VERSION 5.8 ;
BUSBITCHARS "[]" ;
DIVIDERCHAR "/" ;
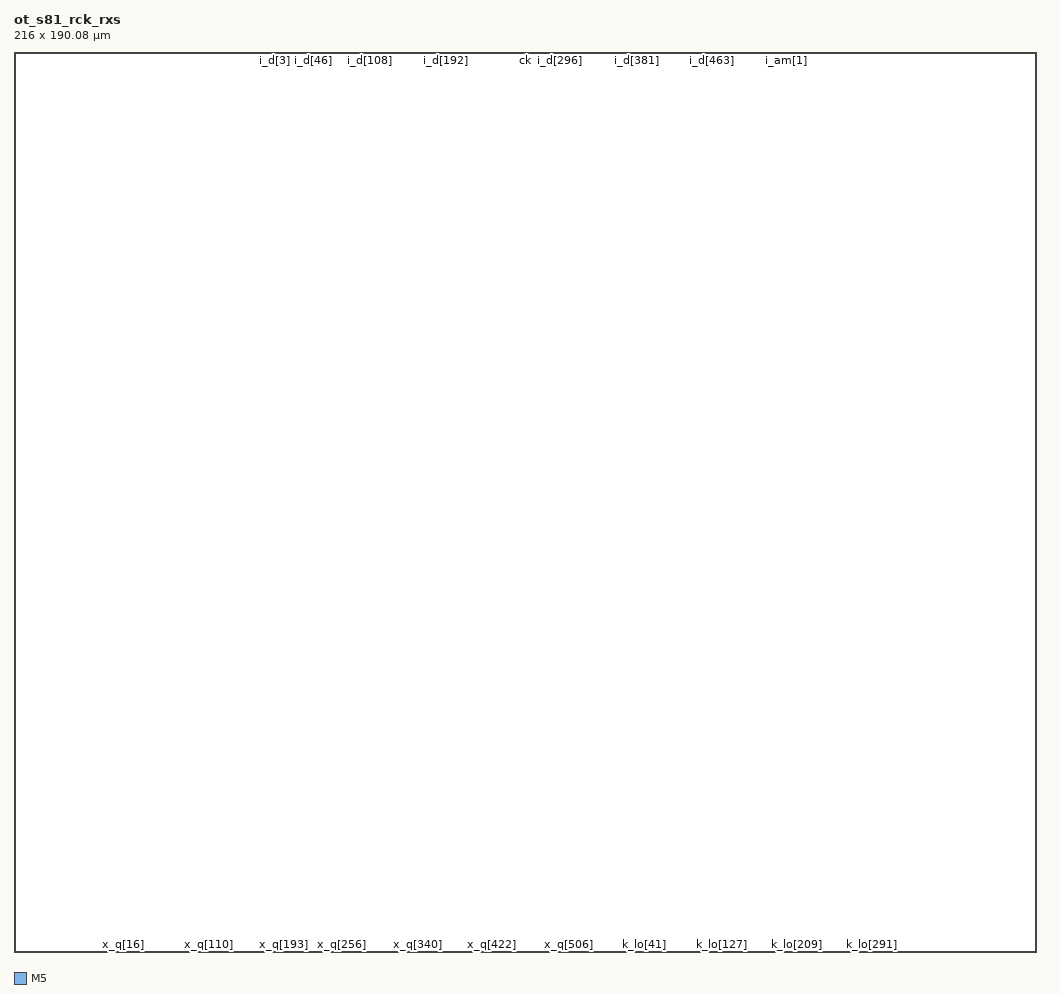
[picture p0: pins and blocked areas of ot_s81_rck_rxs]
MACRO ot_s81_rck_rxs
 CLASS BLOCK ;
 ORIGIN 0 0 ;
 SIZE 216.0 BY 190.08 ;
 SYMMETRY X Y ;
 PIN rst_n
  DIRECTION INPUT ;
  USE SIGNAL ;
  PORT
   LAYER M5 ;
   RECT 54.048 189.996 54.072 190.080 ;
  END
 END rst_n
 PIN i_v
  DIRECTION INPUT ;
  USE SIGNAL ;
  PORT
   LAYER M5 ;
   RECT 54.240 189.996 54.264 190.080 ;
  END
 END i_v
 PIN i_d[0]
  DIRECTION INPUT ;
  USE SIGNAL ;
  PORT
   LAYER M5 ;
   RECT 54.432 189.996 54.456 190.080 ;
  END
 END i_d[0]
 PIN i_d[1]
  DIRECTION INPUT ;
  USE SIGNAL ;
  PORT
   LAYER M5 ;
   RECT 54.624 189.996 54.648 190.080 ;
  END
 END i_d[1]
 PIN i_d[2]
  DIRECTION INPUT ;
  USE SIGNAL ;
  PORT
   LAYER M5 ;
   RECT 54.816 189.996 54.840 190.080 ;
  END
 END i_d[2]
 PIN i_d[3]
  DIRECTION INPUT ;
  USE SIGNAL ;
  PORT
   LAYER M5 ;
   RECT 55.008 189.996 55.032 190.080 ;
  END
 END i_d[3]
 PIN i_d[4]
  DIRECTION INPUT ;
  USE SIGNAL ;
  PORT
   LAYER M5 ;
   RECT 55.200 189.996 55.224 190.080 ;
  END
 END i_d[4]
 PIN i_d[5]
  DIRECTION INPUT ;
  USE SIGNAL ;
  PORT
   LAYER M5 ;
   RECT 55.392 189.996 55.416 190.080 ;
  END
 END i_d[5]
 PIN i_d[6]
  DIRECTION INPUT ;
  USE SIGNAL ;
  PORT
   LAYER M5 ;
   RECT 55.584 189.996 55.608 190.080 ;
  END
 END i_d[6]
 PIN i_d[7]
  DIRECTION INPUT ;
  USE SIGNAL ;
  PORT
   LAYER M5 ;
   RECT 55.776 189.996 55.800 190.080 ;
  END
 END i_d[7]
 PIN i_d[8]
  DIRECTION INPUT ;
  USE SIGNAL ;
  PORT
   LAYER M5 ;
   RECT 55.968 189.996 55.992 190.080 ;
  END
 END i_d[8]
 PIN i_d[9]
  DIRECTION INPUT ;
  USE SIGNAL ;
  PORT
   LAYER M5 ;
   RECT 56.160 189.996 56.184 190.080 ;
  END
 END i_d[9]
 PIN i_d[10]
  DIRECTION INPUT ;
  USE SIGNAL ;
  PORT
   LAYER M5 ;
   RECT 56.352 189.996 56.376 190.080 ;
  END
 END i_d[10]
 PIN i_d[11]
  DIRECTION INPUT ;
  USE SIGNAL ;
  PORT
   LAYER M5 ;
   RECT 56.544 189.996 56.568 190.080 ;
  END
 END i_d[11]
 PIN i_d[12]
  DIRECTION INPUT ;
  USE SIGNAL ;
  PORT
   LAYER M5 ;
   RECT 56.736 189.996 56.760 190.080 ;
  END
 END i_d[12]
 PIN i_d[13]
  DIRECTION INPUT ;
  USE SIGNAL ;
  PORT
   LAYER M5 ;
   RECT 56.928 189.996 56.952 190.080 ;
  END
 END i_d[13]
 PIN i_d[14]
  DIRECTION INPUT ;
  USE SIGNAL ;
  PORT
   LAYER M5 ;
   RECT 57.120 189.996 57.144 190.080 ;
  END
 END i_d[14]
 PIN i_d[15]
  DIRECTION INPUT ;
  USE SIGNAL ;
  PORT
   LAYER M5 ;
   RECT 57.312 189.996 57.336 190.080 ;
  END
 END i_d[15]
 PIN i_d[16]
  DIRECTION INPUT ;
  USE SIGNAL ;
  PORT
   LAYER M5 ;
   RECT 57.504 189.996 57.528 190.080 ;
  END
 END i_d[16]
 PIN i_d[17]
  DIRECTION INPUT ;
  USE SIGNAL ;
  PORT
   LAYER M5 ;
   RECT 57.696 189.996 57.720 190.080 ;
  END
 END i_d[17]
 PIN i_d[18]
  DIRECTION INPUT ;
  USE SIGNAL ;
  PORT
   LAYER M5 ;
   RECT 57.888 189.996 57.912 190.080 ;
  END
 END i_d[18]
 PIN i_d[19]
  DIRECTION INPUT ;
  USE SIGNAL ;
  PORT
   LAYER M5 ;
   RECT 58.080 189.996 58.104 190.080 ;
  END
 END i_d[19]
 PIN i_d[20]
  DIRECTION INPUT ;
  USE SIGNAL ;
  PORT
   LAYER M5 ;
   RECT 58.272 189.996 58.296 190.080 ;
  END
 END i_d[20]
 PIN i_d[21]
  DIRECTION INPUT ;
  USE SIGNAL ;
  PORT
   LAYER M5 ;
   RECT 58.464 189.996 58.488 190.080 ;
  END
 END i_d[21]
 PIN i_d[22]
  DIRECTION INPUT ;
  USE SIGNAL ;
  PORT
   LAYER M5 ;
   RECT 58.656 189.996 58.680 190.080 ;
  END
 END i_d[22]
 PIN i_d[23]
  DIRECTION INPUT ;
  USE SIGNAL ;
  PORT
   LAYER M5 ;
   RECT 58.848 189.996 58.872 190.080 ;
  END
 END i_d[23]
 PIN i_d[24]
  DIRECTION INPUT ;
  USE SIGNAL ;
  PORT
   LAYER M5 ;
   RECT 59.040 189.996 59.064 190.080 ;
  END
 END i_d[24]
 PIN i_d[25]
  DIRECTION INPUT ;
  USE SIGNAL ;
  PORT
   LAYER M5 ;
   RECT 59.232 189.996 59.256 190.080 ;
  END
 END i_d[25]
 PIN i_d[26]
  DIRECTION INPUT ;
  USE SIGNAL ;
  PORT
   LAYER M5 ;
   RECT 59.424 189.996 59.448 190.080 ;
  END
 END i_d[26]
 PIN i_d[27]
  DIRECTION INPUT ;
  USE SIGNAL ;
  PORT
   LAYER M5 ;
   RECT 59.616 189.996 59.640 190.080 ;
  END
 END i_d[27]
 PIN i_d[28]
  DIRECTION INPUT ;
  USE SIGNAL ;
  PORT
   LAYER M5 ;
   RECT 59.808 189.996 59.832 190.080 ;
  END
 END i_d[28]
 PIN i_d[29]
  DIRECTION INPUT ;
  USE SIGNAL ;
  PORT
   LAYER M5 ;
   RECT 60.000 189.996 60.024 190.080 ;
  END
 END i_d[29]
 PIN i_d[30]
  DIRECTION INPUT ;
  USE SIGNAL ;
  PORT
   LAYER M5 ;
   RECT 60.192 189.996 60.216 190.080 ;
  END
 END i_d[30]
 PIN i_d[31]
  DIRECTION INPUT ;
  USE SIGNAL ;
  PORT
   LAYER M5 ;
   RECT 60.384 189.996 60.408 190.080 ;
  END
 END i_d[31]
 PIN i_d[32]
  DIRECTION INPUT ;
  USE SIGNAL ;
  PORT
   LAYER M5 ;
   RECT 60.576 189.996 60.600 190.080 ;
  END
 END i_d[32]
 PIN i_d[33]
  DIRECTION INPUT ;
  USE SIGNAL ;
  PORT
   LAYER M5 ;
   RECT 60.768 189.996 60.792 190.080 ;
  END
 END i_d[33]
 PIN i_d[34]
  DIRECTION INPUT ;
  USE SIGNAL ;
  PORT
   LAYER M5 ;
   RECT 60.960 189.996 60.984 190.080 ;
  END
 END i_d[34]
 PIN i_d[35]
  DIRECTION INPUT ;
  USE SIGNAL ;
  PORT
   LAYER M5 ;
   RECT 61.152 189.996 61.176 190.080 ;
  END
 END i_d[35]
 PIN i_d[36]
  DIRECTION INPUT ;
  USE SIGNAL ;
  PORT
   LAYER M5 ;
   RECT 61.344 189.996 61.368 190.080 ;
  END
 END i_d[36]
 PIN i_d[37]
  DIRECTION INPUT ;
  USE SIGNAL ;
  PORT
   LAYER M5 ;
   RECT 61.536 189.996 61.560 190.080 ;
  END
 END i_d[37]
 PIN i_d[38]
  DIRECTION INPUT ;
  USE SIGNAL ;
  PORT
   LAYER M5 ;
   RECT 61.728 189.996 61.752 190.080 ;
  END
 END i_d[38]
 PIN i_d[39]
  DIRECTION INPUT ;
  USE SIGNAL ;
  PORT
   LAYER M5 ;
   RECT 61.920 189.996 61.944 190.080 ;
  END
 END i_d[39]
 PIN i_d[40]
  DIRECTION INPUT ;
  USE SIGNAL ;
  PORT
   LAYER M5 ;
   RECT 62.112 189.996 62.136 190.080 ;
  END
 END i_d[40]
 PIN i_d[41]
  DIRECTION INPUT ;
  USE SIGNAL ;
  PORT
   LAYER M5 ;
   RECT 62.304 189.996 62.328 190.080 ;
  END
 END i_d[41]
 PIN i_d[42]
  DIRECTION INPUT ;
  USE SIGNAL ;
  PORT
   LAYER M5 ;
   RECT 62.496 189.996 62.520 190.080 ;
  END
 END i_d[42]
 PIN i_d[43]
  DIRECTION INPUT ;
  USE SIGNAL ;
  PORT
   LAYER M5 ;
   RECT 62.688 189.996 62.712 190.080 ;
  END
 END i_d[43]
 PIN i_d[44]
  DIRECTION INPUT ;
  USE SIGNAL ;
  PORT
   LAYER M5 ;
   RECT 62.880 189.996 62.904 190.080 ;
  END
 END i_d[44]
 PIN i_d[45]
  DIRECTION INPUT ;
  USE SIGNAL ;
  PORT
   LAYER M5 ;
   RECT 63.072 189.996 63.096 190.080 ;
  END
 END i_d[45]
 PIN i_d[46]
  DIRECTION INPUT ;
  USE SIGNAL ;
  PORT
   LAYER M5 ;
   RECT 63.264 189.996 63.288 190.080 ;
  END
 END i_d[46]
 PIN i_d[47]
  DIRECTION INPUT ;
  USE SIGNAL ;
  PORT
   LAYER M5 ;
   RECT 63.456 189.996 63.480 190.080 ;
  END
 END i_d[47]
 PIN i_d[48]
  DIRECTION INPUT ;
  USE SIGNAL ;
  PORT
   LAYER M5 ;
   RECT 63.648 189.996 63.672 190.080 ;
  END
 END i_d[48]
 PIN i_d[49]
  DIRECTION INPUT ;
  USE SIGNAL ;
  PORT
   LAYER M5 ;
   RECT 63.840 189.996 63.864 190.080 ;
  END
 END i_d[49]
 PIN i_d[50]
  DIRECTION INPUT ;
  USE SIGNAL ;
  PORT
   LAYER M5 ;
   RECT 64.032 189.996 64.056 190.080 ;
  END
 END i_d[50]
 PIN i_d[51]
  DIRECTION INPUT ;
  USE SIGNAL ;
  PORT
   LAYER M5 ;
   RECT 64.224 189.996 64.248 190.080 ;
  END
 END i_d[51]
 PIN i_d[52]
  DIRECTION INPUT ;
  USE SIGNAL ;
  PORT
   LAYER M5 ;
   RECT 64.416 189.996 64.440 190.080 ;
  END
 END i_d[52]
 PIN i_d[53]
  DIRECTION INPUT ;
  USE SIGNAL ;
  PORT
   LAYER M5 ;
   RECT 64.608 189.996 64.632 190.080 ;
  END
 END i_d[53]
 PIN i_d[54]
  DIRECTION INPUT ;
  USE SIGNAL ;
  PORT
   LAYER M5 ;
   RECT 64.800 189.996 64.824 190.080 ;
  END
 END i_d[54]
 PIN i_d[55]
  DIRECTION INPUT ;
  USE SIGNAL ;
  PORT
   LAYER M5 ;
   RECT 64.992 189.996 65.016 190.080 ;
  END
 END i_d[55]
 PIN i_d[56]
  DIRECTION INPUT ;
  USE SIGNAL ;
  PORT
   LAYER M5 ;
   RECT 65.184 189.996 65.208 190.080 ;
  END
 END i_d[56]
 PIN i_d[57]
  DIRECTION INPUT ;
  USE SIGNAL ;
  PORT
   LAYER M5 ;
   RECT 65.376 189.996 65.400 190.080 ;
  END
 END i_d[57]
 PIN i_d[58]
  DIRECTION INPUT ;
  USE SIGNAL ;
  PORT
   LAYER M5 ;
   RECT 65.568 189.996 65.592 190.080 ;
  END
 END i_d[58]
 PIN i_d[59]
  DIRECTION INPUT ;
  USE SIGNAL ;
  PORT
   LAYER M5 ;
   RECT 65.760 189.996 65.784 190.080 ;
  END
 END i_d[59]
 PIN i_d[60]
  DIRECTION INPUT ;
  USE SIGNAL ;
  PORT
   LAYER M5 ;
   RECT 65.952 189.996 65.976 190.080 ;
  END
 END i_d[60]
 PIN i_d[61]
  DIRECTION INPUT ;
  USE SIGNAL ;
  PORT
   LAYER M5 ;
   RECT 66.144 189.996 66.168 190.080 ;
  END
 END i_d[61]
 PIN i_d[62]
  DIRECTION INPUT ;
  USE SIGNAL ;
  PORT
   LAYER M5 ;
   RECT 66.336 189.996 66.360 190.080 ;
  END
 END i_d[62]
 PIN i_d[63]
  DIRECTION INPUT ;
  USE SIGNAL ;
  PORT
   LAYER M5 ;
   RECT 66.528 189.996 66.552 190.080 ;
  END
 END i_d[63]
 PIN i_d[64]
  DIRECTION INPUT ;
  USE SIGNAL ;
  PORT
   LAYER M5 ;
   RECT 66.720 189.996 66.744 190.080 ;
  END
 END i_d[64]
 PIN i_d[65]
  DIRECTION INPUT ;
  USE SIGNAL ;
  PORT
   LAYER M5 ;
   RECT 66.912 189.996 66.936 190.080 ;
  END
 END i_d[65]
 PIN i_d[66]
  DIRECTION INPUT ;
  USE SIGNAL ;
  PORT
   LAYER M5 ;
   RECT 67.104 189.996 67.128 190.080 ;
  END
 END i_d[66]
 PIN i_d[67]
  DIRECTION INPUT ;
  USE SIGNAL ;
  PORT
   LAYER M5 ;
   RECT 67.296 189.996 67.320 190.080 ;
  END
 END i_d[67]
 PIN i_d[68]
  DIRECTION INPUT ;
  USE SIGNAL ;
  PORT
   LAYER M5 ;
   RECT 67.488 189.996 67.512 190.080 ;
  END
 END i_d[68]
 PIN i_d[69]
  DIRECTION INPUT ;
  USE SIGNAL ;
  PORT
   LAYER M5 ;
   RECT 67.680 189.996 67.704 190.080 ;
  END
 END i_d[69]
 PIN i_d[70]
  DIRECTION INPUT ;
  USE SIGNAL ;
  PORT
   LAYER M5 ;
   RECT 67.872 189.996 67.896 190.080 ;
  END
 END i_d[70]
 PIN i_d[71]
  DIRECTION INPUT ;
  USE SIGNAL ;
  PORT
   LAYER M5 ;
   RECT 68.064 189.996 68.088 190.080 ;
  END
 END i_d[71]
 PIN i_d[72]
  DIRECTION INPUT ;
  USE SIGNAL ;
  PORT
   LAYER M5 ;
   RECT 68.256 189.996 68.280 190.080 ;
  END
 END i_d[72]
 PIN i_d[73]
  DIRECTION INPUT ;
  USE SIGNAL ;
  PORT
   LAYER M5 ;
   RECT 68.448 189.996 68.472 190.080 ;
  END
 END i_d[73]
 PIN i_d[74]
  DIRECTION INPUT ;
  USE SIGNAL ;
  PORT
   LAYER M5 ;
   RECT 68.640 189.996 68.664 190.080 ;
  END
 END i_d[74]
 PIN i_d[75]
  DIRECTION INPUT ;
  USE SIGNAL ;
  PORT
   LAYER M5 ;
   RECT 68.832 189.996 68.856 190.080 ;
  END
 END i_d[75]
 PIN i_d[76]
  DIRECTION INPUT ;
  USE SIGNAL ;
  PORT
   LAYER M5 ;
   RECT 69.024 189.996 69.048 190.080 ;
  END
 END i_d[76]
 PIN i_d[77]
  DIRECTION INPUT ;
  USE SIGNAL ;
  PORT
   LAYER M5 ;
   RECT 69.216 189.996 69.240 190.080 ;
  END
 END i_d[77]
 PIN i_d[78]
  DIRECTION INPUT ;
  USE SIGNAL ;
  PORT
   LAYER M5 ;
   RECT 69.408 189.996 69.432 190.080 ;
  END
 END i_d[78]
 PIN i_d[79]
  DIRECTION INPUT ;
  USE SIGNAL ;
  PORT
   LAYER M5 ;
   RECT 69.600 189.996 69.624 190.080 ;
  END
 END i_d[79]
 PIN i_d[80]
  DIRECTION INPUT ;
  USE SIGNAL ;
  PORT
   LAYER M5 ;
   RECT 69.792 189.996 69.816 190.080 ;
  END
 END i_d[80]
 PIN i_d[81]
  DIRECTION INPUT ;
  USE SIGNAL ;
  PORT
   LAYER M5 ;
   RECT 69.984 189.996 70.008 190.080 ;
  END
 END i_d[81]
 PIN i_d[82]
  DIRECTION INPUT ;
  USE SIGNAL ;
  PORT
   LAYER M5 ;
   RECT 70.176 189.996 70.200 190.080 ;
  END
 END i_d[82]
 PIN i_d[83]
  DIRECTION INPUT ;
  USE SIGNAL ;
  PORT
   LAYER M5 ;
   RECT 70.368 189.996 70.392 190.080 ;
  END
 END i_d[83]
 PIN i_d[84]
  DIRECTION INPUT ;
  USE SIGNAL ;
  PORT
   LAYER M5 ;
   RECT 70.560 189.996 70.584 190.080 ;
  END
 END i_d[84]
 PIN i_d[85]
  DIRECTION INPUT ;
  USE SIGNAL ;
  PORT
   LAYER M5 ;
   RECT 70.752 189.996 70.776 190.080 ;
  END
 END i_d[85]
 PIN i_d[86]
  DIRECTION INPUT ;
  USE SIGNAL ;
  PORT
   LAYER M5 ;
   RECT 70.944 189.996 70.968 190.080 ;
  END
 END i_d[86]
 PIN i_d[87]
  DIRECTION INPUT ;
  USE SIGNAL ;
  PORT
   LAYER M5 ;
   RECT 71.136 189.996 71.160 190.080 ;
  END
 END i_d[87]
 PIN i_d[88]
  DIRECTION INPUT ;
  USE SIGNAL ;
  PORT
   LAYER M5 ;
   RECT 71.328 189.996 71.352 190.080 ;
  END
 END i_d[88]
 PIN i_d[89]
  DIRECTION INPUT ;
  USE SIGNAL ;
  PORT
   LAYER M5 ;
   RECT 71.520 189.996 71.544 190.080 ;
  END
 END i_d[89]
 PIN i_d[90]
  DIRECTION INPUT ;
  USE SIGNAL ;
  PORT
   LAYER M5 ;
   RECT 71.712 189.996 71.736 190.080 ;
  END
 END i_d[90]
 PIN i_d[91]
  DIRECTION INPUT ;
  USE SIGNAL ;
  PORT
   LAYER M5 ;
   RECT 71.904 189.996 71.928 190.080 ;
  END
 END i_d[91]
 PIN i_d[92]
  DIRECTION INPUT ;
  USE SIGNAL ;
  PORT
   LAYER M5 ;
   RECT 72.096 189.996 72.120 190.080 ;
  END
 END i_d[92]
 PIN i_d[93]
  DIRECTION INPUT ;
  USE SIGNAL ;
  PORT
   LAYER M5 ;
   RECT 72.288 189.996 72.312 190.080 ;
  END
 END i_d[93]
 PIN i_d[94]
  DIRECTION INPUT ;
  USE SIGNAL ;
  PORT
   LAYER M5 ;
   RECT 72.480 189.996 72.504 190.080 ;
  END
 END i_d[94]
 PIN i_d[95]
  DIRECTION INPUT ;
  USE SIGNAL ;
  PORT
   LAYER M5 ;
   RECT 72.672 189.996 72.696 190.080 ;
  END
 END i_d[95]
 PIN i_d[96]
  DIRECTION INPUT ;
  USE SIGNAL ;
  PORT
   LAYER M5 ;
   RECT 72.864 189.996 72.888 190.080 ;
  END
 END i_d[96]
 PIN i_d[97]
  DIRECTION INPUT ;
  USE SIGNAL ;
  PORT
   LAYER M5 ;
   RECT 73.056 189.996 73.080 190.080 ;
  END
 END i_d[97]
 PIN i_d[98]
  DIRECTION INPUT ;
  USE SIGNAL ;
  PORT
   LAYER M5 ;
   RECT 73.248 189.996 73.272 190.080 ;
  END
 END i_d[98]
 PIN i_d[99]
  DIRECTION INPUT ;
  USE SIGNAL ;
  PORT
   LAYER M5 ;
   RECT 73.440 189.996 73.464 190.080 ;
  END
 END i_d[99]
 PIN i_d[100]
  DIRECTION INPUT ;
  USE SIGNAL ;
  PORT
   LAYER M5 ;
   RECT 73.632 189.996 73.656 190.080 ;
  END
 END i_d[100]
 PIN i_d[101]
  DIRECTION INPUT ;
  USE SIGNAL ;
  PORT
   LAYER M5 ;
   RECT 73.824 189.996 73.848 190.080 ;
  END
 END i_d[101]
 PIN i_d[102]
  DIRECTION INPUT ;
  USE SIGNAL ;
  PORT
   LAYER M5 ;
   RECT 74.016 189.996 74.040 190.080 ;
  END
 END i_d[102]
 PIN i_d[103]
  DIRECTION INPUT ;
  USE SIGNAL ;
  PORT
   LAYER M5 ;
   RECT 74.208 189.996 74.232 190.080 ;
  END
 END i_d[103]
 PIN i_d[104]
  DIRECTION INPUT ;
  USE SIGNAL ;
  PORT
   LAYER M5 ;
   RECT 74.400 189.996 74.424 190.080 ;
  END
 END i_d[104]
 PIN i_d[105]
  DIRECTION INPUT ;
  USE SIGNAL ;
  PORT
   LAYER M5 ;
   RECT 74.592 189.996 74.616 190.080 ;
  END
 END i_d[105]
 PIN i_d[106]
  DIRECTION INPUT ;
  USE SIGNAL ;
  PORT
   LAYER M5 ;
   RECT 74.784 189.996 74.808 190.080 ;
  END
 END i_d[106]
 PIN i_d[107]
  DIRECTION INPUT ;
  USE SIGNAL ;
  PORT
   LAYER M5 ;
   RECT 74.976 189.996 75.000 190.080 ;
  END
 END i_d[107]
 PIN i_d[108]
  DIRECTION INPUT ;
  USE SIGNAL ;
  PORT
   LAYER M5 ;
   RECT 75.168 189.996 75.192 190.080 ;
  END
 END i_d[108]
 PIN i_d[109]
  DIRECTION INPUT ;
  USE SIGNAL ;
  PORT
   LAYER M5 ;
   RECT 75.360 189.996 75.384 190.080 ;
  END
 END i_d[109]
 PIN i_d[110]
  DIRECTION INPUT ;
  USE SIGNAL ;
  PORT
   LAYER M5 ;
   RECT 75.552 189.996 75.576 190.080 ;
  END
 END i_d[110]
 PIN i_d[111]
  DIRECTION INPUT ;
  USE SIGNAL ;
  PORT
   LAYER M5 ;
   RECT 75.744 189.996 75.768 190.080 ;
  END
 END i_d[111]
 PIN i_d[112]
  DIRECTION INPUT ;
  USE SIGNAL ;
  PORT
   LAYER M5 ;
   RECT 75.936 189.996 75.960 190.080 ;
  END
 END i_d[112]
 PIN i_d[113]
  DIRECTION INPUT ;
  USE SIGNAL ;
  PORT
   LAYER M5 ;
   RECT 76.128 189.996 76.152 190.080 ;
  END
 END i_d[113]
 PIN i_d[114]
  DIRECTION INPUT ;
  USE SIGNAL ;
  PORT
   LAYER M5 ;
   RECT 76.320 189.996 76.344 190.080 ;
  END
 END i_d[114]
 PIN i_d[115]
  DIRECTION INPUT ;
  USE SIGNAL ;
  PORT
   LAYER M5 ;
   RECT 76.512 189.996 76.536 190.080 ;
  END
 END i_d[115]
 PIN i_d[116]
  DIRECTION INPUT ;
  USE SIGNAL ;
  PORT
   LAYER M5 ;
   RECT 76.704 189.996 76.728 190.080 ;
  END
 END i_d[116]
 PIN i_d[117]
  DIRECTION INPUT ;
  USE SIGNAL ;
  PORT
   LAYER M5 ;
   RECT 76.896 189.996 76.920 190.080 ;
  END
 END i_d[117]
 PIN i_d[118]
  DIRECTION INPUT ;
  USE SIGNAL ;
  PORT
   LAYER M5 ;
   RECT 77.088 189.996 77.112 190.080 ;
  END
 END i_d[118]
 PIN i_d[119]
  DIRECTION INPUT ;
  USE SIGNAL ;
  PORT
   LAYER M5 ;
   RECT 77.280 189.996 77.304 190.080 ;
  END
 END i_d[119]
 PIN i_d[120]
  DIRECTION INPUT ;
  USE SIGNAL ;
  PORT
   LAYER M5 ;
   RECT 77.472 189.996 77.496 190.080 ;
  END
 END i_d[120]
 PIN i_d[121]
  DIRECTION INPUT ;
  USE SIGNAL ;
  PORT
   LAYER M5 ;
   RECT 77.664 189.996 77.688 190.080 ;
  END
 END i_d[121]
 PIN i_d[122]
  DIRECTION INPUT ;
  USE SIGNAL ;
  PORT
   LAYER M5 ;
   RECT 77.856 189.996 77.880 190.080 ;
  END
 END i_d[122]
 PIN i_d[123]
  DIRECTION INPUT ;
  USE SIGNAL ;
  PORT
   LAYER M5 ;
   RECT 78.048 189.996 78.072 190.080 ;
  END
 END i_d[123]
 PIN i_d[124]
  DIRECTION INPUT ;
  USE SIGNAL ;
  PORT
   LAYER M5 ;
   RECT 78.240 189.996 78.264 190.080 ;
  END
 END i_d[124]
 PIN i_d[125]
  DIRECTION INPUT ;
  USE SIGNAL ;
  PORT
   LAYER M5 ;
   RECT 78.432 189.996 78.456 190.080 ;
  END
 END i_d[125]
 PIN i_d[126]
  DIRECTION INPUT ;
  USE SIGNAL ;
  PORT
   LAYER M5 ;
   RECT 78.624 189.996 78.648 190.080 ;
  END
 END i_d[126]
 PIN i_d[127]
  DIRECTION INPUT ;
  USE SIGNAL ;
  PORT
   LAYER M5 ;
   RECT 78.816 189.996 78.840 190.080 ;
  END
 END i_d[127]
 PIN i_d[128]
  DIRECTION INPUT ;
  USE SIGNAL ;
  PORT
   LAYER M5 ;
   RECT 79.008 189.996 79.032 190.080 ;
  END
 END i_d[128]
 PIN i_d[129]
  DIRECTION INPUT ;
  USE SIGNAL ;
  PORT
   LAYER M5 ;
   RECT 79.200 189.996 79.224 190.080 ;
  END
 END i_d[129]
 PIN i_d[130]
  DIRECTION INPUT ;
  USE SIGNAL ;
  PORT
   LAYER M5 ;
   RECT 79.392 189.996 79.416 190.080 ;
  END
 END i_d[130]
 PIN i_d[131]
  DIRECTION INPUT ;
  USE SIGNAL ;
  PORT
   LAYER M5 ;
   RECT 79.584 189.996 79.608 190.080 ;
  END
 END i_d[131]
 PIN i_d[132]
  DIRECTION INPUT ;
  USE SIGNAL ;
  PORT
   LAYER M5 ;
   RECT 79.776 189.996 79.800 190.080 ;
  END
 END i_d[132]
 PIN i_d[133]
  DIRECTION INPUT ;
  USE SIGNAL ;
  PORT
   LAYER M5 ;
   RECT 79.968 189.996 79.992 190.080 ;
  END
 END i_d[133]
 PIN i_d[134]
  DIRECTION INPUT ;
  USE SIGNAL ;
  PORT
   LAYER M5 ;
   RECT 80.160 189.996 80.184 190.080 ;
  END
 END i_d[134]
 PIN i_d[135]
  DIRECTION INPUT ;
  USE SIGNAL ;
  PORT
   LAYER M5 ;
   RECT 80.352 189.996 80.376 190.080 ;
  END
 END i_d[135]
 PIN i_d[136]
  DIRECTION INPUT ;
  USE SIGNAL ;
  PORT
   LAYER M5 ;
   RECT 80.544 189.996 80.568 190.080 ;
  END
 END i_d[136]
 PIN i_d[137]
  DIRECTION INPUT ;
  USE SIGNAL ;
  PORT
   LAYER M5 ;
   RECT 80.736 189.996 80.760 190.080 ;
  END
 END i_d[137]
 PIN i_d[138]
  DIRECTION INPUT ;
  USE SIGNAL ;
  PORT
   LAYER M5 ;
   RECT 80.928 189.996 80.952 190.080 ;
  END
 END i_d[138]
 PIN i_d[139]
  DIRECTION INPUT ;
  USE SIGNAL ;
  PORT
   LAYER M5 ;
   RECT 81.120 189.996 81.144 190.080 ;
  END
 END i_d[139]
 PIN i_d[140]
  DIRECTION INPUT ;
  USE SIGNAL ;
  PORT
   LAYER M5 ;
   RECT 81.312 189.996 81.336 190.080 ;
  END
 END i_d[140]
 PIN i_d[141]
  DIRECTION INPUT ;
  USE SIGNAL ;
  PORT
   LAYER M5 ;
   RECT 81.504 189.996 81.528 190.080 ;
  END
 END i_d[141]
 PIN i_d[142]
  DIRECTION INPUT ;
  USE SIGNAL ;
  PORT
   LAYER M5 ;
   RECT 81.696 189.996 81.720 190.080 ;
  END
 END i_d[142]
 PIN i_d[143]
  DIRECTION INPUT ;
  USE SIGNAL ;
  PORT
   LAYER M5 ;
   RECT 81.888 189.996 81.912 190.080 ;
  END
 END i_d[143]
 PIN i_d[144]
  DIRECTION INPUT ;
  USE SIGNAL ;
  PORT
   LAYER M5 ;
   RECT 82.080 189.996 82.104 190.080 ;
  END
 END i_d[144]
 PIN i_d[145]
  DIRECTION INPUT ;
  USE SIGNAL ;
  PORT
   LAYER M5 ;
   RECT 82.272 189.996 82.296 190.080 ;
  END
 END i_d[145]
 PIN i_d[146]
  DIRECTION INPUT ;
  USE SIGNAL ;
  PORT
   LAYER M5 ;
   RECT 82.464 189.996 82.488 190.080 ;
  END
 END i_d[146]
 PIN i_d[147]
  DIRECTION INPUT ;
  USE SIGNAL ;
  PORT
   LAYER M5 ;
   RECT 82.656 189.996 82.680 190.080 ;
  END
 END i_d[147]
 PIN i_d[148]
  DIRECTION INPUT ;
  USE SIGNAL ;
  PORT
   LAYER M5 ;
   RECT 82.848 189.996 82.872 190.080 ;
  END
 END i_d[148]
 PIN i_d[149]
  DIRECTION INPUT ;
  USE SIGNAL ;
  PORT
   LAYER M5 ;
   RECT 83.040 189.996 83.064 190.080 ;
  END
 END i_d[149]
 PIN i_d[150]
  DIRECTION INPUT ;
  USE SIGNAL ;
  PORT
   LAYER M5 ;
   RECT 83.232 189.996 83.256 190.080 ;
  END
 END i_d[150]
 PIN i_d[151]
  DIRECTION INPUT ;
  USE SIGNAL ;
  PORT
   LAYER M5 ;
   RECT 83.424 189.996 83.448 190.080 ;
  END
 END i_d[151]
 PIN i_d[152]
  DIRECTION INPUT ;
  USE SIGNAL ;
  PORT
   LAYER M5 ;
   RECT 83.616 189.996 83.640 190.080 ;
  END
 END i_d[152]
 PIN i_d[153]
  DIRECTION INPUT ;
  USE SIGNAL ;
  PORT
   LAYER M5 ;
   RECT 83.808 189.996 83.832 190.080 ;
  END
 END i_d[153]
 PIN i_d[154]
  DIRECTION INPUT ;
  USE SIGNAL ;
  PORT
   LAYER M5 ;
   RECT 84.000 189.996 84.024 190.080 ;
  END
 END i_d[154]
 PIN i_d[155]
  DIRECTION INPUT ;
  USE SIGNAL ;
  PORT
   LAYER M5 ;
   RECT 84.192 189.996 84.216 190.080 ;
  END
 END i_d[155]
 PIN i_d[156]
  DIRECTION INPUT ;
  USE SIGNAL ;
  PORT
   LAYER M5 ;
   RECT 84.384 189.996 84.408 190.080 ;
  END
 END i_d[156]
 PIN i_d[157]
  DIRECTION INPUT ;
  USE SIGNAL ;
  PORT
   LAYER M5 ;
   RECT 84.576 189.996 84.600 190.080 ;
  END
 END i_d[157]
 PIN i_d[158]
  DIRECTION INPUT ;
  USE SIGNAL ;
  PORT
   LAYER M5 ;
   RECT 84.768 189.996 84.792 190.080 ;
  END
 END i_d[158]
 PIN i_d[159]
  DIRECTION INPUT ;
  USE SIGNAL ;
  PORT
   LAYER M5 ;
   RECT 84.960 189.996 84.984 190.080 ;
  END
 END i_d[159]
 PIN i_d[160]
  DIRECTION INPUT ;
  USE SIGNAL ;
  PORT
   LAYER M5 ;
   RECT 85.152 189.996 85.176 190.080 ;
  END
 END i_d[160]
 PIN i_d[161]
  DIRECTION INPUT ;
  USE SIGNAL ;
  PORT
   LAYER M5 ;
   RECT 85.344 189.996 85.368 190.080 ;
  END
 END i_d[161]
 PIN i_d[162]
  DIRECTION INPUT ;
  USE SIGNAL ;
  PORT
   LAYER M5 ;
   RECT 85.536 189.996 85.560 190.080 ;
  END
 END i_d[162]
 PIN i_d[163]
  DIRECTION INPUT ;
  USE SIGNAL ;
  PORT
   LAYER M5 ;
   RECT 85.728 189.996 85.752 190.080 ;
  END
 END i_d[163]
 PIN i_d[164]
  DIRECTION INPUT ;
  USE SIGNAL ;
  PORT
   LAYER M5 ;
   RECT 85.920 189.996 85.944 190.080 ;
  END
 END i_d[164]
 PIN i_d[165]
  DIRECTION INPUT ;
  USE SIGNAL ;
  PORT
   LAYER M5 ;
   RECT 86.112 189.996 86.136 190.080 ;
  END
 END i_d[165]
 PIN i_d[166]
  DIRECTION INPUT ;
  USE SIGNAL ;
  PORT
   LAYER M5 ;
   RECT 86.304 189.996 86.328 190.080 ;
  END
 END i_d[166]
 PIN i_d[167]
  DIRECTION INPUT ;
  USE SIGNAL ;
  PORT
   LAYER M5 ;
   RECT 86.496 189.996 86.520 190.080 ;
  END
 END i_d[167]
 PIN i_d[168]
  DIRECTION INPUT ;
  USE SIGNAL ;
  PORT
   LAYER M5 ;
   RECT 86.688 189.996 86.712 190.080 ;
  END
 END i_d[168]
 PIN i_d[169]
  DIRECTION INPUT ;
  USE SIGNAL ;
  PORT
   LAYER M5 ;
   RECT 86.880 189.996 86.904 190.080 ;
  END
 END i_d[169]
 PIN i_d[170]
  DIRECTION INPUT ;
  USE SIGNAL ;
  PORT
   LAYER M5 ;
   RECT 87.072 189.996 87.096 190.080 ;
  END
 END i_d[170]
 PIN i_d[171]
  DIRECTION INPUT ;
  USE SIGNAL ;
  PORT
   LAYER M5 ;
   RECT 87.264 189.996 87.288 190.080 ;
  END
 END i_d[171]
 PIN i_d[172]
  DIRECTION INPUT ;
  USE SIGNAL ;
  PORT
   LAYER M5 ;
   RECT 87.456 189.996 87.480 190.080 ;
  END
 END i_d[172]
 PIN i_d[173]
  DIRECTION INPUT ;
  USE SIGNAL ;
  PORT
   LAYER M5 ;
   RECT 87.648 189.996 87.672 190.080 ;
  END
 END i_d[173]
 PIN i_d[174]
  DIRECTION INPUT ;
  USE SIGNAL ;
  PORT
   LAYER M5 ;
   RECT 87.840 189.996 87.864 190.080 ;
  END
 END i_d[174]
 PIN i_d[175]
  DIRECTION INPUT ;
  USE SIGNAL ;
  PORT
   LAYER M5 ;
   RECT 88.032 189.996 88.056 190.080 ;
  END
 END i_d[175]
 PIN i_d[176]
  DIRECTION INPUT ;
  USE SIGNAL ;
  PORT
   LAYER M5 ;
   RECT 88.224 189.996 88.248 190.080 ;
  END
 END i_d[176]
 PIN i_d[177]
  DIRECTION INPUT ;
  USE SIGNAL ;
  PORT
   LAYER M5 ;
   RECT 88.416 189.996 88.440 190.080 ;
  END
 END i_d[177]
 PIN i_d[178]
  DIRECTION INPUT ;
  USE SIGNAL ;
  PORT
   LAYER M5 ;
   RECT 88.608 189.996 88.632 190.080 ;
  END
 END i_d[178]
 PIN i_d[179]
  DIRECTION INPUT ;
  USE SIGNAL ;
  PORT
   LAYER M5 ;
   RECT 88.800 189.996 88.824 190.080 ;
  END
 END i_d[179]
 PIN i_d[180]
  DIRECTION INPUT ;
  USE SIGNAL ;
  PORT
   LAYER M5 ;
   RECT 88.992 189.996 89.016 190.080 ;
  END
 END i_d[180]
 PIN i_d[181]
  DIRECTION INPUT ;
  USE SIGNAL ;
  PORT
   LAYER M5 ;
   RECT 89.184 189.996 89.208 190.080 ;
  END
 END i_d[181]
 PIN i_d[182]
  DIRECTION INPUT ;
  USE SIGNAL ;
  PORT
   LAYER M5 ;
   RECT 89.376 189.996 89.400 190.080 ;
  END
 END i_d[182]
 PIN i_d[183]
  DIRECTION INPUT ;
  USE SIGNAL ;
  PORT
   LAYER M5 ;
   RECT 89.568 189.996 89.592 190.080 ;
  END
 END i_d[183]
 PIN i_d[184]
  DIRECTION INPUT ;
  USE SIGNAL ;
  PORT
   LAYER M5 ;
   RECT 89.760 189.996 89.784 190.080 ;
  END
 END i_d[184]
 PIN i_d[185]
  DIRECTION INPUT ;
  USE SIGNAL ;
  PORT
   LAYER M5 ;
   RECT 89.952 189.996 89.976 190.080 ;
  END
 END i_d[185]
 PIN i_d[186]
  DIRECTION INPUT ;
  USE SIGNAL ;
  PORT
   LAYER M5 ;
   RECT 90.144 189.996 90.168 190.080 ;
  END
 END i_d[186]
 PIN i_d[187]
  DIRECTION INPUT ;
  USE SIGNAL ;
  PORT
   LAYER M5 ;
   RECT 90.336 189.996 90.360 190.080 ;
  END
 END i_d[187]
 PIN i_d[188]
  DIRECTION INPUT ;
  USE SIGNAL ;
  PORT
   LAYER M5 ;
   RECT 90.528 189.996 90.552 190.080 ;
  END
 END i_d[188]
 PIN i_d[189]
  DIRECTION INPUT ;
  USE SIGNAL ;
  PORT
   LAYER M5 ;
   RECT 90.720 189.996 90.744 190.080 ;
  END
 END i_d[189]
 PIN i_d[190]
  DIRECTION INPUT ;
  USE SIGNAL ;
  PORT
   LAYER M5 ;
   RECT 90.912 189.996 90.936 190.080 ;
  END
 END i_d[190]
 PIN i_d[191]
  DIRECTION INPUT ;
  USE SIGNAL ;
  PORT
   LAYER M5 ;
   RECT 91.104 189.996 91.128 190.080 ;
  END
 END i_d[191]
 PIN i_d[192]
  DIRECTION INPUT ;
  USE SIGNAL ;
  PORT
   LAYER M5 ;
   RECT 91.296 189.996 91.320 190.080 ;
  END
 END i_d[192]
 PIN i_d[193]
  DIRECTION INPUT ;
  USE SIGNAL ;
  PORT
   LAYER M5 ;
   RECT 91.488 189.996 91.512 190.080 ;
  END
 END i_d[193]
 PIN i_d[194]
  DIRECTION INPUT ;
  USE SIGNAL ;
  PORT
   LAYER M5 ;
   RECT 91.680 189.996 91.704 190.080 ;
  END
 END i_d[194]
 PIN i_d[195]
  DIRECTION INPUT ;
  USE SIGNAL ;
  PORT
   LAYER M5 ;
   RECT 91.872 189.996 91.896 190.080 ;
  END
 END i_d[195]
 PIN i_d[196]
  DIRECTION INPUT ;
  USE SIGNAL ;
  PORT
   LAYER M5 ;
   RECT 92.064 189.996 92.088 190.080 ;
  END
 END i_d[196]
 PIN i_d[197]
  DIRECTION INPUT ;
  USE SIGNAL ;
  PORT
   LAYER M5 ;
   RECT 92.256 189.996 92.280 190.080 ;
  END
 END i_d[197]
 PIN i_d[198]
  DIRECTION INPUT ;
  USE SIGNAL ;
  PORT
   LAYER M5 ;
   RECT 92.448 189.996 92.472 190.080 ;
  END
 END i_d[198]
 PIN i_d[199]
  DIRECTION INPUT ;
  USE SIGNAL ;
  PORT
   LAYER M5 ;
   RECT 92.640 189.996 92.664 190.080 ;
  END
 END i_d[199]
 PIN i_d[200]
  DIRECTION INPUT ;
  USE SIGNAL ;
  PORT
   LAYER M5 ;
   RECT 92.832 189.996 92.856 190.080 ;
  END
 END i_d[200]
 PIN i_d[201]
  DIRECTION INPUT ;
  USE SIGNAL ;
  PORT
   LAYER M5 ;
   RECT 93.024 189.996 93.048 190.080 ;
  END
 END i_d[201]
 PIN i_d[202]
  DIRECTION INPUT ;
  USE SIGNAL ;
  PORT
   LAYER M5 ;
   RECT 93.216 189.996 93.240 190.080 ;
  END
 END i_d[202]
 PIN i_d[203]
  DIRECTION INPUT ;
  USE SIGNAL ;
  PORT
   LAYER M5 ;
   RECT 93.408 189.996 93.432 190.080 ;
  END
 END i_d[203]
 PIN i_d[204]
  DIRECTION INPUT ;
  USE SIGNAL ;
  PORT
   LAYER M5 ;
   RECT 93.600 189.996 93.624 190.080 ;
  END
 END i_d[204]
 PIN i_d[205]
  DIRECTION INPUT ;
  USE SIGNAL ;
  PORT
   LAYER M5 ;
   RECT 93.792 189.996 93.816 190.080 ;
  END
 END i_d[205]
 PIN i_d[206]
  DIRECTION INPUT ;
  USE SIGNAL ;
  PORT
   LAYER M5 ;
   RECT 93.984 189.996 94.008 190.080 ;
  END
 END i_d[206]
 PIN i_d[207]
  DIRECTION INPUT ;
  USE SIGNAL ;
  PORT
   LAYER M5 ;
   RECT 94.176 189.996 94.200 190.080 ;
  END
 END i_d[207]
 PIN i_d[208]
  DIRECTION INPUT ;
  USE SIGNAL ;
  PORT
   LAYER M5 ;
   RECT 94.368 189.996 94.392 190.080 ;
  END
 END i_d[208]
 PIN i_d[209]
  DIRECTION INPUT ;
  USE SIGNAL ;
  PORT
   LAYER M5 ;
   RECT 94.560 189.996 94.584 190.080 ;
  END
 END i_d[209]
 PIN i_d[210]
  DIRECTION INPUT ;
  USE SIGNAL ;
  PORT
   LAYER M5 ;
   RECT 94.752 189.996 94.776 190.080 ;
  END
 END i_d[210]
 PIN i_d[211]
  DIRECTION INPUT ;
  USE SIGNAL ;
  PORT
   LAYER M5 ;
   RECT 94.944 189.996 94.968 190.080 ;
  END
 END i_d[211]
 PIN i_d[212]
  DIRECTION INPUT ;
  USE SIGNAL ;
  PORT
   LAYER M5 ;
   RECT 95.136 189.996 95.160 190.080 ;
  END
 END i_d[212]
 PIN i_d[213]
  DIRECTION INPUT ;
  USE SIGNAL ;
  PORT
   LAYER M5 ;
   RECT 95.328 189.996 95.352 190.080 ;
  END
 END i_d[213]
 PIN i_d[214]
  DIRECTION INPUT ;
  USE SIGNAL ;
  PORT
   LAYER M5 ;
   RECT 95.520 189.996 95.544 190.080 ;
  END
 END i_d[214]
 PIN i_d[215]
  DIRECTION INPUT ;
  USE SIGNAL ;
  PORT
   LAYER M5 ;
   RECT 95.712 189.996 95.736 190.080 ;
  END
 END i_d[215]
 PIN i_d[216]
  DIRECTION INPUT ;
  USE SIGNAL ;
  PORT
   LAYER M5 ;
   RECT 95.904 189.996 95.928 190.080 ;
  END
 END i_d[216]
 PIN i_d[217]
  DIRECTION INPUT ;
  USE SIGNAL ;
  PORT
   LAYER M5 ;
   RECT 96.096 189.996 96.120 190.080 ;
  END
 END i_d[217]
 PIN i_d[218]
  DIRECTION INPUT ;
  USE SIGNAL ;
  PORT
   LAYER M5 ;
   RECT 96.288 189.996 96.312 190.080 ;
  END
 END i_d[218]
 PIN i_d[219]
  DIRECTION INPUT ;
  USE SIGNAL ;
  PORT
   LAYER M5 ;
   RECT 96.480 189.996 96.504 190.080 ;
  END
 END i_d[219]
 PIN i_d[220]
  DIRECTION INPUT ;
  USE SIGNAL ;
  PORT
   LAYER M5 ;
   RECT 96.672 189.996 96.696 190.080 ;
  END
 END i_d[220]
 PIN i_d[221]
  DIRECTION INPUT ;
  USE SIGNAL ;
  PORT
   LAYER M5 ;
   RECT 96.864 189.996 96.888 190.080 ;
  END
 END i_d[221]
 PIN i_d[222]
  DIRECTION INPUT ;
  USE SIGNAL ;
  PORT
   LAYER M5 ;
   RECT 97.056 189.996 97.080 190.080 ;
  END
 END i_d[222]
 PIN i_d[223]
  DIRECTION INPUT ;
  USE SIGNAL ;
  PORT
   LAYER M5 ;
   RECT 97.248 189.996 97.272 190.080 ;
  END
 END i_d[223]
 PIN i_d[224]
  DIRECTION INPUT ;
  USE SIGNAL ;
  PORT
   LAYER M5 ;
   RECT 97.440 189.996 97.464 190.080 ;
  END
 END i_d[224]
 PIN i_d[225]
  DIRECTION INPUT ;
  USE SIGNAL ;
  PORT
   LAYER M5 ;
   RECT 97.632 189.996 97.656 190.080 ;
  END
 END i_d[225]
 PIN i_d[226]
  DIRECTION INPUT ;
  USE SIGNAL ;
  PORT
   LAYER M5 ;
   RECT 97.824 189.996 97.848 190.080 ;
  END
 END i_d[226]
 PIN i_d[227]
  DIRECTION INPUT ;
  USE SIGNAL ;
  PORT
   LAYER M5 ;
   RECT 98.016 189.996 98.040 190.080 ;
  END
 END i_d[227]
 PIN i_d[228]
  DIRECTION INPUT ;
  USE SIGNAL ;
  PORT
   LAYER M5 ;
   RECT 98.208 189.996 98.232 190.080 ;
  END
 END i_d[228]
 PIN i_d[229]
  DIRECTION INPUT ;
  USE SIGNAL ;
  PORT
   LAYER M5 ;
   RECT 98.400 189.996 98.424 190.080 ;
  END
 END i_d[229]
 PIN i_d[230]
  DIRECTION INPUT ;
  USE SIGNAL ;
  PORT
   LAYER M5 ;
   RECT 98.592 189.996 98.616 190.080 ;
  END
 END i_d[230]
 PIN i_d[231]
  DIRECTION INPUT ;
  USE SIGNAL ;
  PORT
   LAYER M5 ;
   RECT 98.784 189.996 98.808 190.080 ;
  END
 END i_d[231]
 PIN i_d[232]
  DIRECTION INPUT ;
  USE SIGNAL ;
  PORT
   LAYER M5 ;
   RECT 98.976 189.996 99.000 190.080 ;
  END
 END i_d[232]
 PIN i_d[233]
  DIRECTION INPUT ;
  USE SIGNAL ;
  PORT
   LAYER M5 ;
   RECT 99.168 189.996 99.192 190.080 ;
  END
 END i_d[233]
 PIN i_d[234]
  DIRECTION INPUT ;
  USE SIGNAL ;
  PORT
   LAYER M5 ;
   RECT 99.360 189.996 99.384 190.080 ;
  END
 END i_d[234]
 PIN i_d[235]
  DIRECTION INPUT ;
  USE SIGNAL ;
  PORT
   LAYER M5 ;
   RECT 99.552 189.996 99.576 190.080 ;
  END
 END i_d[235]
 PIN i_d[236]
  DIRECTION INPUT ;
  USE SIGNAL ;
  PORT
   LAYER M5 ;
   RECT 99.744 189.996 99.768 190.080 ;
  END
 END i_d[236]
 PIN i_d[237]
  DIRECTION INPUT ;
  USE SIGNAL ;
  PORT
   LAYER M5 ;
   RECT 99.936 189.996 99.960 190.080 ;
  END
 END i_d[237]
 PIN i_d[238]
  DIRECTION INPUT ;
  USE SIGNAL ;
  PORT
   LAYER M5 ;
   RECT 100.128 189.996 100.152 190.080 ;
  END
 END i_d[238]
 PIN i_d[239]
  DIRECTION INPUT ;
  USE SIGNAL ;
  PORT
   LAYER M5 ;
   RECT 100.320 189.996 100.344 190.080 ;
  END
 END i_d[239]
 PIN i_d[240]
  DIRECTION INPUT ;
  USE SIGNAL ;
  PORT
   LAYER M5 ;
   RECT 100.512 189.996 100.536 190.080 ;
  END
 END i_d[240]
 PIN i_d[241]
  DIRECTION INPUT ;
  USE SIGNAL ;
  PORT
   LAYER M5 ;
   RECT 100.704 189.996 100.728 190.080 ;
  END
 END i_d[241]
 PIN i_d[242]
  DIRECTION INPUT ;
  USE SIGNAL ;
  PORT
   LAYER M5 ;
   RECT 100.896 189.996 100.920 190.080 ;
  END
 END i_d[242]
 PIN i_d[243]
  DIRECTION INPUT ;
  USE SIGNAL ;
  PORT
   LAYER M5 ;
   RECT 101.088 189.996 101.112 190.080 ;
  END
 END i_d[243]
 PIN i_d[244]
  DIRECTION INPUT ;
  USE SIGNAL ;
  PORT
   LAYER M5 ;
   RECT 101.280 189.996 101.304 190.080 ;
  END
 END i_d[244]
 PIN i_d[245]
  DIRECTION INPUT ;
  USE SIGNAL ;
  PORT
   LAYER M5 ;
   RECT 101.472 189.996 101.496 190.080 ;
  END
 END i_d[245]
 PIN i_d[246]
  DIRECTION INPUT ;
  USE SIGNAL ;
  PORT
   LAYER M5 ;
   RECT 101.664 189.996 101.688 190.080 ;
  END
 END i_d[246]
 PIN i_d[247]
  DIRECTION INPUT ;
  USE SIGNAL ;
  PORT
   LAYER M5 ;
   RECT 101.856 189.996 101.880 190.080 ;
  END
 END i_d[247]
 PIN i_d[248]
  DIRECTION INPUT ;
  USE SIGNAL ;
  PORT
   LAYER M5 ;
   RECT 102.048 189.996 102.072 190.080 ;
  END
 END i_d[248]
 PIN i_d[249]
  DIRECTION INPUT ;
  USE SIGNAL ;
  PORT
   LAYER M5 ;
   RECT 102.240 189.996 102.264 190.080 ;
  END
 END i_d[249]
 PIN i_d[250]
  DIRECTION INPUT ;
  USE SIGNAL ;
  PORT
   LAYER M5 ;
   RECT 102.432 189.996 102.456 190.080 ;
  END
 END i_d[250]
 PIN i_d[251]
  DIRECTION INPUT ;
  USE SIGNAL ;
  PORT
   LAYER M5 ;
   RECT 102.624 189.996 102.648 190.080 ;
  END
 END i_d[251]
 PIN i_d[252]
  DIRECTION INPUT ;
  USE SIGNAL ;
  PORT
   LAYER M5 ;
   RECT 102.816 189.996 102.840 190.080 ;
  END
 END i_d[252]
 PIN i_d[253]
  DIRECTION INPUT ;
  USE SIGNAL ;
  PORT
   LAYER M5 ;
   RECT 103.008 189.996 103.032 190.080 ;
  END
 END i_d[253]
 PIN i_d[254]
  DIRECTION INPUT ;
  USE SIGNAL ;
  PORT
   LAYER M5 ;
   RECT 103.200 189.996 103.224 190.080 ;
  END
 END i_d[254]
 PIN i_d[255]
  DIRECTION INPUT ;
  USE SIGNAL ;
  PORT
   LAYER M5 ;
   RECT 103.392 189.996 103.416 190.080 ;
  END
 END i_d[255]
 PIN i_d[256]
  DIRECTION INPUT ;
  USE SIGNAL ;
  PORT
   LAYER M5 ;
   RECT 103.584 189.996 103.608 190.080 ;
  END
 END i_d[256]
 PIN i_d[257]
  DIRECTION INPUT ;
  USE SIGNAL ;
  PORT
   LAYER M5 ;
   RECT 103.776 189.996 103.800 190.080 ;
  END
 END i_d[257]
 PIN i_d[258]
  DIRECTION INPUT ;
  USE SIGNAL ;
  PORT
   LAYER M5 ;
   RECT 103.968 189.996 103.992 190.080 ;
  END
 END i_d[258]
 PIN i_d[259]
  DIRECTION INPUT ;
  USE SIGNAL ;
  PORT
   LAYER M5 ;
   RECT 104.160 189.996 104.184 190.080 ;
  END
 END i_d[259]
 PIN i_d[260]
  DIRECTION INPUT ;
  USE SIGNAL ;
  PORT
   LAYER M5 ;
   RECT 104.352 189.996 104.376 190.080 ;
  END
 END i_d[260]
 PIN i_d[261]
  DIRECTION INPUT ;
  USE SIGNAL ;
  PORT
   LAYER M5 ;
   RECT 104.544 189.996 104.568 190.080 ;
  END
 END i_d[261]
 PIN i_d[262]
  DIRECTION INPUT ;
  USE SIGNAL ;
  PORT
   LAYER M5 ;
   RECT 104.736 189.996 104.760 190.080 ;
  END
 END i_d[262]
 PIN i_d[263]
  DIRECTION INPUT ;
  USE SIGNAL ;
  PORT
   LAYER M5 ;
   RECT 104.928 189.996 104.952 190.080 ;
  END
 END i_d[263]
 PIN i_d[264]
  DIRECTION INPUT ;
  USE SIGNAL ;
  PORT
   LAYER M5 ;
   RECT 105.120 189.996 105.144 190.080 ;
  END
 END i_d[264]
 PIN i_d[265]
  DIRECTION INPUT ;
  USE SIGNAL ;
  PORT
   LAYER M5 ;
   RECT 105.312 189.996 105.336 190.080 ;
  END
 END i_d[265]
 PIN i_d[266]
  DIRECTION INPUT ;
  USE SIGNAL ;
  PORT
   LAYER M5 ;
   RECT 105.504 189.996 105.528 190.080 ;
  END
 END i_d[266]
 PIN i_d[267]
  DIRECTION INPUT ;
  USE SIGNAL ;
  PORT
   LAYER M5 ;
   RECT 105.696 189.996 105.720 190.080 ;
  END
 END i_d[267]
 PIN i_d[268]
  DIRECTION INPUT ;
  USE SIGNAL ;
  PORT
   LAYER M5 ;
   RECT 105.888 189.996 105.912 190.080 ;
  END
 END i_d[268]
 PIN i_d[269]
  DIRECTION INPUT ;
  USE SIGNAL ;
  PORT
   LAYER M5 ;
   RECT 110.112 189.996 110.136 190.080 ;
  END
 END i_d[269]
 PIN i_d[270]
  DIRECTION INPUT ;
  USE SIGNAL ;
  PORT
   LAYER M5 ;
   RECT 110.304 189.996 110.328 190.080 ;
  END
 END i_d[270]
 PIN i_d[271]
  DIRECTION INPUT ;
  USE SIGNAL ;
  PORT
   LAYER M5 ;
   RECT 110.496 189.996 110.520 190.080 ;
  END
 END i_d[271]
 PIN i_d[272]
  DIRECTION INPUT ;
  USE SIGNAL ;
  PORT
   LAYER M5 ;
   RECT 110.688 189.996 110.712 190.080 ;
  END
 END i_d[272]
 PIN i_d[273]
  DIRECTION INPUT ;
  USE SIGNAL ;
  PORT
   LAYER M5 ;
   RECT 110.880 189.996 110.904 190.080 ;
  END
 END i_d[273]
 PIN i_d[274]
  DIRECTION INPUT ;
  USE SIGNAL ;
  PORT
   LAYER M5 ;
   RECT 111.072 189.996 111.096 190.080 ;
  END
 END i_d[274]
 PIN i_d[275]
  DIRECTION INPUT ;
  USE SIGNAL ;
  PORT
   LAYER M5 ;
   RECT 111.264 189.996 111.288 190.080 ;
  END
 END i_d[275]
 PIN i_d[276]
  DIRECTION INPUT ;
  USE SIGNAL ;
  PORT
   LAYER M5 ;
   RECT 111.456 189.996 111.480 190.080 ;
  END
 END i_d[276]
 PIN i_d[277]
  DIRECTION INPUT ;
  USE SIGNAL ;
  PORT
   LAYER M5 ;
   RECT 111.648 189.996 111.672 190.080 ;
  END
 END i_d[277]
 PIN i_d[278]
  DIRECTION INPUT ;
  USE SIGNAL ;
  PORT
   LAYER M5 ;
   RECT 111.840 189.996 111.864 190.080 ;
  END
 END i_d[278]
 PIN i_d[279]
  DIRECTION INPUT ;
  USE SIGNAL ;
  PORT
   LAYER M5 ;
   RECT 112.032 189.996 112.056 190.080 ;
  END
 END i_d[279]
 PIN i_d[280]
  DIRECTION INPUT ;
  USE SIGNAL ;
  PORT
   LAYER M5 ;
   RECT 112.224 189.996 112.248 190.080 ;
  END
 END i_d[280]
 PIN i_d[281]
  DIRECTION INPUT ;
  USE SIGNAL ;
  PORT
   LAYER M5 ;
   RECT 112.416 189.996 112.440 190.080 ;
  END
 END i_d[281]
 PIN i_d[282]
  DIRECTION INPUT ;
  USE SIGNAL ;
  PORT
   LAYER M5 ;
   RECT 112.608 189.996 112.632 190.080 ;
  END
 END i_d[282]
 PIN i_d[283]
  DIRECTION INPUT ;
  USE SIGNAL ;
  PORT
   LAYER M5 ;
   RECT 112.800 189.996 112.824 190.080 ;
  END
 END i_d[283]
 PIN i_d[284]
  DIRECTION INPUT ;
  USE SIGNAL ;
  PORT
   LAYER M5 ;
   RECT 112.992 189.996 113.016 190.080 ;
  END
 END i_d[284]
 PIN i_d[285]
  DIRECTION INPUT ;
  USE SIGNAL ;
  PORT
   LAYER M5 ;
   RECT 113.184 189.996 113.208 190.080 ;
  END
 END i_d[285]
 PIN i_d[286]
  DIRECTION INPUT ;
  USE SIGNAL ;
  PORT
   LAYER M5 ;
   RECT 113.376 189.996 113.400 190.080 ;
  END
 END i_d[286]
 PIN i_d[287]
  DIRECTION INPUT ;
  USE SIGNAL ;
  PORT
   LAYER M5 ;
   RECT 113.568 189.996 113.592 190.080 ;
  END
 END i_d[287]
 PIN i_d[288]
  DIRECTION INPUT ;
  USE SIGNAL ;
  PORT
   LAYER M5 ;
   RECT 113.760 189.996 113.784 190.080 ;
  END
 END i_d[288]
 PIN i_d[289]
  DIRECTION INPUT ;
  USE SIGNAL ;
  PORT
   LAYER M5 ;
   RECT 113.952 189.996 113.976 190.080 ;
  END
 END i_d[289]
 PIN i_d[290]
  DIRECTION INPUT ;
  USE SIGNAL ;
  PORT
   LAYER M5 ;
   RECT 114.144 189.996 114.168 190.080 ;
  END
 END i_d[290]
 PIN i_d[291]
  DIRECTION INPUT ;
  USE SIGNAL ;
  PORT
   LAYER M5 ;
   RECT 114.336 189.996 114.360 190.080 ;
  END
 END i_d[291]
 PIN i_d[292]
  DIRECTION INPUT ;
  USE SIGNAL ;
  PORT
   LAYER M5 ;
   RECT 114.528 189.996 114.552 190.080 ;
  END
 END i_d[292]
 PIN i_d[293]
  DIRECTION INPUT ;
  USE SIGNAL ;
  PORT
   LAYER M5 ;
   RECT 114.720 189.996 114.744 190.080 ;
  END
 END i_d[293]
 PIN i_d[294]
  DIRECTION INPUT ;
  USE SIGNAL ;
  PORT
   LAYER M5 ;
   RECT 114.912 189.996 114.936 190.080 ;
  END
 END i_d[294]
 PIN i_d[295]
  DIRECTION INPUT ;
  USE SIGNAL ;
  PORT
   LAYER M5 ;
   RECT 115.104 189.996 115.128 190.080 ;
  END
 END i_d[295]
 PIN i_d[296]
  DIRECTION INPUT ;
  USE SIGNAL ;
  PORT
   LAYER M5 ;
   RECT 115.296 189.996 115.320 190.080 ;
  END
 END i_d[296]
 PIN i_d[297]
  DIRECTION INPUT ;
  USE SIGNAL ;
  PORT
   LAYER M5 ;
   RECT 115.488 189.996 115.512 190.080 ;
  END
 END i_d[297]
 PIN i_d[298]
  DIRECTION INPUT ;
  USE SIGNAL ;
  PORT
   LAYER M5 ;
   RECT 115.680 189.996 115.704 190.080 ;
  END
 END i_d[298]
 PIN i_d[299]
  DIRECTION INPUT ;
  USE SIGNAL ;
  PORT
   LAYER M5 ;
   RECT 115.872 189.996 115.896 190.080 ;
  END
 END i_d[299]
 PIN i_d[300]
  DIRECTION INPUT ;
  USE SIGNAL ;
  PORT
   LAYER M5 ;
   RECT 116.064 189.996 116.088 190.080 ;
  END
 END i_d[300]
 PIN i_d[301]
  DIRECTION INPUT ;
  USE SIGNAL ;
  PORT
   LAYER M5 ;
   RECT 116.256 189.996 116.280 190.080 ;
  END
 END i_d[301]
 PIN i_d[302]
  DIRECTION INPUT ;
  USE SIGNAL ;
  PORT
   LAYER M5 ;
   RECT 116.448 189.996 116.472 190.080 ;
  END
 END i_d[302]
 PIN i_d[303]
  DIRECTION INPUT ;
  USE SIGNAL ;
  PORT
   LAYER M5 ;
   RECT 116.640 189.996 116.664 190.080 ;
  END
 END i_d[303]
 PIN i_d[304]
  DIRECTION INPUT ;
  USE SIGNAL ;
  PORT
   LAYER M5 ;
   RECT 116.832 189.996 116.856 190.080 ;
  END
 END i_d[304]
 PIN i_d[305]
  DIRECTION INPUT ;
  USE SIGNAL ;
  PORT
   LAYER M5 ;
   RECT 117.024 189.996 117.048 190.080 ;
  END
 END i_d[305]
 PIN i_d[306]
  DIRECTION INPUT ;
  USE SIGNAL ;
  PORT
   LAYER M5 ;
   RECT 117.216 189.996 117.240 190.080 ;
  END
 END i_d[306]
 PIN i_d[307]
  DIRECTION INPUT ;
  USE SIGNAL ;
  PORT
   LAYER M5 ;
   RECT 117.408 189.996 117.432 190.080 ;
  END
 END i_d[307]
 PIN i_d[308]
  DIRECTION INPUT ;
  USE SIGNAL ;
  PORT
   LAYER M5 ;
   RECT 117.600 189.996 117.624 190.080 ;
  END
 END i_d[308]
 PIN i_d[309]
  DIRECTION INPUT ;
  USE SIGNAL ;
  PORT
   LAYER M5 ;
   RECT 117.792 189.996 117.816 190.080 ;
  END
 END i_d[309]
 PIN i_d[310]
  DIRECTION INPUT ;
  USE SIGNAL ;
  PORT
   LAYER M5 ;
   RECT 117.984 189.996 118.008 190.080 ;
  END
 END i_d[310]
 PIN i_d[311]
  DIRECTION INPUT ;
  USE SIGNAL ;
  PORT
   LAYER M5 ;
   RECT 118.176 189.996 118.200 190.080 ;
  END
 END i_d[311]
 PIN i_d[312]
  DIRECTION INPUT ;
  USE SIGNAL ;
  PORT
   LAYER M5 ;
   RECT 118.368 189.996 118.392 190.080 ;
  END
 END i_d[312]
 PIN i_d[313]
  DIRECTION INPUT ;
  USE SIGNAL ;
  PORT
   LAYER M5 ;
   RECT 118.560 189.996 118.584 190.080 ;
  END
 END i_d[313]
 PIN i_d[314]
  DIRECTION INPUT ;
  USE SIGNAL ;
  PORT
   LAYER M5 ;
   RECT 118.752 189.996 118.776 190.080 ;
  END
 END i_d[314]
 PIN i_d[315]
  DIRECTION INPUT ;
  USE SIGNAL ;
  PORT
   LAYER M5 ;
   RECT 118.944 189.996 118.968 190.080 ;
  END
 END i_d[315]
 PIN i_d[316]
  DIRECTION INPUT ;
  USE SIGNAL ;
  PORT
   LAYER M5 ;
   RECT 119.136 189.996 119.160 190.080 ;
  END
 END i_d[316]
 PIN i_d[317]
  DIRECTION INPUT ;
  USE SIGNAL ;
  PORT
   LAYER M5 ;
   RECT 119.328 189.996 119.352 190.080 ;
  END
 END i_d[317]
 PIN i_d[318]
  DIRECTION INPUT ;
  USE SIGNAL ;
  PORT
   LAYER M5 ;
   RECT 119.520 189.996 119.544 190.080 ;
  END
 END i_d[318]
 PIN i_d[319]
  DIRECTION INPUT ;
  USE SIGNAL ;
  PORT
   LAYER M5 ;
   RECT 119.712 189.996 119.736 190.080 ;
  END
 END i_d[319]
 PIN i_d[320]
  DIRECTION INPUT ;
  USE SIGNAL ;
  PORT
   LAYER M5 ;
   RECT 119.904 189.996 119.928 190.080 ;
  END
 END i_d[320]
 PIN i_d[321]
  DIRECTION INPUT ;
  USE SIGNAL ;
  PORT
   LAYER M5 ;
   RECT 120.096 189.996 120.120 190.080 ;
  END
 END i_d[321]
 PIN i_d[322]
  DIRECTION INPUT ;
  USE SIGNAL ;
  PORT
   LAYER M5 ;
   RECT 120.288 189.996 120.312 190.080 ;
  END
 END i_d[322]
 PIN i_d[323]
  DIRECTION INPUT ;
  USE SIGNAL ;
  PORT
   LAYER M5 ;
   RECT 120.480 189.996 120.504 190.080 ;
  END
 END i_d[323]
 PIN i_d[324]
  DIRECTION INPUT ;
  USE SIGNAL ;
  PORT
   LAYER M5 ;
   RECT 120.672 189.996 120.696 190.080 ;
  END
 END i_d[324]
 PIN i_d[325]
  DIRECTION INPUT ;
  USE SIGNAL ;
  PORT
   LAYER M5 ;
   RECT 120.864 189.996 120.888 190.080 ;
  END
 END i_d[325]
 PIN i_d[326]
  DIRECTION INPUT ;
  USE SIGNAL ;
  PORT
   LAYER M5 ;
   RECT 121.056 189.996 121.080 190.080 ;
  END
 END i_d[326]
 PIN i_d[327]
  DIRECTION INPUT ;
  USE SIGNAL ;
  PORT
   LAYER M5 ;
   RECT 121.248 189.996 121.272 190.080 ;
  END
 END i_d[327]
 PIN i_d[328]
  DIRECTION INPUT ;
  USE SIGNAL ;
  PORT
   LAYER M5 ;
   RECT 121.440 189.996 121.464 190.080 ;
  END
 END i_d[328]
 PIN i_d[329]
  DIRECTION INPUT ;
  USE SIGNAL ;
  PORT
   LAYER M5 ;
   RECT 121.632 189.996 121.656 190.080 ;
  END
 END i_d[329]
 PIN i_d[330]
  DIRECTION INPUT ;
  USE SIGNAL ;
  PORT
   LAYER M5 ;
   RECT 121.824 189.996 121.848 190.080 ;
  END
 END i_d[330]
 PIN i_d[331]
  DIRECTION INPUT ;
  USE SIGNAL ;
  PORT
   LAYER M5 ;
   RECT 122.016 189.996 122.040 190.080 ;
  END
 END i_d[331]
 PIN i_d[332]
  DIRECTION INPUT ;
  USE SIGNAL ;
  PORT
   LAYER M5 ;
   RECT 122.208 189.996 122.232 190.080 ;
  END
 END i_d[332]
 PIN i_d[333]
  DIRECTION INPUT ;
  USE SIGNAL ;
  PORT
   LAYER M5 ;
   RECT 122.400 189.996 122.424 190.080 ;
  END
 END i_d[333]
 PIN i_d[334]
  DIRECTION INPUT ;
  USE SIGNAL ;
  PORT
   LAYER M5 ;
   RECT 122.592 189.996 122.616 190.080 ;
  END
 END i_d[334]
 PIN i_d[335]
  DIRECTION INPUT ;
  USE SIGNAL ;
  PORT
   LAYER M5 ;
   RECT 122.784 189.996 122.808 190.080 ;
  END
 END i_d[335]
 PIN i_d[336]
  DIRECTION INPUT ;
  USE SIGNAL ;
  PORT
   LAYER M5 ;
   RECT 122.976 189.996 123.000 190.080 ;
  END
 END i_d[336]
 PIN i_d[337]
  DIRECTION INPUT ;
  USE SIGNAL ;
  PORT
   LAYER M5 ;
   RECT 123.168 189.996 123.192 190.080 ;
  END
 END i_d[337]
 PIN i_d[338]
  DIRECTION INPUT ;
  USE SIGNAL ;
  PORT
   LAYER M5 ;
   RECT 123.360 189.996 123.384 190.080 ;
  END
 END i_d[338]
 PIN i_d[339]
  DIRECTION INPUT ;
  USE SIGNAL ;
  PORT
   LAYER M5 ;
   RECT 123.552 189.996 123.576 190.080 ;
  END
 END i_d[339]
 PIN i_d[340]
  DIRECTION INPUT ;
  USE SIGNAL ;
  PORT
   LAYER M5 ;
   RECT 123.744 189.996 123.768 190.080 ;
  END
 END i_d[340]
 PIN i_d[341]
  DIRECTION INPUT ;
  USE SIGNAL ;
  PORT
   LAYER M5 ;
   RECT 123.936 189.996 123.960 190.080 ;
  END
 END i_d[341]
 PIN i_d[342]
  DIRECTION INPUT ;
  USE SIGNAL ;
  PORT
   LAYER M5 ;
   RECT 124.128 189.996 124.152 190.080 ;
  END
 END i_d[342]
 PIN i_d[343]
  DIRECTION INPUT ;
  USE SIGNAL ;
  PORT
   LAYER M5 ;
   RECT 124.320 189.996 124.344 190.080 ;
  END
 END i_d[343]
 PIN i_d[344]
  DIRECTION INPUT ;
  USE SIGNAL ;
  PORT
   LAYER M5 ;
   RECT 124.512 189.996 124.536 190.080 ;
  END
 END i_d[344]
 PIN i_d[345]
  DIRECTION INPUT ;
  USE SIGNAL ;
  PORT
   LAYER M5 ;
   RECT 124.704 189.996 124.728 190.080 ;
  END
 END i_d[345]
 PIN i_d[346]
  DIRECTION INPUT ;
  USE SIGNAL ;
  PORT
   LAYER M5 ;
   RECT 124.896 189.996 124.920 190.080 ;
  END
 END i_d[346]
 PIN i_d[347]
  DIRECTION INPUT ;
  USE SIGNAL ;
  PORT
   LAYER M5 ;
   RECT 125.088 189.996 125.112 190.080 ;
  END
 END i_d[347]
 PIN i_d[348]
  DIRECTION INPUT ;
  USE SIGNAL ;
  PORT
   LAYER M5 ;
   RECT 125.280 189.996 125.304 190.080 ;
  END
 END i_d[348]
 PIN i_d[349]
  DIRECTION INPUT ;
  USE SIGNAL ;
  PORT
   LAYER M5 ;
   RECT 125.472 189.996 125.496 190.080 ;
  END
 END i_d[349]
 PIN i_d[350]
  DIRECTION INPUT ;
  USE SIGNAL ;
  PORT
   LAYER M5 ;
   RECT 125.664 189.996 125.688 190.080 ;
  END
 END i_d[350]
 PIN i_d[351]
  DIRECTION INPUT ;
  USE SIGNAL ;
  PORT
   LAYER M5 ;
   RECT 125.856 189.996 125.880 190.080 ;
  END
 END i_d[351]
 PIN i_d[352]
  DIRECTION INPUT ;
  USE SIGNAL ;
  PORT
   LAYER M5 ;
   RECT 126.048 189.996 126.072 190.080 ;
  END
 END i_d[352]
 PIN i_d[353]
  DIRECTION INPUT ;
  USE SIGNAL ;
  PORT
   LAYER M5 ;
   RECT 126.240 189.996 126.264 190.080 ;
  END
 END i_d[353]
 PIN i_d[354]
  DIRECTION INPUT ;
  USE SIGNAL ;
  PORT
   LAYER M5 ;
   RECT 126.432 189.996 126.456 190.080 ;
  END
 END i_d[354]
 PIN i_d[355]
  DIRECTION INPUT ;
  USE SIGNAL ;
  PORT
   LAYER M5 ;
   RECT 126.624 189.996 126.648 190.080 ;
  END
 END i_d[355]
 PIN i_d[356]
  DIRECTION INPUT ;
  USE SIGNAL ;
  PORT
   LAYER M5 ;
   RECT 126.816 189.996 126.840 190.080 ;
  END
 END i_d[356]
 PIN i_d[357]
  DIRECTION INPUT ;
  USE SIGNAL ;
  PORT
   LAYER M5 ;
   RECT 127.008 189.996 127.032 190.080 ;
  END
 END i_d[357]
 PIN i_d[358]
  DIRECTION INPUT ;
  USE SIGNAL ;
  PORT
   LAYER M5 ;
   RECT 127.200 189.996 127.224 190.080 ;
  END
 END i_d[358]
 PIN i_d[359]
  DIRECTION INPUT ;
  USE SIGNAL ;
  PORT
   LAYER M5 ;
   RECT 127.392 189.996 127.416 190.080 ;
  END
 END i_d[359]
 PIN i_d[360]
  DIRECTION INPUT ;
  USE SIGNAL ;
  PORT
   LAYER M5 ;
   RECT 127.584 189.996 127.608 190.080 ;
  END
 END i_d[360]
 PIN i_d[361]
  DIRECTION INPUT ;
  USE SIGNAL ;
  PORT
   LAYER M5 ;
   RECT 127.776 189.996 127.800 190.080 ;
  END
 END i_d[361]
 PIN i_d[362]
  DIRECTION INPUT ;
  USE SIGNAL ;
  PORT
   LAYER M5 ;
   RECT 127.968 189.996 127.992 190.080 ;
  END
 END i_d[362]
 PIN i_d[363]
  DIRECTION INPUT ;
  USE SIGNAL ;
  PORT
   LAYER M5 ;
   RECT 128.160 189.996 128.184 190.080 ;
  END
 END i_d[363]
 PIN i_d[364]
  DIRECTION INPUT ;
  USE SIGNAL ;
  PORT
   LAYER M5 ;
   RECT 128.352 189.996 128.376 190.080 ;
  END
 END i_d[364]
 PIN i_d[365]
  DIRECTION INPUT ;
  USE SIGNAL ;
  PORT
   LAYER M5 ;
   RECT 128.544 189.996 128.568 190.080 ;
  END
 END i_d[365]
 PIN i_d[366]
  DIRECTION INPUT ;
  USE SIGNAL ;
  PORT
   LAYER M5 ;
   RECT 128.736 189.996 128.760 190.080 ;
  END
 END i_d[366]
 PIN i_d[367]
  DIRECTION INPUT ;
  USE SIGNAL ;
  PORT
   LAYER M5 ;
   RECT 128.928 189.996 128.952 190.080 ;
  END
 END i_d[367]
 PIN i_d[368]
  DIRECTION INPUT ;
  USE SIGNAL ;
  PORT
   LAYER M5 ;
   RECT 129.120 189.996 129.144 190.080 ;
  END
 END i_d[368]
 PIN i_d[369]
  DIRECTION INPUT ;
  USE SIGNAL ;
  PORT
   LAYER M5 ;
   RECT 129.312 189.996 129.336 190.080 ;
  END
 END i_d[369]
 PIN i_d[370]
  DIRECTION INPUT ;
  USE SIGNAL ;
  PORT
   LAYER M5 ;
   RECT 129.504 189.996 129.528 190.080 ;
  END
 END i_d[370]
 PIN i_d[371]
  DIRECTION INPUT ;
  USE SIGNAL ;
  PORT
   LAYER M5 ;
   RECT 129.696 189.996 129.720 190.080 ;
  END
 END i_d[371]
 PIN i_d[372]
  DIRECTION INPUT ;
  USE SIGNAL ;
  PORT
   LAYER M5 ;
   RECT 129.888 189.996 129.912 190.080 ;
  END
 END i_d[372]
 PIN i_d[373]
  DIRECTION INPUT ;
  USE SIGNAL ;
  PORT
   LAYER M5 ;
   RECT 130.080 189.996 130.104 190.080 ;
  END
 END i_d[373]
 PIN i_d[374]
  DIRECTION INPUT ;
  USE SIGNAL ;
  PORT
   LAYER M5 ;
   RECT 130.272 189.996 130.296 190.080 ;
  END
 END i_d[374]
 PIN i_d[375]
  DIRECTION INPUT ;
  USE SIGNAL ;
  PORT
   LAYER M5 ;
   RECT 130.464 189.996 130.488 190.080 ;
  END
 END i_d[375]
 PIN i_d[376]
  DIRECTION INPUT ;
  USE SIGNAL ;
  PORT
   LAYER M5 ;
   RECT 130.656 189.996 130.680 190.080 ;
  END
 END i_d[376]
 PIN i_d[377]
  DIRECTION INPUT ;
  USE SIGNAL ;
  PORT
   LAYER M5 ;
   RECT 130.848 189.996 130.872 190.080 ;
  END
 END i_d[377]
 PIN i_d[378]
  DIRECTION INPUT ;
  USE SIGNAL ;
  PORT
   LAYER M5 ;
   RECT 131.040 189.996 131.064 190.080 ;
  END
 END i_d[378]
 PIN i_d[379]
  DIRECTION INPUT ;
  USE SIGNAL ;
  PORT
   LAYER M5 ;
   RECT 131.232 189.996 131.256 190.080 ;
  END
 END i_d[379]
 PIN i_d[380]
  DIRECTION INPUT ;
  USE SIGNAL ;
  PORT
   LAYER M5 ;
   RECT 131.424 189.996 131.448 190.080 ;
  END
 END i_d[380]
 PIN i_d[381]
  DIRECTION INPUT ;
  USE SIGNAL ;
  PORT
   LAYER M5 ;
   RECT 131.616 189.996 131.640 190.080 ;
  END
 END i_d[381]
 PIN i_d[382]
  DIRECTION INPUT ;
  USE SIGNAL ;
  PORT
   LAYER M5 ;
   RECT 131.808 189.996 131.832 190.080 ;
  END
 END i_d[382]
 PIN i_d[383]
  DIRECTION INPUT ;
  USE SIGNAL ;
  PORT
   LAYER M5 ;
   RECT 132.000 189.996 132.024 190.080 ;
  END
 END i_d[383]
 PIN i_d[384]
  DIRECTION INPUT ;
  USE SIGNAL ;
  PORT
   LAYER M5 ;
   RECT 132.192 189.996 132.216 190.080 ;
  END
 END i_d[384]
 PIN i_d[385]
  DIRECTION INPUT ;
  USE SIGNAL ;
  PORT
   LAYER M5 ;
   RECT 132.384 189.996 132.408 190.080 ;
  END
 END i_d[385]
 PIN i_d[386]
  DIRECTION INPUT ;
  USE SIGNAL ;
  PORT
   LAYER M5 ;
   RECT 132.576 189.996 132.600 190.080 ;
  END
 END i_d[386]
 PIN i_d[387]
  DIRECTION INPUT ;
  USE SIGNAL ;
  PORT
   LAYER M5 ;
   RECT 132.768 189.996 132.792 190.080 ;
  END
 END i_d[387]
 PIN i_d[388]
  DIRECTION INPUT ;
  USE SIGNAL ;
  PORT
   LAYER M5 ;
   RECT 132.960 189.996 132.984 190.080 ;
  END
 END i_d[388]
 PIN i_d[389]
  DIRECTION INPUT ;
  USE SIGNAL ;
  PORT
   LAYER M5 ;
   RECT 133.152 189.996 133.176 190.080 ;
  END
 END i_d[389]
 PIN i_d[390]
  DIRECTION INPUT ;
  USE SIGNAL ;
  PORT
   LAYER M5 ;
   RECT 133.344 189.996 133.368 190.080 ;
  END
 END i_d[390]
 PIN i_d[391]
  DIRECTION INPUT ;
  USE SIGNAL ;
  PORT
   LAYER M5 ;
   RECT 133.536 189.996 133.560 190.080 ;
  END
 END i_d[391]
 PIN i_d[392]
  DIRECTION INPUT ;
  USE SIGNAL ;
  PORT
   LAYER M5 ;
   RECT 133.728 189.996 133.752 190.080 ;
  END
 END i_d[392]
 PIN i_d[393]
  DIRECTION INPUT ;
  USE SIGNAL ;
  PORT
   LAYER M5 ;
   RECT 133.920 189.996 133.944 190.080 ;
  END
 END i_d[393]
 PIN i_d[394]
  DIRECTION INPUT ;
  USE SIGNAL ;
  PORT
   LAYER M5 ;
   RECT 134.112 189.996 134.136 190.080 ;
  END
 END i_d[394]
 PIN i_d[395]
  DIRECTION INPUT ;
  USE SIGNAL ;
  PORT
   LAYER M5 ;
   RECT 134.304 189.996 134.328 190.080 ;
  END
 END i_d[395]
 PIN i_d[396]
  DIRECTION INPUT ;
  USE SIGNAL ;
  PORT
   LAYER M5 ;
   RECT 134.496 189.996 134.520 190.080 ;
  END
 END i_d[396]
 PIN i_d[397]
  DIRECTION INPUT ;
  USE SIGNAL ;
  PORT
   LAYER M5 ;
   RECT 134.688 189.996 134.712 190.080 ;
  END
 END i_d[397]
 PIN i_d[398]
  DIRECTION INPUT ;
  USE SIGNAL ;
  PORT
   LAYER M5 ;
   RECT 134.880 189.996 134.904 190.080 ;
  END
 END i_d[398]
 PIN i_d[399]
  DIRECTION INPUT ;
  USE SIGNAL ;
  PORT
   LAYER M5 ;
   RECT 135.072 189.996 135.096 190.080 ;
  END
 END i_d[399]
 PIN i_d[400]
  DIRECTION INPUT ;
  USE SIGNAL ;
  PORT
   LAYER M5 ;
   RECT 135.264 189.996 135.288 190.080 ;
  END
 END i_d[400]
 PIN i_d[401]
  DIRECTION INPUT ;
  USE SIGNAL ;
  PORT
   LAYER M5 ;
   RECT 135.456 189.996 135.480 190.080 ;
  END
 END i_d[401]
 PIN i_d[402]
  DIRECTION INPUT ;
  USE SIGNAL ;
  PORT
   LAYER M5 ;
   RECT 135.648 189.996 135.672 190.080 ;
  END
 END i_d[402]
 PIN i_d[403]
  DIRECTION INPUT ;
  USE SIGNAL ;
  PORT
   LAYER M5 ;
   RECT 135.840 189.996 135.864 190.080 ;
  END
 END i_d[403]
 PIN i_d[404]
  DIRECTION INPUT ;
  USE SIGNAL ;
  PORT
   LAYER M5 ;
   RECT 136.032 189.996 136.056 190.080 ;
  END
 END i_d[404]
 PIN i_d[405]
  DIRECTION INPUT ;
  USE SIGNAL ;
  PORT
   LAYER M5 ;
   RECT 136.224 189.996 136.248 190.080 ;
  END
 END i_d[405]
 PIN i_d[406]
  DIRECTION INPUT ;
  USE SIGNAL ;
  PORT
   LAYER M5 ;
   RECT 136.416 189.996 136.440 190.080 ;
  END
 END i_d[406]
 PIN i_d[407]
  DIRECTION INPUT ;
  USE SIGNAL ;
  PORT
   LAYER M5 ;
   RECT 136.608 189.996 136.632 190.080 ;
  END
 END i_d[407]
 PIN i_d[408]
  DIRECTION INPUT ;
  USE SIGNAL ;
  PORT
   LAYER M5 ;
   RECT 136.800 189.996 136.824 190.080 ;
  END
 END i_d[408]
 PIN i_d[409]
  DIRECTION INPUT ;
  USE SIGNAL ;
  PORT
   LAYER M5 ;
   RECT 136.992 189.996 137.016 190.080 ;
  END
 END i_d[409]
 PIN i_d[410]
  DIRECTION INPUT ;
  USE SIGNAL ;
  PORT
   LAYER M5 ;
   RECT 137.184 189.996 137.208 190.080 ;
  END
 END i_d[410]
 PIN i_d[411]
  DIRECTION INPUT ;
  USE SIGNAL ;
  PORT
   LAYER M5 ;
   RECT 137.376 189.996 137.400 190.080 ;
  END
 END i_d[411]
 PIN i_d[412]
  DIRECTION INPUT ;
  USE SIGNAL ;
  PORT
   LAYER M5 ;
   RECT 137.568 189.996 137.592 190.080 ;
  END
 END i_d[412]
 PIN i_d[413]
  DIRECTION INPUT ;
  USE SIGNAL ;
  PORT
   LAYER M5 ;
   RECT 137.760 189.996 137.784 190.080 ;
  END
 END i_d[413]
 PIN i_d[414]
  DIRECTION INPUT ;
  USE SIGNAL ;
  PORT
   LAYER M5 ;
   RECT 137.952 189.996 137.976 190.080 ;
  END
 END i_d[414]
 PIN i_d[415]
  DIRECTION INPUT ;
  USE SIGNAL ;
  PORT
   LAYER M5 ;
   RECT 138.144 189.996 138.168 190.080 ;
  END
 END i_d[415]
 PIN i_d[416]
  DIRECTION INPUT ;
  USE SIGNAL ;
  PORT
   LAYER M5 ;
   RECT 138.336 189.996 138.360 190.080 ;
  END
 END i_d[416]
 PIN i_d[417]
  DIRECTION INPUT ;
  USE SIGNAL ;
  PORT
   LAYER M5 ;
   RECT 138.528 189.996 138.552 190.080 ;
  END
 END i_d[417]
 PIN i_d[418]
  DIRECTION INPUT ;
  USE SIGNAL ;
  PORT
   LAYER M5 ;
   RECT 138.720 189.996 138.744 190.080 ;
  END
 END i_d[418]
 PIN i_d[419]
  DIRECTION INPUT ;
  USE SIGNAL ;
  PORT
   LAYER M5 ;
   RECT 138.912 189.996 138.936 190.080 ;
  END
 END i_d[419]
 PIN i_d[420]
  DIRECTION INPUT ;
  USE SIGNAL ;
  PORT
   LAYER M5 ;
   RECT 139.104 189.996 139.128 190.080 ;
  END
 END i_d[420]
 PIN i_d[421]
  DIRECTION INPUT ;
  USE SIGNAL ;
  PORT
   LAYER M5 ;
   RECT 139.296 189.996 139.320 190.080 ;
  END
 END i_d[421]
 PIN i_d[422]
  DIRECTION INPUT ;
  USE SIGNAL ;
  PORT
   LAYER M5 ;
   RECT 139.488 189.996 139.512 190.080 ;
  END
 END i_d[422]
 PIN i_d[423]
  DIRECTION INPUT ;
  USE SIGNAL ;
  PORT
   LAYER M5 ;
   RECT 139.680 189.996 139.704 190.080 ;
  END
 END i_d[423]
 PIN i_d[424]
  DIRECTION INPUT ;
  USE SIGNAL ;
  PORT
   LAYER M5 ;
   RECT 139.872 189.996 139.896 190.080 ;
  END
 END i_d[424]
 PIN i_d[425]
  DIRECTION INPUT ;
  USE SIGNAL ;
  PORT
   LAYER M5 ;
   RECT 140.064 189.996 140.088 190.080 ;
  END
 END i_d[425]
 PIN i_d[426]
  DIRECTION INPUT ;
  USE SIGNAL ;
  PORT
   LAYER M5 ;
   RECT 140.256 189.996 140.280 190.080 ;
  END
 END i_d[426]
 PIN i_d[427]
  DIRECTION INPUT ;
  USE SIGNAL ;
  PORT
   LAYER M5 ;
   RECT 140.448 189.996 140.472 190.080 ;
  END
 END i_d[427]
 PIN i_d[428]
  DIRECTION INPUT ;
  USE SIGNAL ;
  PORT
   LAYER M5 ;
   RECT 140.640 189.996 140.664 190.080 ;
  END
 END i_d[428]
 PIN i_d[429]
  DIRECTION INPUT ;
  USE SIGNAL ;
  PORT
   LAYER M5 ;
   RECT 140.832 189.996 140.856 190.080 ;
  END
 END i_d[429]
 PIN i_d[430]
  DIRECTION INPUT ;
  USE SIGNAL ;
  PORT
   LAYER M5 ;
   RECT 141.024 189.996 141.048 190.080 ;
  END
 END i_d[430]
 PIN i_d[431]
  DIRECTION INPUT ;
  USE SIGNAL ;
  PORT
   LAYER M5 ;
   RECT 141.216 189.996 141.240 190.080 ;
  END
 END i_d[431]
 PIN i_d[432]
  DIRECTION INPUT ;
  USE SIGNAL ;
  PORT
   LAYER M5 ;
   RECT 141.408 189.996 141.432 190.080 ;
  END
 END i_d[432]
 PIN i_d[433]
  DIRECTION INPUT ;
  USE SIGNAL ;
  PORT
   LAYER M5 ;
   RECT 141.600 189.996 141.624 190.080 ;
  END
 END i_d[433]
 PIN i_d[434]
  DIRECTION INPUT ;
  USE SIGNAL ;
  PORT
   LAYER M5 ;
   RECT 141.792 189.996 141.816 190.080 ;
  END
 END i_d[434]
 PIN i_d[435]
  DIRECTION INPUT ;
  USE SIGNAL ;
  PORT
   LAYER M5 ;
   RECT 141.984 189.996 142.008 190.080 ;
  END
 END i_d[435]
 PIN i_d[436]
  DIRECTION INPUT ;
  USE SIGNAL ;
  PORT
   LAYER M5 ;
   RECT 142.176 189.996 142.200 190.080 ;
  END
 END i_d[436]
 PIN i_d[437]
  DIRECTION INPUT ;
  USE SIGNAL ;
  PORT
   LAYER M5 ;
   RECT 142.368 189.996 142.392 190.080 ;
  END
 END i_d[437]
 PIN i_d[438]
  DIRECTION INPUT ;
  USE SIGNAL ;
  PORT
   LAYER M5 ;
   RECT 142.560 189.996 142.584 190.080 ;
  END
 END i_d[438]
 PIN i_d[439]
  DIRECTION INPUT ;
  USE SIGNAL ;
  PORT
   LAYER M5 ;
   RECT 142.752 189.996 142.776 190.080 ;
  END
 END i_d[439]
 PIN i_d[440]
  DIRECTION INPUT ;
  USE SIGNAL ;
  PORT
   LAYER M5 ;
   RECT 142.944 189.996 142.968 190.080 ;
  END
 END i_d[440]
 PIN i_d[441]
  DIRECTION INPUT ;
  USE SIGNAL ;
  PORT
   LAYER M5 ;
   RECT 143.136 189.996 143.160 190.080 ;
  END
 END i_d[441]
 PIN i_d[442]
  DIRECTION INPUT ;
  USE SIGNAL ;
  PORT
   LAYER M5 ;
   RECT 143.328 189.996 143.352 190.080 ;
  END
 END i_d[442]
 PIN i_d[443]
  DIRECTION INPUT ;
  USE SIGNAL ;
  PORT
   LAYER M5 ;
   RECT 143.520 189.996 143.544 190.080 ;
  END
 END i_d[443]
 PIN i_d[444]
  DIRECTION INPUT ;
  USE SIGNAL ;
  PORT
   LAYER M5 ;
   RECT 143.712 189.996 143.736 190.080 ;
  END
 END i_d[444]
 PIN i_d[445]
  DIRECTION INPUT ;
  USE SIGNAL ;
  PORT
   LAYER M5 ;
   RECT 143.904 189.996 143.928 190.080 ;
  END
 END i_d[445]
 PIN i_d[446]
  DIRECTION INPUT ;
  USE SIGNAL ;
  PORT
   LAYER M5 ;
   RECT 144.096 189.996 144.120 190.080 ;
  END
 END i_d[446]
 PIN i_d[447]
  DIRECTION INPUT ;
  USE SIGNAL ;
  PORT
   LAYER M5 ;
   RECT 144.288 189.996 144.312 190.080 ;
  END
 END i_d[447]
 PIN i_d[448]
  DIRECTION INPUT ;
  USE SIGNAL ;
  PORT
   LAYER M5 ;
   RECT 144.480 189.996 144.504 190.080 ;
  END
 END i_d[448]
 PIN i_d[449]
  DIRECTION INPUT ;
  USE SIGNAL ;
  PORT
   LAYER M5 ;
   RECT 144.672 189.996 144.696 190.080 ;
  END
 END i_d[449]
 PIN i_d[450]
  DIRECTION INPUT ;
  USE SIGNAL ;
  PORT
   LAYER M5 ;
   RECT 144.864 189.996 144.888 190.080 ;
  END
 END i_d[450]
 PIN i_d[451]
  DIRECTION INPUT ;
  USE SIGNAL ;
  PORT
   LAYER M5 ;
   RECT 145.056 189.996 145.080 190.080 ;
  END
 END i_d[451]
 PIN i_d[452]
  DIRECTION INPUT ;
  USE SIGNAL ;
  PORT
   LAYER M5 ;
   RECT 145.248 189.996 145.272 190.080 ;
  END
 END i_d[452]
 PIN i_d[453]
  DIRECTION INPUT ;
  USE SIGNAL ;
  PORT
   LAYER M5 ;
   RECT 145.440 189.996 145.464 190.080 ;
  END
 END i_d[453]
 PIN i_d[454]
  DIRECTION INPUT ;
  USE SIGNAL ;
  PORT
   LAYER M5 ;
   RECT 145.632 189.996 145.656 190.080 ;
  END
 END i_d[454]
 PIN i_d[455]
  DIRECTION INPUT ;
  USE SIGNAL ;
  PORT
   LAYER M5 ;
   RECT 145.824 189.996 145.848 190.080 ;
  END
 END i_d[455]
 PIN i_d[456]
  DIRECTION INPUT ;
  USE SIGNAL ;
  PORT
   LAYER M5 ;
   RECT 146.016 189.996 146.040 190.080 ;
  END
 END i_d[456]
 PIN i_d[457]
  DIRECTION INPUT ;
  USE SIGNAL ;
  PORT
   LAYER M5 ;
   RECT 146.208 189.996 146.232 190.080 ;
  END
 END i_d[457]
 PIN i_d[458]
  DIRECTION INPUT ;
  USE SIGNAL ;
  PORT
   LAYER M5 ;
   RECT 146.400 189.996 146.424 190.080 ;
  END
 END i_d[458]
 PIN i_d[459]
  DIRECTION INPUT ;
  USE SIGNAL ;
  PORT
   LAYER M5 ;
   RECT 146.592 189.996 146.616 190.080 ;
  END
 END i_d[459]
 PIN i_d[460]
  DIRECTION INPUT ;
  USE SIGNAL ;
  PORT
   LAYER M5 ;
   RECT 146.784 189.996 146.808 190.080 ;
  END
 END i_d[460]
 PIN i_d[461]
  DIRECTION INPUT ;
  USE SIGNAL ;
  PORT
   LAYER M5 ;
   RECT 146.976 189.996 147.000 190.080 ;
  END
 END i_d[461]
 PIN i_d[462]
  DIRECTION INPUT ;
  USE SIGNAL ;
  PORT
   LAYER M5 ;
   RECT 147.168 189.996 147.192 190.080 ;
  END
 END i_d[462]
 PIN i_d[463]
  DIRECTION INPUT ;
  USE SIGNAL ;
  PORT
   LAYER M5 ;
   RECT 147.360 189.996 147.384 190.080 ;
  END
 END i_d[463]
 PIN i_d[464]
  DIRECTION INPUT ;
  USE SIGNAL ;
  PORT
   LAYER M5 ;
   RECT 147.552 189.996 147.576 190.080 ;
  END
 END i_d[464]
 PIN i_d[465]
  DIRECTION INPUT ;
  USE SIGNAL ;
  PORT
   LAYER M5 ;
   RECT 147.744 189.996 147.768 190.080 ;
  END
 END i_d[465]
 PIN i_d[466]
  DIRECTION INPUT ;
  USE SIGNAL ;
  PORT
   LAYER M5 ;
   RECT 147.936 189.996 147.960 190.080 ;
  END
 END i_d[466]
 PIN i_d[467]
  DIRECTION INPUT ;
  USE SIGNAL ;
  PORT
   LAYER M5 ;
   RECT 148.128 189.996 148.152 190.080 ;
  END
 END i_d[467]
 PIN i_d[468]
  DIRECTION INPUT ;
  USE SIGNAL ;
  PORT
   LAYER M5 ;
   RECT 148.320 189.996 148.344 190.080 ;
  END
 END i_d[468]
 PIN i_d[469]
  DIRECTION INPUT ;
  USE SIGNAL ;
  PORT
   LAYER M5 ;
   RECT 148.512 189.996 148.536 190.080 ;
  END
 END i_d[469]
 PIN i_d[470]
  DIRECTION INPUT ;
  USE SIGNAL ;
  PORT
   LAYER M5 ;
   RECT 148.704 189.996 148.728 190.080 ;
  END
 END i_d[470]
 PIN i_d[471]
  DIRECTION INPUT ;
  USE SIGNAL ;
  PORT
   LAYER M5 ;
   RECT 148.896 189.996 148.920 190.080 ;
  END
 END i_d[471]
 PIN i_d[472]
  DIRECTION INPUT ;
  USE SIGNAL ;
  PORT
   LAYER M5 ;
   RECT 149.088 189.996 149.112 190.080 ;
  END
 END i_d[472]
 PIN i_d[473]
  DIRECTION INPUT ;
  USE SIGNAL ;
  PORT
   LAYER M5 ;
   RECT 149.280 189.996 149.304 190.080 ;
  END
 END i_d[473]
 PIN i_d[474]
  DIRECTION INPUT ;
  USE SIGNAL ;
  PORT
   LAYER M5 ;
   RECT 149.472 189.996 149.496 190.080 ;
  END
 END i_d[474]
 PIN i_d[475]
  DIRECTION INPUT ;
  USE SIGNAL ;
  PORT
   LAYER M5 ;
   RECT 149.664 189.996 149.688 190.080 ;
  END
 END i_d[475]
 PIN i_d[476]
  DIRECTION INPUT ;
  USE SIGNAL ;
  PORT
   LAYER M5 ;
   RECT 149.856 189.996 149.880 190.080 ;
  END
 END i_d[476]
 PIN i_d[477]
  DIRECTION INPUT ;
  USE SIGNAL ;
  PORT
   LAYER M5 ;
   RECT 150.048 189.996 150.072 190.080 ;
  END
 END i_d[477]
 PIN i_d[478]
  DIRECTION INPUT ;
  USE SIGNAL ;
  PORT
   LAYER M5 ;
   RECT 150.240 189.996 150.264 190.080 ;
  END
 END i_d[478]
 PIN i_d[479]
  DIRECTION INPUT ;
  USE SIGNAL ;
  PORT
   LAYER M5 ;
   RECT 150.432 189.996 150.456 190.080 ;
  END
 END i_d[479]
 PIN i_d[480]
  DIRECTION INPUT ;
  USE SIGNAL ;
  PORT
   LAYER M5 ;
   RECT 150.624 189.996 150.648 190.080 ;
  END
 END i_d[480]
 PIN i_d[481]
  DIRECTION INPUT ;
  USE SIGNAL ;
  PORT
   LAYER M5 ;
   RECT 150.816 189.996 150.840 190.080 ;
  END
 END i_d[481]
 PIN i_d[482]
  DIRECTION INPUT ;
  USE SIGNAL ;
  PORT
   LAYER M5 ;
   RECT 151.008 189.996 151.032 190.080 ;
  END
 END i_d[482]
 PIN i_d[483]
  DIRECTION INPUT ;
  USE SIGNAL ;
  PORT
   LAYER M5 ;
   RECT 151.200 189.996 151.224 190.080 ;
  END
 END i_d[483]
 PIN i_d[484]
  DIRECTION INPUT ;
  USE SIGNAL ;
  PORT
   LAYER M5 ;
   RECT 151.392 189.996 151.416 190.080 ;
  END
 END i_d[484]
 PIN i_d[485]
  DIRECTION INPUT ;
  USE SIGNAL ;
  PORT
   LAYER M5 ;
   RECT 151.584 189.996 151.608 190.080 ;
  END
 END i_d[485]
 PIN i_d[486]
  DIRECTION INPUT ;
  USE SIGNAL ;
  PORT
   LAYER M5 ;
   RECT 151.776 189.996 151.800 190.080 ;
  END
 END i_d[486]
 PIN i_d[487]
  DIRECTION INPUT ;
  USE SIGNAL ;
  PORT
   LAYER M5 ;
   RECT 151.968 189.996 151.992 190.080 ;
  END
 END i_d[487]
 PIN i_d[488]
  DIRECTION INPUT ;
  USE SIGNAL ;
  PORT
   LAYER M5 ;
   RECT 152.160 189.996 152.184 190.080 ;
  END
 END i_d[488]
 PIN i_d[489]
  DIRECTION INPUT ;
  USE SIGNAL ;
  PORT
   LAYER M5 ;
   RECT 152.352 189.996 152.376 190.080 ;
  END
 END i_d[489]
 PIN i_d[490]
  DIRECTION INPUT ;
  USE SIGNAL ;
  PORT
   LAYER M5 ;
   RECT 152.544 189.996 152.568 190.080 ;
  END
 END i_d[490]
 PIN i_d[491]
  DIRECTION INPUT ;
  USE SIGNAL ;
  PORT
   LAYER M5 ;
   RECT 152.736 189.996 152.760 190.080 ;
  END
 END i_d[491]
 PIN i_d[492]
  DIRECTION INPUT ;
  USE SIGNAL ;
  PORT
   LAYER M5 ;
   RECT 152.928 189.996 152.952 190.080 ;
  END
 END i_d[492]
 PIN i_d[493]
  DIRECTION INPUT ;
  USE SIGNAL ;
  PORT
   LAYER M5 ;
   RECT 153.120 189.996 153.144 190.080 ;
  END
 END i_d[493]
 PIN i_d[494]
  DIRECTION INPUT ;
  USE SIGNAL ;
  PORT
   LAYER M5 ;
   RECT 153.312 189.996 153.336 190.080 ;
  END
 END i_d[494]
 PIN i_d[495]
  DIRECTION INPUT ;
  USE SIGNAL ;
  PORT
   LAYER M5 ;
   RECT 153.504 189.996 153.528 190.080 ;
  END
 END i_d[495]
 PIN i_d[496]
  DIRECTION INPUT ;
  USE SIGNAL ;
  PORT
   LAYER M5 ;
   RECT 153.696 189.996 153.720 190.080 ;
  END
 END i_d[496]
 PIN i_d[497]
  DIRECTION INPUT ;
  USE SIGNAL ;
  PORT
   LAYER M5 ;
   RECT 153.888 189.996 153.912 190.080 ;
  END
 END i_d[497]
 PIN i_d[498]
  DIRECTION INPUT ;
  USE SIGNAL ;
  PORT
   LAYER M5 ;
   RECT 154.080 189.996 154.104 190.080 ;
  END
 END i_d[498]
 PIN i_d[499]
  DIRECTION INPUT ;
  USE SIGNAL ;
  PORT
   LAYER M5 ;
   RECT 154.272 189.996 154.296 190.080 ;
  END
 END i_d[499]
 PIN i_d[500]
  DIRECTION INPUT ;
  USE SIGNAL ;
  PORT
   LAYER M5 ;
   RECT 154.464 189.996 154.488 190.080 ;
  END
 END i_d[500]
 PIN i_d[501]
  DIRECTION INPUT ;
  USE SIGNAL ;
  PORT
   LAYER M5 ;
   RECT 154.656 189.996 154.680 190.080 ;
  END
 END i_d[501]
 PIN i_d[502]
  DIRECTION INPUT ;
  USE SIGNAL ;
  PORT
   LAYER M5 ;
   RECT 154.848 189.996 154.872 190.080 ;
  END
 END i_d[502]
 PIN i_d[503]
  DIRECTION INPUT ;
  USE SIGNAL ;
  PORT
   LAYER M5 ;
   RECT 155.040 189.996 155.064 190.080 ;
  END
 END i_d[503]
 PIN i_d[504]
  DIRECTION INPUT ;
  USE SIGNAL ;
  PORT
   LAYER M5 ;
   RECT 155.232 189.996 155.256 190.080 ;
  END
 END i_d[504]
 PIN i_d[505]
  DIRECTION INPUT ;
  USE SIGNAL ;
  PORT
   LAYER M5 ;
   RECT 155.424 189.996 155.448 190.080 ;
  END
 END i_d[505]
 PIN i_d[506]
  DIRECTION INPUT ;
  USE SIGNAL ;
  PORT
   LAYER M5 ;
   RECT 155.616 189.996 155.640 190.080 ;
  END
 END i_d[506]
 PIN i_d[507]
  DIRECTION INPUT ;
  USE SIGNAL ;
  PORT
   LAYER M5 ;
   RECT 155.808 189.996 155.832 190.080 ;
  END
 END i_d[507]
 PIN i_d[508]
  DIRECTION INPUT ;
  USE SIGNAL ;
  PORT
   LAYER M5 ;
   RECT 156.000 189.996 156.024 190.080 ;
  END
 END i_d[508]
 PIN i_d[509]
  DIRECTION INPUT ;
  USE SIGNAL ;
  PORT
   LAYER M5 ;
   RECT 156.192 189.996 156.216 190.080 ;
  END
 END i_d[509]
 PIN i_d[510]
  DIRECTION INPUT ;
  USE SIGNAL ;
  PORT
   LAYER M5 ;
   RECT 156.384 189.996 156.408 190.080 ;
  END
 END i_d[510]
 PIN i_d[511]
  DIRECTION INPUT ;
  USE SIGNAL ;
  PORT
   LAYER M5 ;
   RECT 156.576 189.996 156.600 190.080 ;
  END
 END i_d[511]
 PIN i_d[512]
  DIRECTION INPUT ;
  USE SIGNAL ;
  PORT
   LAYER M5 ;
   RECT 156.768 189.996 156.792 190.080 ;
  END
 END i_d[512]
 PIN i_d[513]
  DIRECTION INPUT ;
  USE SIGNAL ;
  PORT
   LAYER M5 ;
   RECT 156.960 189.996 156.984 190.080 ;
  END
 END i_d[513]
 PIN i_d[514]
  DIRECTION INPUT ;
  USE SIGNAL ;
  PORT
   LAYER M5 ;
   RECT 157.152 189.996 157.176 190.080 ;
  END
 END i_d[514]
 PIN i_d[515]
  DIRECTION INPUT ;
  USE SIGNAL ;
  PORT
   LAYER M5 ;
   RECT 157.344 189.996 157.368 190.080 ;
  END
 END i_d[515]
 PIN i_d[516]
  DIRECTION INPUT ;
  USE SIGNAL ;
  PORT
   LAYER M5 ;
   RECT 157.536 189.996 157.560 190.080 ;
  END
 END i_d[516]
 PIN i_d[517]
  DIRECTION INPUT ;
  USE SIGNAL ;
  PORT
   LAYER M5 ;
   RECT 157.728 189.996 157.752 190.080 ;
  END
 END i_d[517]
 PIN i_d[518]
  DIRECTION INPUT ;
  USE SIGNAL ;
  PORT
   LAYER M5 ;
   RECT 157.920 189.996 157.944 190.080 ;
  END
 END i_d[518]
 PIN i_d[519]
  DIRECTION INPUT ;
  USE SIGNAL ;
  PORT
   LAYER M5 ;
   RECT 158.112 189.996 158.136 190.080 ;
  END
 END i_d[519]
 PIN i_d[520]
  DIRECTION INPUT ;
  USE SIGNAL ;
  PORT
   LAYER M5 ;
   RECT 158.304 189.996 158.328 190.080 ;
  END
 END i_d[520]
 PIN i_d[521]
  DIRECTION INPUT ;
  USE SIGNAL ;
  PORT
   LAYER M5 ;
   RECT 158.496 189.996 158.520 190.080 ;
  END
 END i_d[521]
 PIN i_d[522]
  DIRECTION INPUT ;
  USE SIGNAL ;
  PORT
   LAYER M5 ;
   RECT 158.688 189.996 158.712 190.080 ;
  END
 END i_d[522]
 PIN i_d[523]
  DIRECTION INPUT ;
  USE SIGNAL ;
  PORT
   LAYER M5 ;
   RECT 158.880 189.996 158.904 190.080 ;
  END
 END i_d[523]
 PIN i_d[524]
  DIRECTION INPUT ;
  USE SIGNAL ;
  PORT
   LAYER M5 ;
   RECT 159.072 189.996 159.096 190.080 ;
  END
 END i_d[524]
 PIN i_d[525]
  DIRECTION INPUT ;
  USE SIGNAL ;
  PORT
   LAYER M5 ;
   RECT 159.264 189.996 159.288 190.080 ;
  END
 END i_d[525]
 PIN i_d[526]
  DIRECTION INPUT ;
  USE SIGNAL ;
  PORT
   LAYER M5 ;
   RECT 159.456 189.996 159.480 190.080 ;
  END
 END i_d[526]
 PIN i_d[527]
  DIRECTION INPUT ;
  USE SIGNAL ;
  PORT
   LAYER M5 ;
   RECT 159.648 189.996 159.672 190.080 ;
  END
 END i_d[527]
 PIN i_d[528]
  DIRECTION INPUT ;
  USE SIGNAL ;
  PORT
   LAYER M5 ;
   RECT 159.840 189.996 159.864 190.080 ;
  END
 END i_d[528]
 PIN i_d[529]
  DIRECTION INPUT ;
  USE SIGNAL ;
  PORT
   LAYER M5 ;
   RECT 160.032 189.996 160.056 190.080 ;
  END
 END i_d[529]
 PIN i_d[530]
  DIRECTION INPUT ;
  USE SIGNAL ;
  PORT
   LAYER M5 ;
   RECT 160.224 189.996 160.248 190.080 ;
  END
 END i_d[530]
 PIN i_d[531]
  DIRECTION INPUT ;
  USE SIGNAL ;
  PORT
   LAYER M5 ;
   RECT 160.416 189.996 160.440 190.080 ;
  END
 END i_d[531]
 PIN i_d[532]
  DIRECTION INPUT ;
  USE SIGNAL ;
  PORT
   LAYER M5 ;
   RECT 160.608 189.996 160.632 190.080 ;
  END
 END i_d[532]
 PIN i_d[533]
  DIRECTION INPUT ;
  USE SIGNAL ;
  PORT
   LAYER M5 ;
   RECT 160.800 189.996 160.824 190.080 ;
  END
 END i_d[533]
 PIN i_d[534]
  DIRECTION INPUT ;
  USE SIGNAL ;
  PORT
   LAYER M5 ;
   RECT 160.992 189.996 161.016 190.080 ;
  END
 END i_d[534]
 PIN i_d[535]
  DIRECTION INPUT ;
  USE SIGNAL ;
  PORT
   LAYER M5 ;
   RECT 161.184 189.996 161.208 190.080 ;
  END
 END i_d[535]
 PIN i_d[536]
  DIRECTION INPUT ;
  USE SIGNAL ;
  PORT
   LAYER M5 ;
   RECT 161.376 189.996 161.400 190.080 ;
  END
 END i_d[536]
 PIN i_d[537]
  DIRECTION INPUT ;
  USE SIGNAL ;
  PORT
   LAYER M5 ;
   RECT 161.568 189.996 161.592 190.080 ;
  END
 END i_d[537]
 PIN i_d[538]
  DIRECTION INPUT ;
  USE SIGNAL ;
  PORT
   LAYER M5 ;
   RECT 161.760 189.996 161.784 190.080 ;
  END
 END i_d[538]
 PIN i_d[539]
  DIRECTION INPUT ;
  USE SIGNAL ;
  PORT
   LAYER M5 ;
   RECT 161.952 189.996 161.976 190.080 ;
  END
 END i_d[539]
 PIN i_d[540]
  DIRECTION INPUT ;
  USE SIGNAL ;
  PORT
   LAYER M5 ;
   RECT 162.144 189.996 162.168 190.080 ;
  END
 END i_d[540]
 PIN i_d[541]
  DIRECTION INPUT ;
  USE SIGNAL ;
  PORT
   LAYER M5 ;
   RECT 162.336 189.996 162.360 190.080 ;
  END
 END i_d[541]
 PIN i_d[542]
  DIRECTION INPUT ;
  USE SIGNAL ;
  PORT
   LAYER M5 ;
   RECT 162.528 189.996 162.552 190.080 ;
  END
 END i_d[542]
 PIN i_d[543]
  DIRECTION INPUT ;
  USE SIGNAL ;
  PORT
   LAYER M5 ;
   RECT 162.720 189.996 162.744 190.080 ;
  END
 END i_d[543]
 PIN i_am[0]
  DIRECTION INPUT ;
  USE SIGNAL ;
  PORT
   LAYER M5 ;
   RECT 162.912 189.996 162.936 190.080 ;
  END
 END i_am[0]
 PIN i_am[1]
  DIRECTION INPUT ;
  USE SIGNAL ;
  PORT
   LAYER M5 ;
   RECT 163.104 189.996 163.128 190.080 ;
  END
 END i_am[1]
 PIN i_am[2]
  DIRECTION INPUT ;
  USE SIGNAL ;
  PORT
   LAYER M5 ;
   RECT 163.296 189.996 163.320 190.080 ;
  END
 END i_am[2]
 PIN i_am[3]
  DIRECTION INPUT ;
  USE SIGNAL ;
  PORT
   LAYER M5 ;
   RECT 163.488 189.996 163.512 190.080 ;
  END
 END i_am[3]
 PIN i_am[4]
  DIRECTION INPUT ;
  USE SIGNAL ;
  PORT
   LAYER M5 ;
   RECT 163.680 189.996 163.704 190.080 ;
  END
 END i_am[4]
 PIN i_am[5]
  DIRECTION INPUT ;
  USE SIGNAL ;
  PORT
   LAYER M5 ;
   RECT 163.872 189.996 163.896 190.080 ;
  END
 END i_am[5]
 PIN i_am[6]
  DIRECTION INPUT ;
  USE SIGNAL ;
  PORT
   LAYER M5 ;
   RECT 164.064 189.996 164.088 190.080 ;
  END
 END i_am[6]
 PIN i_am[7]
  DIRECTION INPUT ;
  USE SIGNAL ;
  PORT
   LAYER M5 ;
   RECT 164.256 189.996 164.280 190.080 ;
  END
 END i_am[7]
 PIN i_am[8]
  DIRECTION INPUT ;
  USE SIGNAL ;
  PORT
   LAYER M5 ;
   RECT 164.448 189.996 164.472 190.080 ;
  END
 END i_am[8]
 PIN x_q[0]
  DIRECTION OUTPUT ;
  USE SIGNAL ;
  PORT
   LAYER M5 ;
   RECT 20.016 0.000 20.040 0.084 ;
  END
 END x_q[0]
 PIN x_q[1]
  DIRECTION OUTPUT ;
  USE SIGNAL ;
  PORT
   LAYER M5 ;
   RECT 20.208 0.000 20.232 0.084 ;
  END
 END x_q[1]
 PIN x_q[2]
  DIRECTION OUTPUT ;
  USE SIGNAL ;
  PORT
   LAYER M5 ;
   RECT 20.400 0.000 20.424 0.084 ;
  END
 END x_q[2]
 PIN x_q[3]
  DIRECTION OUTPUT ;
  USE SIGNAL ;
  PORT
   LAYER M5 ;
   RECT 20.592 0.000 20.616 0.084 ;
  END
 END x_q[3]
 PIN x_q[4]
  DIRECTION OUTPUT ;
  USE SIGNAL ;
  PORT
   LAYER M5 ;
   RECT 20.784 0.000 20.808 0.084 ;
  END
 END x_q[4]
 PIN x_q[5]
  DIRECTION OUTPUT ;
  USE SIGNAL ;
  PORT
   LAYER M5 ;
   RECT 20.976 0.000 21.000 0.084 ;
  END
 END x_q[5]
 PIN x_q[6]
  DIRECTION OUTPUT ;
  USE SIGNAL ;
  PORT
   LAYER M5 ;
   RECT 21.168 0.000 21.192 0.084 ;
  END
 END x_q[6]
 PIN x_q[7]
  DIRECTION OUTPUT ;
  USE SIGNAL ;
  PORT
   LAYER M5 ;
   RECT 21.360 0.000 21.384 0.084 ;
  END
 END x_q[7]
 PIN x_q[8]
  DIRECTION OUTPUT ;
  USE SIGNAL ;
  PORT
   LAYER M5 ;
   RECT 21.552 0.000 21.576 0.084 ;
  END
 END x_q[8]
 PIN x_q[9]
  DIRECTION OUTPUT ;
  USE SIGNAL ;
  PORT
   LAYER M5 ;
   RECT 21.744 0.000 21.768 0.084 ;
  END
 END x_q[9]
 PIN x_q[10]
  DIRECTION OUTPUT ;
  USE SIGNAL ;
  PORT
   LAYER M5 ;
   RECT 21.936 0.000 21.960 0.084 ;
  END
 END x_q[10]
 PIN x_q[11]
  DIRECTION OUTPUT ;
  USE SIGNAL ;
  PORT
   LAYER M5 ;
   RECT 22.128 0.000 22.152 0.084 ;
  END
 END x_q[11]
 PIN x_q[12]
  DIRECTION OUTPUT ;
  USE SIGNAL ;
  PORT
   LAYER M5 ;
   RECT 22.320 0.000 22.344 0.084 ;
  END
 END x_q[12]
 PIN x_q[13]
  DIRECTION OUTPUT ;
  USE SIGNAL ;
  PORT
   LAYER M5 ;
   RECT 22.512 0.000 22.536 0.084 ;
  END
 END x_q[13]
 PIN x_q[14]
  DIRECTION OUTPUT ;
  USE SIGNAL ;
  PORT
   LAYER M5 ;
   RECT 22.704 0.000 22.728 0.084 ;
  END
 END x_q[14]
 PIN x_q[15]
  DIRECTION OUTPUT ;
  USE SIGNAL ;
  PORT
   LAYER M5 ;
   RECT 22.896 0.000 22.920 0.084 ;
  END
 END x_q[15]
 PIN x_q[16]
  DIRECTION OUTPUT ;
  USE SIGNAL ;
  PORT
   LAYER M5 ;
   RECT 23.088 0.000 23.112 0.084 ;
  END
 END x_q[16]
 PIN x_q[17]
  DIRECTION OUTPUT ;
  USE SIGNAL ;
  PORT
   LAYER M5 ;
   RECT 23.280 0.000 23.304 0.084 ;
  END
 END x_q[17]
 PIN x_q[18]
  DIRECTION OUTPUT ;
  USE SIGNAL ;
  PORT
   LAYER M5 ;
   RECT 23.472 0.000 23.496 0.084 ;
  END
 END x_q[18]
 PIN x_q[19]
  DIRECTION OUTPUT ;
  USE SIGNAL ;
  PORT
   LAYER M5 ;
   RECT 23.664 0.000 23.688 0.084 ;
  END
 END x_q[19]
 PIN x_q[20]
  DIRECTION OUTPUT ;
  USE SIGNAL ;
  PORT
   LAYER M5 ;
   RECT 23.856 0.000 23.880 0.084 ;
  END
 END x_q[20]
 PIN x_q[21]
  DIRECTION OUTPUT ;
  USE SIGNAL ;
  PORT
   LAYER M5 ;
   RECT 24.048 0.000 24.072 0.084 ;
  END
 END x_q[21]
 PIN x_q[22]
  DIRECTION OUTPUT ;
  USE SIGNAL ;
  PORT
   LAYER M5 ;
   RECT 24.240 0.000 24.264 0.084 ;
  END
 END x_q[22]
 PIN x_q[23]
  DIRECTION OUTPUT ;
  USE SIGNAL ;
  PORT
   LAYER M5 ;
   RECT 24.432 0.000 24.456 0.084 ;
  END
 END x_q[23]
 PIN x_q[24]
  DIRECTION OUTPUT ;
  USE SIGNAL ;
  PORT
   LAYER M5 ;
   RECT 24.624 0.000 24.648 0.084 ;
  END
 END x_q[24]
 PIN x_q[25]
  DIRECTION OUTPUT ;
  USE SIGNAL ;
  PORT
   LAYER M5 ;
   RECT 24.816 0.000 24.840 0.084 ;
  END
 END x_q[25]
 PIN x_q[26]
  DIRECTION OUTPUT ;
  USE SIGNAL ;
  PORT
   LAYER M5 ;
   RECT 25.008 0.000 25.032 0.084 ;
  END
 END x_q[26]
 PIN x_q[27]
  DIRECTION OUTPUT ;
  USE SIGNAL ;
  PORT
   LAYER M5 ;
   RECT 25.200 0.000 25.224 0.084 ;
  END
 END x_q[27]
 PIN x_q[28]
  DIRECTION OUTPUT ;
  USE SIGNAL ;
  PORT
   LAYER M5 ;
   RECT 25.392 0.000 25.416 0.084 ;
  END
 END x_q[28]
 PIN x_q[29]
  DIRECTION OUTPUT ;
  USE SIGNAL ;
  PORT
   LAYER M5 ;
   RECT 25.584 0.000 25.608 0.084 ;
  END
 END x_q[29]
 PIN x_q[30]
  DIRECTION OUTPUT ;
  USE SIGNAL ;
  PORT
   LAYER M5 ;
   RECT 25.776 0.000 25.800 0.084 ;
  END
 END x_q[30]
 PIN x_q[31]
  DIRECTION OUTPUT ;
  USE SIGNAL ;
  PORT
   LAYER M5 ;
   RECT 25.968 0.000 25.992 0.084 ;
  END
 END x_q[31]
 PIN x_q[32]
  DIRECTION OUTPUT ;
  USE SIGNAL ;
  PORT
   LAYER M5 ;
   RECT 26.160 0.000 26.184 0.084 ;
  END
 END x_q[32]
 PIN x_q[33]
  DIRECTION OUTPUT ;
  USE SIGNAL ;
  PORT
   LAYER M5 ;
   RECT 26.352 0.000 26.376 0.084 ;
  END
 END x_q[33]
 PIN x_q[34]
  DIRECTION OUTPUT ;
  USE SIGNAL ;
  PORT
   LAYER M5 ;
   RECT 26.544 0.000 26.568 0.084 ;
  END
 END x_q[34]
 PIN x_q[35]
  DIRECTION OUTPUT ;
  USE SIGNAL ;
  PORT
   LAYER M5 ;
   RECT 26.736 0.000 26.760 0.084 ;
  END
 END x_q[35]
 PIN x_q[36]
  DIRECTION OUTPUT ;
  USE SIGNAL ;
  PORT
   LAYER M5 ;
   RECT 26.928 0.000 26.952 0.084 ;
  END
 END x_q[36]
 PIN x_q[37]
  DIRECTION OUTPUT ;
  USE SIGNAL ;
  PORT
   LAYER M5 ;
   RECT 27.120 0.000 27.144 0.084 ;
  END
 END x_q[37]
 PIN x_q[38]
  DIRECTION OUTPUT ;
  USE SIGNAL ;
  PORT
   LAYER M5 ;
   RECT 27.312 0.000 27.336 0.084 ;
  END
 END x_q[38]
 PIN x_q[39]
  DIRECTION OUTPUT ;
  USE SIGNAL ;
  PORT
   LAYER M5 ;
   RECT 27.504 0.000 27.528 0.084 ;
  END
 END x_q[39]
 PIN x_q[40]
  DIRECTION OUTPUT ;
  USE SIGNAL ;
  PORT
   LAYER M5 ;
   RECT 27.696 0.000 27.720 0.084 ;
  END
 END x_q[40]
 PIN x_q[41]
  DIRECTION OUTPUT ;
  USE SIGNAL ;
  PORT
   LAYER M5 ;
   RECT 27.888 0.000 27.912 0.084 ;
  END
 END x_q[41]
 PIN x_q[42]
  DIRECTION OUTPUT ;
  USE SIGNAL ;
  PORT
   LAYER M5 ;
   RECT 28.080 0.000 28.104 0.084 ;
  END
 END x_q[42]
 PIN x_q[43]
  DIRECTION OUTPUT ;
  USE SIGNAL ;
  PORT
   LAYER M5 ;
   RECT 28.272 0.000 28.296 0.084 ;
  END
 END x_q[43]
 PIN x_q[44]
  DIRECTION OUTPUT ;
  USE SIGNAL ;
  PORT
   LAYER M5 ;
   RECT 28.464 0.000 28.488 0.084 ;
  END
 END x_q[44]
 PIN x_q[45]
  DIRECTION OUTPUT ;
  USE SIGNAL ;
  PORT
   LAYER M5 ;
   RECT 28.656 0.000 28.680 0.084 ;
  END
 END x_q[45]
 PIN x_q[46]
  DIRECTION OUTPUT ;
  USE SIGNAL ;
  PORT
   LAYER M5 ;
   RECT 28.848 0.000 28.872 0.084 ;
  END
 END x_q[46]
 PIN x_q[47]
  DIRECTION OUTPUT ;
  USE SIGNAL ;
  PORT
   LAYER M5 ;
   RECT 29.040 0.000 29.064 0.084 ;
  END
 END x_q[47]
 PIN x_q[48]
  DIRECTION OUTPUT ;
  USE SIGNAL ;
  PORT
   LAYER M5 ;
   RECT 29.232 0.000 29.256 0.084 ;
  END
 END x_q[48]
 PIN x_q[49]
  DIRECTION OUTPUT ;
  USE SIGNAL ;
  PORT
   LAYER M5 ;
   RECT 29.424 0.000 29.448 0.084 ;
  END
 END x_q[49]
 PIN x_q[50]
  DIRECTION OUTPUT ;
  USE SIGNAL ;
  PORT
   LAYER M5 ;
   RECT 29.616 0.000 29.640 0.084 ;
  END
 END x_q[50]
 PIN x_q[51]
  DIRECTION OUTPUT ;
  USE SIGNAL ;
  PORT
   LAYER M5 ;
   RECT 29.808 0.000 29.832 0.084 ;
  END
 END x_q[51]
 PIN x_q[52]
  DIRECTION OUTPUT ;
  USE SIGNAL ;
  PORT
   LAYER M5 ;
   RECT 30.000 0.000 30.024 0.084 ;
  END
 END x_q[52]
 PIN x_q[53]
  DIRECTION OUTPUT ;
  USE SIGNAL ;
  PORT
   LAYER M5 ;
   RECT 30.192 0.000 30.216 0.084 ;
  END
 END x_q[53]
 PIN x_q[54]
  DIRECTION OUTPUT ;
  USE SIGNAL ;
  PORT
   LAYER M5 ;
   RECT 30.384 0.000 30.408 0.084 ;
  END
 END x_q[54]
 PIN x_q[55]
  DIRECTION OUTPUT ;
  USE SIGNAL ;
  PORT
   LAYER M5 ;
   RECT 30.576 0.000 30.600 0.084 ;
  END
 END x_q[55]
 PIN x_q[56]
  DIRECTION OUTPUT ;
  USE SIGNAL ;
  PORT
   LAYER M5 ;
   RECT 30.768 0.000 30.792 0.084 ;
  END
 END x_q[56]
 PIN x_q[57]
  DIRECTION OUTPUT ;
  USE SIGNAL ;
  PORT
   LAYER M5 ;
   RECT 30.960 0.000 30.984 0.084 ;
  END
 END x_q[57]
 PIN x_q[58]
  DIRECTION OUTPUT ;
  USE SIGNAL ;
  PORT
   LAYER M5 ;
   RECT 31.152 0.000 31.176 0.084 ;
  END
 END x_q[58]
 PIN x_q[59]
  DIRECTION OUTPUT ;
  USE SIGNAL ;
  PORT
   LAYER M5 ;
   RECT 31.344 0.000 31.368 0.084 ;
  END
 END x_q[59]
 PIN x_q[60]
  DIRECTION OUTPUT ;
  USE SIGNAL ;
  PORT
   LAYER M5 ;
   RECT 31.536 0.000 31.560 0.084 ;
  END
 END x_q[60]
 PIN x_q[61]
  DIRECTION OUTPUT ;
  USE SIGNAL ;
  PORT
   LAYER M5 ;
   RECT 31.728 0.000 31.752 0.084 ;
  END
 END x_q[61]
 PIN x_q[62]
  DIRECTION OUTPUT ;
  USE SIGNAL ;
  PORT
   LAYER M5 ;
   RECT 31.920 0.000 31.944 0.084 ;
  END
 END x_q[62]
 PIN x_q[63]
  DIRECTION OUTPUT ;
  USE SIGNAL ;
  PORT
   LAYER M5 ;
   RECT 32.112 0.000 32.136 0.084 ;
  END
 END x_q[63]
 PIN x_q[64]
  DIRECTION OUTPUT ;
  USE SIGNAL ;
  PORT
   LAYER M5 ;
   RECT 32.304 0.000 32.328 0.084 ;
  END
 END x_q[64]
 PIN x_q[65]
  DIRECTION OUTPUT ;
  USE SIGNAL ;
  PORT
   LAYER M5 ;
   RECT 32.496 0.000 32.520 0.084 ;
  END
 END x_q[65]
 PIN x_q[66]
  DIRECTION OUTPUT ;
  USE SIGNAL ;
  PORT
   LAYER M5 ;
   RECT 32.688 0.000 32.712 0.084 ;
  END
 END x_q[66]
 PIN x_q[67]
  DIRECTION OUTPUT ;
  USE SIGNAL ;
  PORT
   LAYER M5 ;
   RECT 32.880 0.000 32.904 0.084 ;
  END
 END x_q[67]
 PIN x_q[68]
  DIRECTION OUTPUT ;
  USE SIGNAL ;
  PORT
   LAYER M5 ;
   RECT 33.072 0.000 33.096 0.084 ;
  END
 END x_q[68]
 PIN x_q[69]
  DIRECTION OUTPUT ;
  USE SIGNAL ;
  PORT
   LAYER M5 ;
   RECT 33.264 0.000 33.288 0.084 ;
  END
 END x_q[69]
 PIN x_q[70]
  DIRECTION OUTPUT ;
  USE SIGNAL ;
  PORT
   LAYER M5 ;
   RECT 33.456 0.000 33.480 0.084 ;
  END
 END x_q[70]
 PIN x_q[71]
  DIRECTION OUTPUT ;
  USE SIGNAL ;
  PORT
   LAYER M5 ;
   RECT 33.648 0.000 33.672 0.084 ;
  END
 END x_q[71]
 PIN x_q[72]
  DIRECTION OUTPUT ;
  USE SIGNAL ;
  PORT
   LAYER M5 ;
   RECT 33.840 0.000 33.864 0.084 ;
  END
 END x_q[72]
 PIN x_q[73]
  DIRECTION OUTPUT ;
  USE SIGNAL ;
  PORT
   LAYER M5 ;
   RECT 34.032 0.000 34.056 0.084 ;
  END
 END x_q[73]
 PIN x_q[74]
  DIRECTION OUTPUT ;
  USE SIGNAL ;
  PORT
   LAYER M5 ;
   RECT 34.224 0.000 34.248 0.084 ;
  END
 END x_q[74]
 PIN x_q[75]
  DIRECTION OUTPUT ;
  USE SIGNAL ;
  PORT
   LAYER M5 ;
   RECT 34.416 0.000 34.440 0.084 ;
  END
 END x_q[75]
 PIN x_q[76]
  DIRECTION OUTPUT ;
  USE SIGNAL ;
  PORT
   LAYER M5 ;
   RECT 34.608 0.000 34.632 0.084 ;
  END
 END x_q[76]
 PIN x_q[77]
  DIRECTION OUTPUT ;
  USE SIGNAL ;
  PORT
   LAYER M5 ;
   RECT 34.800 0.000 34.824 0.084 ;
  END
 END x_q[77]
 PIN x_q[78]
  DIRECTION OUTPUT ;
  USE SIGNAL ;
  PORT
   LAYER M5 ;
   RECT 34.992 0.000 35.016 0.084 ;
  END
 END x_q[78]
 PIN x_q[79]
  DIRECTION OUTPUT ;
  USE SIGNAL ;
  PORT
   LAYER M5 ;
   RECT 35.184 0.000 35.208 0.084 ;
  END
 END x_q[79]
 PIN x_q[80]
  DIRECTION OUTPUT ;
  USE SIGNAL ;
  PORT
   LAYER M5 ;
   RECT 35.376 0.000 35.400 0.084 ;
  END
 END x_q[80]
 PIN x_q[81]
  DIRECTION OUTPUT ;
  USE SIGNAL ;
  PORT
   LAYER M5 ;
   RECT 35.568 0.000 35.592 0.084 ;
  END
 END x_q[81]
 PIN x_q[82]
  DIRECTION OUTPUT ;
  USE SIGNAL ;
  PORT
   LAYER M5 ;
   RECT 35.760 0.000 35.784 0.084 ;
  END
 END x_q[82]
 PIN x_q[83]
  DIRECTION OUTPUT ;
  USE SIGNAL ;
  PORT
   LAYER M5 ;
   RECT 35.952 0.000 35.976 0.084 ;
  END
 END x_q[83]
 PIN x_q[84]
  DIRECTION OUTPUT ;
  USE SIGNAL ;
  PORT
   LAYER M5 ;
   RECT 36.144 0.000 36.168 0.084 ;
  END
 END x_q[84]
 PIN x_q[85]
  DIRECTION OUTPUT ;
  USE SIGNAL ;
  PORT
   LAYER M5 ;
   RECT 36.336 0.000 36.360 0.084 ;
  END
 END x_q[85]
 PIN x_q[86]
  DIRECTION OUTPUT ;
  USE SIGNAL ;
  PORT
   LAYER M5 ;
   RECT 36.528 0.000 36.552 0.084 ;
  END
 END x_q[86]
 PIN x_q[87]
  DIRECTION OUTPUT ;
  USE SIGNAL ;
  PORT
   LAYER M5 ;
   RECT 36.720 0.000 36.744 0.084 ;
  END
 END x_q[87]
 PIN x_q[88]
  DIRECTION OUTPUT ;
  USE SIGNAL ;
  PORT
   LAYER M5 ;
   RECT 36.912 0.000 36.936 0.084 ;
  END
 END x_q[88]
 PIN x_q[89]
  DIRECTION OUTPUT ;
  USE SIGNAL ;
  PORT
   LAYER M5 ;
   RECT 37.104 0.000 37.128 0.084 ;
  END
 END x_q[89]
 PIN x_q[90]
  DIRECTION OUTPUT ;
  USE SIGNAL ;
  PORT
   LAYER M5 ;
   RECT 37.296 0.000 37.320 0.084 ;
  END
 END x_q[90]
 PIN x_q[91]
  DIRECTION OUTPUT ;
  USE SIGNAL ;
  PORT
   LAYER M5 ;
   RECT 37.488 0.000 37.512 0.084 ;
  END
 END x_q[91]
 PIN x_q[92]
  DIRECTION OUTPUT ;
  USE SIGNAL ;
  PORT
   LAYER M5 ;
   RECT 37.680 0.000 37.704 0.084 ;
  END
 END x_q[92]
 PIN x_q[93]
  DIRECTION OUTPUT ;
  USE SIGNAL ;
  PORT
   LAYER M5 ;
   RECT 37.872 0.000 37.896 0.084 ;
  END
 END x_q[93]
 PIN x_q[94]
  DIRECTION OUTPUT ;
  USE SIGNAL ;
  PORT
   LAYER M5 ;
   RECT 38.064 0.000 38.088 0.084 ;
  END
 END x_q[94]
 PIN x_q[95]
  DIRECTION OUTPUT ;
  USE SIGNAL ;
  PORT
   LAYER M5 ;
   RECT 38.256 0.000 38.280 0.084 ;
  END
 END x_q[95]
 PIN x_q[96]
  DIRECTION OUTPUT ;
  USE SIGNAL ;
  PORT
   LAYER M5 ;
   RECT 38.448 0.000 38.472 0.084 ;
  END
 END x_q[96]
 PIN x_q[97]
  DIRECTION OUTPUT ;
  USE SIGNAL ;
  PORT
   LAYER M5 ;
   RECT 38.640 0.000 38.664 0.084 ;
  END
 END x_q[97]
 PIN x_q[98]
  DIRECTION OUTPUT ;
  USE SIGNAL ;
  PORT
   LAYER M5 ;
   RECT 38.832 0.000 38.856 0.084 ;
  END
 END x_q[98]
 PIN x_q[99]
  DIRECTION OUTPUT ;
  USE SIGNAL ;
  PORT
   LAYER M5 ;
   RECT 39.024 0.000 39.048 0.084 ;
  END
 END x_q[99]
 PIN x_q[100]
  DIRECTION OUTPUT ;
  USE SIGNAL ;
  PORT
   LAYER M5 ;
   RECT 39.216 0.000 39.240 0.084 ;
  END
 END x_q[100]
 PIN x_q[101]
  DIRECTION OUTPUT ;
  USE SIGNAL ;
  PORT
   LAYER M5 ;
   RECT 39.408 0.000 39.432 0.084 ;
  END
 END x_q[101]
 PIN x_q[102]
  DIRECTION OUTPUT ;
  USE SIGNAL ;
  PORT
   LAYER M5 ;
   RECT 39.600 0.000 39.624 0.084 ;
  END
 END x_q[102]
 PIN x_q[103]
  DIRECTION OUTPUT ;
  USE SIGNAL ;
  PORT
   LAYER M5 ;
   RECT 39.792 0.000 39.816 0.084 ;
  END
 END x_q[103]
 PIN x_q[104]
  DIRECTION OUTPUT ;
  USE SIGNAL ;
  PORT
   LAYER M5 ;
   RECT 39.984 0.000 40.008 0.084 ;
  END
 END x_q[104]
 PIN x_q[105]
  DIRECTION OUTPUT ;
  USE SIGNAL ;
  PORT
   LAYER M5 ;
   RECT 40.176 0.000 40.200 0.084 ;
  END
 END x_q[105]
 PIN x_q[106]
  DIRECTION OUTPUT ;
  USE SIGNAL ;
  PORT
   LAYER M5 ;
   RECT 40.368 0.000 40.392 0.084 ;
  END
 END x_q[106]
 PIN x_q[107]
  DIRECTION OUTPUT ;
  USE SIGNAL ;
  PORT
   LAYER M5 ;
   RECT 40.560 0.000 40.584 0.084 ;
  END
 END x_q[107]
 PIN x_q[108]
  DIRECTION OUTPUT ;
  USE SIGNAL ;
  PORT
   LAYER M5 ;
   RECT 40.752 0.000 40.776 0.084 ;
  END
 END x_q[108]
 PIN x_q[109]
  DIRECTION OUTPUT ;
  USE SIGNAL ;
  PORT
   LAYER M5 ;
   RECT 40.944 0.000 40.968 0.084 ;
  END
 END x_q[109]
 PIN x_q[110]
  DIRECTION OUTPUT ;
  USE SIGNAL ;
  PORT
   LAYER M5 ;
   RECT 41.136 0.000 41.160 0.084 ;
  END
 END x_q[110]
 PIN x_q[111]
  DIRECTION OUTPUT ;
  USE SIGNAL ;
  PORT
   LAYER M5 ;
   RECT 41.328 0.000 41.352 0.084 ;
  END
 END x_q[111]
 PIN x_q[112]
  DIRECTION OUTPUT ;
  USE SIGNAL ;
  PORT
   LAYER M5 ;
   RECT 41.520 0.000 41.544 0.084 ;
  END
 END x_q[112]
 PIN x_q[113]
  DIRECTION OUTPUT ;
  USE SIGNAL ;
  PORT
   LAYER M5 ;
   RECT 41.712 0.000 41.736 0.084 ;
  END
 END x_q[113]
 PIN x_q[114]
  DIRECTION OUTPUT ;
  USE SIGNAL ;
  PORT
   LAYER M5 ;
   RECT 41.904 0.000 41.928 0.084 ;
  END
 END x_q[114]
 PIN x_q[115]
  DIRECTION OUTPUT ;
  USE SIGNAL ;
  PORT
   LAYER M5 ;
   RECT 42.096 0.000 42.120 0.084 ;
  END
 END x_q[115]
 PIN x_q[116]
  DIRECTION OUTPUT ;
  USE SIGNAL ;
  PORT
   LAYER M5 ;
   RECT 42.288 0.000 42.312 0.084 ;
  END
 END x_q[116]
 PIN x_q[117]
  DIRECTION OUTPUT ;
  USE SIGNAL ;
  PORT
   LAYER M5 ;
   RECT 42.480 0.000 42.504 0.084 ;
  END
 END x_q[117]
 PIN x_q[118]
  DIRECTION OUTPUT ;
  USE SIGNAL ;
  PORT
   LAYER M5 ;
   RECT 42.672 0.000 42.696 0.084 ;
  END
 END x_q[118]
 PIN x_q[119]
  DIRECTION OUTPUT ;
  USE SIGNAL ;
  PORT
   LAYER M5 ;
   RECT 42.864 0.000 42.888 0.084 ;
  END
 END x_q[119]
 PIN x_q[120]
  DIRECTION OUTPUT ;
  USE SIGNAL ;
  PORT
   LAYER M5 ;
   RECT 43.056 0.000 43.080 0.084 ;
  END
 END x_q[120]
 PIN x_q[121]
  DIRECTION OUTPUT ;
  USE SIGNAL ;
  PORT
   LAYER M5 ;
   RECT 43.248 0.000 43.272 0.084 ;
  END
 END x_q[121]
 PIN x_q[122]
  DIRECTION OUTPUT ;
  USE SIGNAL ;
  PORT
   LAYER M5 ;
   RECT 43.440 0.000 43.464 0.084 ;
  END
 END x_q[122]
 PIN x_q[123]
  DIRECTION OUTPUT ;
  USE SIGNAL ;
  PORT
   LAYER M5 ;
   RECT 43.632 0.000 43.656 0.084 ;
  END
 END x_q[123]
 PIN x_q[124]
  DIRECTION OUTPUT ;
  USE SIGNAL ;
  PORT
   LAYER M5 ;
   RECT 43.824 0.000 43.848 0.084 ;
  END
 END x_q[124]
 PIN x_q[125]
  DIRECTION OUTPUT ;
  USE SIGNAL ;
  PORT
   LAYER M5 ;
   RECT 44.016 0.000 44.040 0.084 ;
  END
 END x_q[125]
 PIN x_q[126]
  DIRECTION OUTPUT ;
  USE SIGNAL ;
  PORT
   LAYER M5 ;
   RECT 44.208 0.000 44.232 0.084 ;
  END
 END x_q[126]
 PIN x_q[127]
  DIRECTION OUTPUT ;
  USE SIGNAL ;
  PORT
   LAYER M5 ;
   RECT 44.400 0.000 44.424 0.084 ;
  END
 END x_q[127]
 PIN x_q[128]
  DIRECTION OUTPUT ;
  USE SIGNAL ;
  PORT
   LAYER M5 ;
   RECT 44.592 0.000 44.616 0.084 ;
  END
 END x_q[128]
 PIN x_q[129]
  DIRECTION OUTPUT ;
  USE SIGNAL ;
  PORT
   LAYER M5 ;
   RECT 44.784 0.000 44.808 0.084 ;
  END
 END x_q[129]
 PIN x_q[130]
  DIRECTION OUTPUT ;
  USE SIGNAL ;
  PORT
   LAYER M5 ;
   RECT 44.976 0.000 45.000 0.084 ;
  END
 END x_q[130]
 PIN x_q[131]
  DIRECTION OUTPUT ;
  USE SIGNAL ;
  PORT
   LAYER M5 ;
   RECT 45.168 0.000 45.192 0.084 ;
  END
 END x_q[131]
 PIN x_q[132]
  DIRECTION OUTPUT ;
  USE SIGNAL ;
  PORT
   LAYER M5 ;
   RECT 45.360 0.000 45.384 0.084 ;
  END
 END x_q[132]
 PIN x_q[133]
  DIRECTION OUTPUT ;
  USE SIGNAL ;
  PORT
   LAYER M5 ;
   RECT 45.552 0.000 45.576 0.084 ;
  END
 END x_q[133]
 PIN x_q[134]
  DIRECTION OUTPUT ;
  USE SIGNAL ;
  PORT
   LAYER M5 ;
   RECT 45.744 0.000 45.768 0.084 ;
  END
 END x_q[134]
 PIN x_q[135]
  DIRECTION OUTPUT ;
  USE SIGNAL ;
  PORT
   LAYER M5 ;
   RECT 45.936 0.000 45.960 0.084 ;
  END
 END x_q[135]
 PIN x_q[136]
  DIRECTION OUTPUT ;
  USE SIGNAL ;
  PORT
   LAYER M5 ;
   RECT 46.128 0.000 46.152 0.084 ;
  END
 END x_q[136]
 PIN x_q[137]
  DIRECTION OUTPUT ;
  USE SIGNAL ;
  PORT
   LAYER M5 ;
   RECT 46.320 0.000 46.344 0.084 ;
  END
 END x_q[137]
 PIN x_q[138]
  DIRECTION OUTPUT ;
  USE SIGNAL ;
  PORT
   LAYER M5 ;
   RECT 46.512 0.000 46.536 0.084 ;
  END
 END x_q[138]
 PIN x_q[139]
  DIRECTION OUTPUT ;
  USE SIGNAL ;
  PORT
   LAYER M5 ;
   RECT 46.704 0.000 46.728 0.084 ;
  END
 END x_q[139]
 PIN x_q[140]
  DIRECTION OUTPUT ;
  USE SIGNAL ;
  PORT
   LAYER M5 ;
   RECT 46.896 0.000 46.920 0.084 ;
  END
 END x_q[140]
 PIN x_q[141]
  DIRECTION OUTPUT ;
  USE SIGNAL ;
  PORT
   LAYER M5 ;
   RECT 47.088 0.000 47.112 0.084 ;
  END
 END x_q[141]
 PIN x_q[142]
  DIRECTION OUTPUT ;
  USE SIGNAL ;
  PORT
   LAYER M5 ;
   RECT 47.280 0.000 47.304 0.084 ;
  END
 END x_q[142]
 PIN x_q[143]
  DIRECTION OUTPUT ;
  USE SIGNAL ;
  PORT
   LAYER M5 ;
   RECT 47.472 0.000 47.496 0.084 ;
  END
 END x_q[143]
 PIN x_q[144]
  DIRECTION OUTPUT ;
  USE SIGNAL ;
  PORT
   LAYER M5 ;
   RECT 47.664 0.000 47.688 0.084 ;
  END
 END x_q[144]
 PIN x_q[145]
  DIRECTION OUTPUT ;
  USE SIGNAL ;
  PORT
   LAYER M5 ;
   RECT 47.856 0.000 47.880 0.084 ;
  END
 END x_q[145]
 PIN x_q[146]
  DIRECTION OUTPUT ;
  USE SIGNAL ;
  PORT
   LAYER M5 ;
   RECT 48.048 0.000 48.072 0.084 ;
  END
 END x_q[146]
 PIN x_q[147]
  DIRECTION OUTPUT ;
  USE SIGNAL ;
  PORT
   LAYER M5 ;
   RECT 48.240 0.000 48.264 0.084 ;
  END
 END x_q[147]
 PIN x_q[148]
  DIRECTION OUTPUT ;
  USE SIGNAL ;
  PORT
   LAYER M5 ;
   RECT 48.432 0.000 48.456 0.084 ;
  END
 END x_q[148]
 PIN x_q[149]
  DIRECTION OUTPUT ;
  USE SIGNAL ;
  PORT
   LAYER M5 ;
   RECT 48.624 0.000 48.648 0.084 ;
  END
 END x_q[149]
 PIN x_q[150]
  DIRECTION OUTPUT ;
  USE SIGNAL ;
  PORT
   LAYER M5 ;
   RECT 48.816 0.000 48.840 0.084 ;
  END
 END x_q[150]
 PIN x_q[151]
  DIRECTION OUTPUT ;
  USE SIGNAL ;
  PORT
   LAYER M5 ;
   RECT 49.008 0.000 49.032 0.084 ;
  END
 END x_q[151]
 PIN x_q[152]
  DIRECTION OUTPUT ;
  USE SIGNAL ;
  PORT
   LAYER M5 ;
   RECT 49.200 0.000 49.224 0.084 ;
  END
 END x_q[152]
 PIN x_q[153]
  DIRECTION OUTPUT ;
  USE SIGNAL ;
  PORT
   LAYER M5 ;
   RECT 49.392 0.000 49.416 0.084 ;
  END
 END x_q[153]
 PIN x_q[154]
  DIRECTION OUTPUT ;
  USE SIGNAL ;
  PORT
   LAYER M5 ;
   RECT 49.584 0.000 49.608 0.084 ;
  END
 END x_q[154]
 PIN x_q[155]
  DIRECTION OUTPUT ;
  USE SIGNAL ;
  PORT
   LAYER M5 ;
   RECT 49.776 0.000 49.800 0.084 ;
  END
 END x_q[155]
 PIN x_q[156]
  DIRECTION OUTPUT ;
  USE SIGNAL ;
  PORT
   LAYER M5 ;
   RECT 49.968 0.000 49.992 0.084 ;
  END
 END x_q[156]
 PIN x_q[157]
  DIRECTION OUTPUT ;
  USE SIGNAL ;
  PORT
   LAYER M5 ;
   RECT 50.160 0.000 50.184 0.084 ;
  END
 END x_q[157]
 PIN x_q[158]
  DIRECTION OUTPUT ;
  USE SIGNAL ;
  PORT
   LAYER M5 ;
   RECT 50.352 0.000 50.376 0.084 ;
  END
 END x_q[158]
 PIN x_q[159]
  DIRECTION OUTPUT ;
  USE SIGNAL ;
  PORT
   LAYER M5 ;
   RECT 50.544 0.000 50.568 0.084 ;
  END
 END x_q[159]
 PIN x_q[160]
  DIRECTION OUTPUT ;
  USE SIGNAL ;
  PORT
   LAYER M5 ;
   RECT 50.736 0.000 50.760 0.084 ;
  END
 END x_q[160]
 PIN x_q[161]
  DIRECTION OUTPUT ;
  USE SIGNAL ;
  PORT
   LAYER M5 ;
   RECT 50.928 0.000 50.952 0.084 ;
  END
 END x_q[161]
 PIN x_q[162]
  DIRECTION OUTPUT ;
  USE SIGNAL ;
  PORT
   LAYER M5 ;
   RECT 51.120 0.000 51.144 0.084 ;
  END
 END x_q[162]
 PIN x_q[163]
  DIRECTION OUTPUT ;
  USE SIGNAL ;
  PORT
   LAYER M5 ;
   RECT 51.312 0.000 51.336 0.084 ;
  END
 END x_q[163]
 PIN x_q[164]
  DIRECTION OUTPUT ;
  USE SIGNAL ;
  PORT
   LAYER M5 ;
   RECT 51.504 0.000 51.528 0.084 ;
  END
 END x_q[164]
 PIN x_q[165]
  DIRECTION OUTPUT ;
  USE SIGNAL ;
  PORT
   LAYER M5 ;
   RECT 51.696 0.000 51.720 0.084 ;
  END
 END x_q[165]
 PIN x_q[166]
  DIRECTION OUTPUT ;
  USE SIGNAL ;
  PORT
   LAYER M5 ;
   RECT 51.888 0.000 51.912 0.084 ;
  END
 END x_q[166]
 PIN x_q[167]
  DIRECTION OUTPUT ;
  USE SIGNAL ;
  PORT
   LAYER M5 ;
   RECT 52.080 0.000 52.104 0.084 ;
  END
 END x_q[167]
 PIN x_q[168]
  DIRECTION OUTPUT ;
  USE SIGNAL ;
  PORT
   LAYER M5 ;
   RECT 52.272 0.000 52.296 0.084 ;
  END
 END x_q[168]
 PIN x_q[169]
  DIRECTION OUTPUT ;
  USE SIGNAL ;
  PORT
   LAYER M5 ;
   RECT 52.464 0.000 52.488 0.084 ;
  END
 END x_q[169]
 PIN x_q[170]
  DIRECTION OUTPUT ;
  USE SIGNAL ;
  PORT
   LAYER M5 ;
   RECT 52.656 0.000 52.680 0.084 ;
  END
 END x_q[170]
 PIN x_q[171]
  DIRECTION OUTPUT ;
  USE SIGNAL ;
  PORT
   LAYER M5 ;
   RECT 52.848 0.000 52.872 0.084 ;
  END
 END x_q[171]
 PIN x_q[172]
  DIRECTION OUTPUT ;
  USE SIGNAL ;
  PORT
   LAYER M5 ;
   RECT 53.040 0.000 53.064 0.084 ;
  END
 END x_q[172]
 PIN x_q[173]
  DIRECTION OUTPUT ;
  USE SIGNAL ;
  PORT
   LAYER M5 ;
   RECT 53.232 0.000 53.256 0.084 ;
  END
 END x_q[173]
 PIN x_q[174]
  DIRECTION OUTPUT ;
  USE SIGNAL ;
  PORT
   LAYER M5 ;
   RECT 53.424 0.000 53.448 0.084 ;
  END
 END x_q[174]
 PIN x_q[175]
  DIRECTION OUTPUT ;
  USE SIGNAL ;
  PORT
   LAYER M5 ;
   RECT 53.616 0.000 53.640 0.084 ;
  END
 END x_q[175]
 PIN x_q[176]
  DIRECTION OUTPUT ;
  USE SIGNAL ;
  PORT
   LAYER M5 ;
   RECT 53.808 0.000 53.832 0.084 ;
  END
 END x_q[176]
 PIN x_q[177]
  DIRECTION OUTPUT ;
  USE SIGNAL ;
  PORT
   LAYER M5 ;
   RECT 54.000 0.000 54.024 0.084 ;
  END
 END x_q[177]
 PIN x_q[178]
  DIRECTION OUTPUT ;
  USE SIGNAL ;
  PORT
   LAYER M5 ;
   RECT 54.192 0.000 54.216 0.084 ;
  END
 END x_q[178]
 PIN x_q[179]
  DIRECTION OUTPUT ;
  USE SIGNAL ;
  PORT
   LAYER M5 ;
   RECT 54.384 0.000 54.408 0.084 ;
  END
 END x_q[179]
 PIN x_q[180]
  DIRECTION OUTPUT ;
  USE SIGNAL ;
  PORT
   LAYER M5 ;
   RECT 54.576 0.000 54.600 0.084 ;
  END
 END x_q[180]
 PIN x_q[181]
  DIRECTION OUTPUT ;
  USE SIGNAL ;
  PORT
   LAYER M5 ;
   RECT 54.768 0.000 54.792 0.084 ;
  END
 END x_q[181]
 PIN x_q[182]
  DIRECTION OUTPUT ;
  USE SIGNAL ;
  PORT
   LAYER M5 ;
   RECT 54.960 0.000 54.984 0.084 ;
  END
 END x_q[182]
 PIN x_q[183]
  DIRECTION OUTPUT ;
  USE SIGNAL ;
  PORT
   LAYER M5 ;
   RECT 55.152 0.000 55.176 0.084 ;
  END
 END x_q[183]
 PIN x_q[184]
  DIRECTION OUTPUT ;
  USE SIGNAL ;
  PORT
   LAYER M5 ;
   RECT 55.344 0.000 55.368 0.084 ;
  END
 END x_q[184]
 PIN x_q[185]
  DIRECTION OUTPUT ;
  USE SIGNAL ;
  PORT
   LAYER M5 ;
   RECT 55.536 0.000 55.560 0.084 ;
  END
 END x_q[185]
 PIN x_q[186]
  DIRECTION OUTPUT ;
  USE SIGNAL ;
  PORT
   LAYER M5 ;
   RECT 55.728 0.000 55.752 0.084 ;
  END
 END x_q[186]
 PIN x_q[187]
  DIRECTION OUTPUT ;
  USE SIGNAL ;
  PORT
   LAYER M5 ;
   RECT 55.920 0.000 55.944 0.084 ;
  END
 END x_q[187]
 PIN x_q[188]
  DIRECTION OUTPUT ;
  USE SIGNAL ;
  PORT
   LAYER M5 ;
   RECT 56.112 0.000 56.136 0.084 ;
  END
 END x_q[188]
 PIN x_q[189]
  DIRECTION OUTPUT ;
  USE SIGNAL ;
  PORT
   LAYER M5 ;
   RECT 56.304 0.000 56.328 0.084 ;
  END
 END x_q[189]
 PIN x_q[190]
  DIRECTION OUTPUT ;
  USE SIGNAL ;
  PORT
   LAYER M5 ;
   RECT 56.496 0.000 56.520 0.084 ;
  END
 END x_q[190]
 PIN x_q[191]
  DIRECTION OUTPUT ;
  USE SIGNAL ;
  PORT
   LAYER M5 ;
   RECT 56.688 0.000 56.712 0.084 ;
  END
 END x_q[191]
 PIN x_q[192]
  DIRECTION OUTPUT ;
  USE SIGNAL ;
  PORT
   LAYER M5 ;
   RECT 56.880 0.000 56.904 0.084 ;
  END
 END x_q[192]
 PIN x_q[193]
  DIRECTION OUTPUT ;
  USE SIGNAL ;
  PORT
   LAYER M5 ;
   RECT 57.072 0.000 57.096 0.084 ;
  END
 END x_q[193]
 PIN x_q[194]
  DIRECTION OUTPUT ;
  USE SIGNAL ;
  PORT
   LAYER M5 ;
   RECT 57.264 0.000 57.288 0.084 ;
  END
 END x_q[194]
 PIN x_q[195]
  DIRECTION OUTPUT ;
  USE SIGNAL ;
  PORT
   LAYER M5 ;
   RECT 57.456 0.000 57.480 0.084 ;
  END
 END x_q[195]
 PIN x_q[196]
  DIRECTION OUTPUT ;
  USE SIGNAL ;
  PORT
   LAYER M5 ;
   RECT 57.648 0.000 57.672 0.084 ;
  END
 END x_q[196]
 PIN x_q[197]
  DIRECTION OUTPUT ;
  USE SIGNAL ;
  PORT
   LAYER M5 ;
   RECT 57.840 0.000 57.864 0.084 ;
  END
 END x_q[197]
 PIN x_q[198]
  DIRECTION OUTPUT ;
  USE SIGNAL ;
  PORT
   LAYER M5 ;
   RECT 58.032 0.000 58.056 0.084 ;
  END
 END x_q[198]
 PIN x_q[199]
  DIRECTION OUTPUT ;
  USE SIGNAL ;
  PORT
   LAYER M5 ;
   RECT 58.224 0.000 58.248 0.084 ;
  END
 END x_q[199]
 PIN x_q[200]
  DIRECTION OUTPUT ;
  USE SIGNAL ;
  PORT
   LAYER M5 ;
   RECT 58.416 0.000 58.440 0.084 ;
  END
 END x_q[200]
 PIN x_q[201]
  DIRECTION OUTPUT ;
  USE SIGNAL ;
  PORT
   LAYER M5 ;
   RECT 58.608 0.000 58.632 0.084 ;
  END
 END x_q[201]
 PIN x_q[202]
  DIRECTION OUTPUT ;
  USE SIGNAL ;
  PORT
   LAYER M5 ;
   RECT 58.800 0.000 58.824 0.084 ;
  END
 END x_q[202]
 PIN x_q[203]
  DIRECTION OUTPUT ;
  USE SIGNAL ;
  PORT
   LAYER M5 ;
   RECT 58.992 0.000 59.016 0.084 ;
  END
 END x_q[203]
 PIN x_q[204]
  DIRECTION OUTPUT ;
  USE SIGNAL ;
  PORT
   LAYER M5 ;
   RECT 59.184 0.000 59.208 0.084 ;
  END
 END x_q[204]
 PIN x_q[205]
  DIRECTION OUTPUT ;
  USE SIGNAL ;
  PORT
   LAYER M5 ;
   RECT 59.376 0.000 59.400 0.084 ;
  END
 END x_q[205]
 PIN x_q[206]
  DIRECTION OUTPUT ;
  USE SIGNAL ;
  PORT
   LAYER M5 ;
   RECT 59.568 0.000 59.592 0.084 ;
  END
 END x_q[206]
 PIN x_q[207]
  DIRECTION OUTPUT ;
  USE SIGNAL ;
  PORT
   LAYER M5 ;
   RECT 59.760 0.000 59.784 0.084 ;
  END
 END x_q[207]
 PIN x_q[208]
  DIRECTION OUTPUT ;
  USE SIGNAL ;
  PORT
   LAYER M5 ;
   RECT 59.952 0.000 59.976 0.084 ;
  END
 END x_q[208]
 PIN x_q[209]
  DIRECTION OUTPUT ;
  USE SIGNAL ;
  PORT
   LAYER M5 ;
   RECT 60.144 0.000 60.168 0.084 ;
  END
 END x_q[209]
 PIN x_q[210]
  DIRECTION OUTPUT ;
  USE SIGNAL ;
  PORT
   LAYER M5 ;
   RECT 60.336 0.000 60.360 0.084 ;
  END
 END x_q[210]
 PIN x_q[211]
  DIRECTION OUTPUT ;
  USE SIGNAL ;
  PORT
   LAYER M5 ;
   RECT 60.528 0.000 60.552 0.084 ;
  END
 END x_q[211]
 PIN x_q[212]
  DIRECTION OUTPUT ;
  USE SIGNAL ;
  PORT
   LAYER M5 ;
   RECT 60.720 0.000 60.744 0.084 ;
  END
 END x_q[212]
 PIN x_q[213]
  DIRECTION OUTPUT ;
  USE SIGNAL ;
  PORT
   LAYER M5 ;
   RECT 60.912 0.000 60.936 0.084 ;
  END
 END x_q[213]
 PIN x_q[214]
  DIRECTION OUTPUT ;
  USE SIGNAL ;
  PORT
   LAYER M5 ;
   RECT 61.104 0.000 61.128 0.084 ;
  END
 END x_q[214]
 PIN x_q[215]
  DIRECTION OUTPUT ;
  USE SIGNAL ;
  PORT
   LAYER M5 ;
   RECT 61.296 0.000 61.320 0.084 ;
  END
 END x_q[215]
 PIN x_q[216]
  DIRECTION OUTPUT ;
  USE SIGNAL ;
  PORT
   LAYER M5 ;
   RECT 61.488 0.000 61.512 0.084 ;
  END
 END x_q[216]
 PIN x_q[217]
  DIRECTION OUTPUT ;
  USE SIGNAL ;
  PORT
   LAYER M5 ;
   RECT 61.680 0.000 61.704 0.084 ;
  END
 END x_q[217]
 PIN x_q[218]
  DIRECTION OUTPUT ;
  USE SIGNAL ;
  PORT
   LAYER M5 ;
   RECT 61.872 0.000 61.896 0.084 ;
  END
 END x_q[218]
 PIN x_q[219]
  DIRECTION OUTPUT ;
  USE SIGNAL ;
  PORT
   LAYER M5 ;
   RECT 62.064 0.000 62.088 0.084 ;
  END
 END x_q[219]
 PIN x_q[220]
  DIRECTION OUTPUT ;
  USE SIGNAL ;
  PORT
   LAYER M5 ;
   RECT 62.256 0.000 62.280 0.084 ;
  END
 END x_q[220]
 PIN x_q[221]
  DIRECTION OUTPUT ;
  USE SIGNAL ;
  PORT
   LAYER M5 ;
   RECT 62.448 0.000 62.472 0.084 ;
  END
 END x_q[221]
 PIN x_q[222]
  DIRECTION OUTPUT ;
  USE SIGNAL ;
  PORT
   LAYER M5 ;
   RECT 62.640 0.000 62.664 0.084 ;
  END
 END x_q[222]
 PIN x_q[223]
  DIRECTION OUTPUT ;
  USE SIGNAL ;
  PORT
   LAYER M5 ;
   RECT 62.832 0.000 62.856 0.084 ;
  END
 END x_q[223]
 PIN x_q[224]
  DIRECTION OUTPUT ;
  USE SIGNAL ;
  PORT
   LAYER M5 ;
   RECT 63.024 0.000 63.048 0.084 ;
  END
 END x_q[224]
 PIN x_q[225]
  DIRECTION OUTPUT ;
  USE SIGNAL ;
  PORT
   LAYER M5 ;
   RECT 63.216 0.000 63.240 0.084 ;
  END
 END x_q[225]
 PIN x_q[226]
  DIRECTION OUTPUT ;
  USE SIGNAL ;
  PORT
   LAYER M5 ;
   RECT 63.408 0.000 63.432 0.084 ;
  END
 END x_q[226]
 PIN x_q[227]
  DIRECTION OUTPUT ;
  USE SIGNAL ;
  PORT
   LAYER M5 ;
   RECT 63.600 0.000 63.624 0.084 ;
  END
 END x_q[227]
 PIN x_q[228]
  DIRECTION OUTPUT ;
  USE SIGNAL ;
  PORT
   LAYER M5 ;
   RECT 63.792 0.000 63.816 0.084 ;
  END
 END x_q[228]
 PIN x_q[229]
  DIRECTION OUTPUT ;
  USE SIGNAL ;
  PORT
   LAYER M5 ;
   RECT 63.984 0.000 64.008 0.084 ;
  END
 END x_q[229]
 PIN x_q[230]
  DIRECTION OUTPUT ;
  USE SIGNAL ;
  PORT
   LAYER M5 ;
   RECT 64.176 0.000 64.200 0.084 ;
  END
 END x_q[230]
 PIN x_q[231]
  DIRECTION OUTPUT ;
  USE SIGNAL ;
  PORT
   LAYER M5 ;
   RECT 64.368 0.000 64.392 0.084 ;
  END
 END x_q[231]
 PIN x_q[232]
  DIRECTION OUTPUT ;
  USE SIGNAL ;
  PORT
   LAYER M5 ;
   RECT 64.560 0.000 64.584 0.084 ;
  END
 END x_q[232]
 PIN x_q[233]
  DIRECTION OUTPUT ;
  USE SIGNAL ;
  PORT
   LAYER M5 ;
   RECT 64.752 0.000 64.776 0.084 ;
  END
 END x_q[233]
 PIN x_q[234]
  DIRECTION OUTPUT ;
  USE SIGNAL ;
  PORT
   LAYER M5 ;
   RECT 64.944 0.000 64.968 0.084 ;
  END
 END x_q[234]
 PIN x_q[235]
  DIRECTION OUTPUT ;
  USE SIGNAL ;
  PORT
   LAYER M5 ;
   RECT 65.136 0.000 65.160 0.084 ;
  END
 END x_q[235]
 PIN x_q[236]
  DIRECTION OUTPUT ;
  USE SIGNAL ;
  PORT
   LAYER M5 ;
   RECT 65.328 0.000 65.352 0.084 ;
  END
 END x_q[236]
 PIN x_q[237]
  DIRECTION OUTPUT ;
  USE SIGNAL ;
  PORT
   LAYER M5 ;
   RECT 65.520 0.000 65.544 0.084 ;
  END
 END x_q[237]
 PIN x_q[238]
  DIRECTION OUTPUT ;
  USE SIGNAL ;
  PORT
   LAYER M5 ;
   RECT 65.712 0.000 65.736 0.084 ;
  END
 END x_q[238]
 PIN x_q[239]
  DIRECTION OUTPUT ;
  USE SIGNAL ;
  PORT
   LAYER M5 ;
   RECT 65.904 0.000 65.928 0.084 ;
  END
 END x_q[239]
 PIN x_q[240]
  DIRECTION OUTPUT ;
  USE SIGNAL ;
  PORT
   LAYER M5 ;
   RECT 66.096 0.000 66.120 0.084 ;
  END
 END x_q[240]
 PIN x_q[241]
  DIRECTION OUTPUT ;
  USE SIGNAL ;
  PORT
   LAYER M5 ;
   RECT 66.288 0.000 66.312 0.084 ;
  END
 END x_q[241]
 PIN x_q[242]
  DIRECTION OUTPUT ;
  USE SIGNAL ;
  PORT
   LAYER M5 ;
   RECT 66.480 0.000 66.504 0.084 ;
  END
 END x_q[242]
 PIN x_q[243]
  DIRECTION OUTPUT ;
  USE SIGNAL ;
  PORT
   LAYER M5 ;
   RECT 66.672 0.000 66.696 0.084 ;
  END
 END x_q[243]
 PIN x_q[244]
  DIRECTION OUTPUT ;
  USE SIGNAL ;
  PORT
   LAYER M5 ;
   RECT 66.864 0.000 66.888 0.084 ;
  END
 END x_q[244]
 PIN x_q[245]
  DIRECTION OUTPUT ;
  USE SIGNAL ;
  PORT
   LAYER M5 ;
   RECT 67.056 0.000 67.080 0.084 ;
  END
 END x_q[245]
 PIN x_q[246]
  DIRECTION OUTPUT ;
  USE SIGNAL ;
  PORT
   LAYER M5 ;
   RECT 67.248 0.000 67.272 0.084 ;
  END
 END x_q[246]
 PIN x_q[247]
  DIRECTION OUTPUT ;
  USE SIGNAL ;
  PORT
   LAYER M5 ;
   RECT 67.440 0.000 67.464 0.084 ;
  END
 END x_q[247]
 PIN x_q[248]
  DIRECTION OUTPUT ;
  USE SIGNAL ;
  PORT
   LAYER M5 ;
   RECT 67.632 0.000 67.656 0.084 ;
  END
 END x_q[248]
 PIN x_q[249]
  DIRECTION OUTPUT ;
  USE SIGNAL ;
  PORT
   LAYER M5 ;
   RECT 67.824 0.000 67.848 0.084 ;
  END
 END x_q[249]
 PIN x_q[250]
  DIRECTION OUTPUT ;
  USE SIGNAL ;
  PORT
   LAYER M5 ;
   RECT 68.016 0.000 68.040 0.084 ;
  END
 END x_q[250]
 PIN x_q[251]
  DIRECTION OUTPUT ;
  USE SIGNAL ;
  PORT
   LAYER M5 ;
   RECT 68.208 0.000 68.232 0.084 ;
  END
 END x_q[251]
 PIN x_q[252]
  DIRECTION OUTPUT ;
  USE SIGNAL ;
  PORT
   LAYER M5 ;
   RECT 68.400 0.000 68.424 0.084 ;
  END
 END x_q[252]
 PIN x_q[253]
  DIRECTION OUTPUT ;
  USE SIGNAL ;
  PORT
   LAYER M5 ;
   RECT 68.592 0.000 68.616 0.084 ;
  END
 END x_q[253]
 PIN x_q[254]
  DIRECTION OUTPUT ;
  USE SIGNAL ;
  PORT
   LAYER M5 ;
   RECT 68.784 0.000 68.808 0.084 ;
  END
 END x_q[254]
 PIN x_q[255]
  DIRECTION OUTPUT ;
  USE SIGNAL ;
  PORT
   LAYER M5 ;
   RECT 68.976 0.000 69.000 0.084 ;
  END
 END x_q[255]
 PIN x_q[256]
  DIRECTION OUTPUT ;
  USE SIGNAL ;
  PORT
   LAYER M5 ;
   RECT 69.168 0.000 69.192 0.084 ;
  END
 END x_q[256]
 PIN x_q[257]
  DIRECTION OUTPUT ;
  USE SIGNAL ;
  PORT
   LAYER M5 ;
   RECT 69.360 0.000 69.384 0.084 ;
  END
 END x_q[257]
 PIN x_q[258]
  DIRECTION OUTPUT ;
  USE SIGNAL ;
  PORT
   LAYER M5 ;
   RECT 69.552 0.000 69.576 0.084 ;
  END
 END x_q[258]
 PIN x_q[259]
  DIRECTION OUTPUT ;
  USE SIGNAL ;
  PORT
   LAYER M5 ;
   RECT 69.744 0.000 69.768 0.084 ;
  END
 END x_q[259]
 PIN x_q[260]
  DIRECTION OUTPUT ;
  USE SIGNAL ;
  PORT
   LAYER M5 ;
   RECT 69.936 0.000 69.960 0.084 ;
  END
 END x_q[260]
 PIN x_q[261]
  DIRECTION OUTPUT ;
  USE SIGNAL ;
  PORT
   LAYER M5 ;
   RECT 70.128 0.000 70.152 0.084 ;
  END
 END x_q[261]
 PIN x_q[262]
  DIRECTION OUTPUT ;
  USE SIGNAL ;
  PORT
   LAYER M5 ;
   RECT 70.320 0.000 70.344 0.084 ;
  END
 END x_q[262]
 PIN x_q[263]
  DIRECTION OUTPUT ;
  USE SIGNAL ;
  PORT
   LAYER M5 ;
   RECT 70.512 0.000 70.536 0.084 ;
  END
 END x_q[263]
 PIN x_q[264]
  DIRECTION OUTPUT ;
  USE SIGNAL ;
  PORT
   LAYER M5 ;
   RECT 70.704 0.000 70.728 0.084 ;
  END
 END x_q[264]
 PIN x_q[265]
  DIRECTION OUTPUT ;
  USE SIGNAL ;
  PORT
   LAYER M5 ;
   RECT 70.896 0.000 70.920 0.084 ;
  END
 END x_q[265]
 PIN x_q[266]
  DIRECTION OUTPUT ;
  USE SIGNAL ;
  PORT
   LAYER M5 ;
   RECT 71.088 0.000 71.112 0.084 ;
  END
 END x_q[266]
 PIN x_q[267]
  DIRECTION OUTPUT ;
  USE SIGNAL ;
  PORT
   LAYER M5 ;
   RECT 71.280 0.000 71.304 0.084 ;
  END
 END x_q[267]
 PIN x_q[268]
  DIRECTION OUTPUT ;
  USE SIGNAL ;
  PORT
   LAYER M5 ;
   RECT 71.472 0.000 71.496 0.084 ;
  END
 END x_q[268]
 PIN x_q[269]
  DIRECTION OUTPUT ;
  USE SIGNAL ;
  PORT
   LAYER M5 ;
   RECT 71.664 0.000 71.688 0.084 ;
  END
 END x_q[269]
 PIN x_q[270]
  DIRECTION OUTPUT ;
  USE SIGNAL ;
  PORT
   LAYER M5 ;
   RECT 71.856 0.000 71.880 0.084 ;
  END
 END x_q[270]
 PIN x_q[271]
  DIRECTION OUTPUT ;
  USE SIGNAL ;
  PORT
   LAYER M5 ;
   RECT 72.048 0.000 72.072 0.084 ;
  END
 END x_q[271]
 PIN x_q[272]
  DIRECTION OUTPUT ;
  USE SIGNAL ;
  PORT
   LAYER M5 ;
   RECT 72.240 0.000 72.264 0.084 ;
  END
 END x_q[272]
 PIN x_q[273]
  DIRECTION OUTPUT ;
  USE SIGNAL ;
  PORT
   LAYER M5 ;
   RECT 72.432 0.000 72.456 0.084 ;
  END
 END x_q[273]
 PIN x_q[274]
  DIRECTION OUTPUT ;
  USE SIGNAL ;
  PORT
   LAYER M5 ;
   RECT 72.624 0.000 72.648 0.084 ;
  END
 END x_q[274]
 PIN x_q[275]
  DIRECTION OUTPUT ;
  USE SIGNAL ;
  PORT
   LAYER M5 ;
   RECT 72.816 0.000 72.840 0.084 ;
  END
 END x_q[275]
 PIN x_q[276]
  DIRECTION OUTPUT ;
  USE SIGNAL ;
  PORT
   LAYER M5 ;
   RECT 73.008 0.000 73.032 0.084 ;
  END
 END x_q[276]
 PIN x_q[277]
  DIRECTION OUTPUT ;
  USE SIGNAL ;
  PORT
   LAYER M5 ;
   RECT 73.200 0.000 73.224 0.084 ;
  END
 END x_q[277]
 PIN x_q[278]
  DIRECTION OUTPUT ;
  USE SIGNAL ;
  PORT
   LAYER M5 ;
   RECT 73.392 0.000 73.416 0.084 ;
  END
 END x_q[278]
 PIN x_q[279]
  DIRECTION OUTPUT ;
  USE SIGNAL ;
  PORT
   LAYER M5 ;
   RECT 73.584 0.000 73.608 0.084 ;
  END
 END x_q[279]
 PIN x_q[280]
  DIRECTION OUTPUT ;
  USE SIGNAL ;
  PORT
   LAYER M5 ;
   RECT 73.776 0.000 73.800 0.084 ;
  END
 END x_q[280]
 PIN x_q[281]
  DIRECTION OUTPUT ;
  USE SIGNAL ;
  PORT
   LAYER M5 ;
   RECT 73.968 0.000 73.992 0.084 ;
  END
 END x_q[281]
 PIN x_q[282]
  DIRECTION OUTPUT ;
  USE SIGNAL ;
  PORT
   LAYER M5 ;
   RECT 74.160 0.000 74.184 0.084 ;
  END
 END x_q[282]
 PIN x_q[283]
  DIRECTION OUTPUT ;
  USE SIGNAL ;
  PORT
   LAYER M5 ;
   RECT 74.352 0.000 74.376 0.084 ;
  END
 END x_q[283]
 PIN x_q[284]
  DIRECTION OUTPUT ;
  USE SIGNAL ;
  PORT
   LAYER M5 ;
   RECT 74.544 0.000 74.568 0.084 ;
  END
 END x_q[284]
 PIN x_q[285]
  DIRECTION OUTPUT ;
  USE SIGNAL ;
  PORT
   LAYER M5 ;
   RECT 74.736 0.000 74.760 0.084 ;
  END
 END x_q[285]
 PIN x_q[286]
  DIRECTION OUTPUT ;
  USE SIGNAL ;
  PORT
   LAYER M5 ;
   RECT 74.928 0.000 74.952 0.084 ;
  END
 END x_q[286]
 PIN x_q[287]
  DIRECTION OUTPUT ;
  USE SIGNAL ;
  PORT
   LAYER M5 ;
   RECT 75.120 0.000 75.144 0.084 ;
  END
 END x_q[287]
 PIN x_q[288]
  DIRECTION OUTPUT ;
  USE SIGNAL ;
  PORT
   LAYER M5 ;
   RECT 75.312 0.000 75.336 0.084 ;
  END
 END x_q[288]
 PIN x_q[289]
  DIRECTION OUTPUT ;
  USE SIGNAL ;
  PORT
   LAYER M5 ;
   RECT 75.504 0.000 75.528 0.084 ;
  END
 END x_q[289]
 PIN x_q[290]
  DIRECTION OUTPUT ;
  USE SIGNAL ;
  PORT
   LAYER M5 ;
   RECT 75.696 0.000 75.720 0.084 ;
  END
 END x_q[290]
 PIN x_q[291]
  DIRECTION OUTPUT ;
  USE SIGNAL ;
  PORT
   LAYER M5 ;
   RECT 75.888 0.000 75.912 0.084 ;
  END
 END x_q[291]
 PIN x_q[292]
  DIRECTION OUTPUT ;
  USE SIGNAL ;
  PORT
   LAYER M5 ;
   RECT 76.080 0.000 76.104 0.084 ;
  END
 END x_q[292]
 PIN x_q[293]
  DIRECTION OUTPUT ;
  USE SIGNAL ;
  PORT
   LAYER M5 ;
   RECT 76.272 0.000 76.296 0.084 ;
  END
 END x_q[293]
 PIN x_q[294]
  DIRECTION OUTPUT ;
  USE SIGNAL ;
  PORT
   LAYER M5 ;
   RECT 76.464 0.000 76.488 0.084 ;
  END
 END x_q[294]
 PIN x_q[295]
  DIRECTION OUTPUT ;
  USE SIGNAL ;
  PORT
   LAYER M5 ;
   RECT 76.656 0.000 76.680 0.084 ;
  END
 END x_q[295]
 PIN x_q[296]
  DIRECTION OUTPUT ;
  USE SIGNAL ;
  PORT
   LAYER M5 ;
   RECT 76.848 0.000 76.872 0.084 ;
  END
 END x_q[296]
 PIN x_q[297]
  DIRECTION OUTPUT ;
  USE SIGNAL ;
  PORT
   LAYER M5 ;
   RECT 77.040 0.000 77.064 0.084 ;
  END
 END x_q[297]
 PIN x_q[298]
  DIRECTION OUTPUT ;
  USE SIGNAL ;
  PORT
   LAYER M5 ;
   RECT 77.232 0.000 77.256 0.084 ;
  END
 END x_q[298]
 PIN x_q[299]
  DIRECTION OUTPUT ;
  USE SIGNAL ;
  PORT
   LAYER M5 ;
   RECT 77.424 0.000 77.448 0.084 ;
  END
 END x_q[299]
 PIN x_q[300]
  DIRECTION OUTPUT ;
  USE SIGNAL ;
  PORT
   LAYER M5 ;
   RECT 77.616 0.000 77.640 0.084 ;
  END
 END x_q[300]
 PIN x_q[301]
  DIRECTION OUTPUT ;
  USE SIGNAL ;
  PORT
   LAYER M5 ;
   RECT 77.808 0.000 77.832 0.084 ;
  END
 END x_q[301]
 PIN x_q[302]
  DIRECTION OUTPUT ;
  USE SIGNAL ;
  PORT
   LAYER M5 ;
   RECT 78.000 0.000 78.024 0.084 ;
  END
 END x_q[302]
 PIN x_q[303]
  DIRECTION OUTPUT ;
  USE SIGNAL ;
  PORT
   LAYER M5 ;
   RECT 78.192 0.000 78.216 0.084 ;
  END
 END x_q[303]
 PIN x_q[304]
  DIRECTION OUTPUT ;
  USE SIGNAL ;
  PORT
   LAYER M5 ;
   RECT 78.384 0.000 78.408 0.084 ;
  END
 END x_q[304]
 PIN x_q[305]
  DIRECTION OUTPUT ;
  USE SIGNAL ;
  PORT
   LAYER M5 ;
   RECT 78.576 0.000 78.600 0.084 ;
  END
 END x_q[305]
 PIN x_q[306]
  DIRECTION OUTPUT ;
  USE SIGNAL ;
  PORT
   LAYER M5 ;
   RECT 78.768 0.000 78.792 0.084 ;
  END
 END x_q[306]
 PIN x_q[307]
  DIRECTION OUTPUT ;
  USE SIGNAL ;
  PORT
   LAYER M5 ;
   RECT 78.960 0.000 78.984 0.084 ;
  END
 END x_q[307]
 PIN x_q[308]
  DIRECTION OUTPUT ;
  USE SIGNAL ;
  PORT
   LAYER M5 ;
   RECT 79.152 0.000 79.176 0.084 ;
  END
 END x_q[308]
 PIN x_q[309]
  DIRECTION OUTPUT ;
  USE SIGNAL ;
  PORT
   LAYER M5 ;
   RECT 79.344 0.000 79.368 0.084 ;
  END
 END x_q[309]
 PIN x_q[310]
  DIRECTION OUTPUT ;
  USE SIGNAL ;
  PORT
   LAYER M5 ;
   RECT 79.536 0.000 79.560 0.084 ;
  END
 END x_q[310]
 PIN x_q[311]
  DIRECTION OUTPUT ;
  USE SIGNAL ;
  PORT
   LAYER M5 ;
   RECT 79.728 0.000 79.752 0.084 ;
  END
 END x_q[311]
 PIN x_q[312]
  DIRECTION OUTPUT ;
  USE SIGNAL ;
  PORT
   LAYER M5 ;
   RECT 79.920 0.000 79.944 0.084 ;
  END
 END x_q[312]
 PIN x_q[313]
  DIRECTION OUTPUT ;
  USE SIGNAL ;
  PORT
   LAYER M5 ;
   RECT 80.112 0.000 80.136 0.084 ;
  END
 END x_q[313]
 PIN x_q[314]
  DIRECTION OUTPUT ;
  USE SIGNAL ;
  PORT
   LAYER M5 ;
   RECT 80.304 0.000 80.328 0.084 ;
  END
 END x_q[314]
 PIN x_q[315]
  DIRECTION OUTPUT ;
  USE SIGNAL ;
  PORT
   LAYER M5 ;
   RECT 80.496 0.000 80.520 0.084 ;
  END
 END x_q[315]
 PIN x_q[316]
  DIRECTION OUTPUT ;
  USE SIGNAL ;
  PORT
   LAYER M5 ;
   RECT 80.688 0.000 80.712 0.084 ;
  END
 END x_q[316]
 PIN x_q[317]
  DIRECTION OUTPUT ;
  USE SIGNAL ;
  PORT
   LAYER M5 ;
   RECT 80.880 0.000 80.904 0.084 ;
  END
 END x_q[317]
 PIN x_q[318]
  DIRECTION OUTPUT ;
  USE SIGNAL ;
  PORT
   LAYER M5 ;
   RECT 81.072 0.000 81.096 0.084 ;
  END
 END x_q[318]
 PIN x_q[319]
  DIRECTION OUTPUT ;
  USE SIGNAL ;
  PORT
   LAYER M5 ;
   RECT 81.264 0.000 81.288 0.084 ;
  END
 END x_q[319]
 PIN x_q[320]
  DIRECTION OUTPUT ;
  USE SIGNAL ;
  PORT
   LAYER M5 ;
   RECT 81.456 0.000 81.480 0.084 ;
  END
 END x_q[320]
 PIN x_q[321]
  DIRECTION OUTPUT ;
  USE SIGNAL ;
  PORT
   LAYER M5 ;
   RECT 81.648 0.000 81.672 0.084 ;
  END
 END x_q[321]
 PIN x_q[322]
  DIRECTION OUTPUT ;
  USE SIGNAL ;
  PORT
   LAYER M5 ;
   RECT 81.840 0.000 81.864 0.084 ;
  END
 END x_q[322]
 PIN x_q[323]
  DIRECTION OUTPUT ;
  USE SIGNAL ;
  PORT
   LAYER M5 ;
   RECT 82.032 0.000 82.056 0.084 ;
  END
 END x_q[323]
 PIN x_q[324]
  DIRECTION OUTPUT ;
  USE SIGNAL ;
  PORT
   LAYER M5 ;
   RECT 82.224 0.000 82.248 0.084 ;
  END
 END x_q[324]
 PIN x_q[325]
  DIRECTION OUTPUT ;
  USE SIGNAL ;
  PORT
   LAYER M5 ;
   RECT 82.416 0.000 82.440 0.084 ;
  END
 END x_q[325]
 PIN x_q[326]
  DIRECTION OUTPUT ;
  USE SIGNAL ;
  PORT
   LAYER M5 ;
   RECT 82.608 0.000 82.632 0.084 ;
  END
 END x_q[326]
 PIN x_q[327]
  DIRECTION OUTPUT ;
  USE SIGNAL ;
  PORT
   LAYER M5 ;
   RECT 82.800 0.000 82.824 0.084 ;
  END
 END x_q[327]
 PIN x_q[328]
  DIRECTION OUTPUT ;
  USE SIGNAL ;
  PORT
   LAYER M5 ;
   RECT 82.992 0.000 83.016 0.084 ;
  END
 END x_q[328]
 PIN x_q[329]
  DIRECTION OUTPUT ;
  USE SIGNAL ;
  PORT
   LAYER M5 ;
   RECT 83.184 0.000 83.208 0.084 ;
  END
 END x_q[329]
 PIN x_q[330]
  DIRECTION OUTPUT ;
  USE SIGNAL ;
  PORT
   LAYER M5 ;
   RECT 83.376 0.000 83.400 0.084 ;
  END
 END x_q[330]
 PIN x_q[331]
  DIRECTION OUTPUT ;
  USE SIGNAL ;
  PORT
   LAYER M5 ;
   RECT 83.568 0.000 83.592 0.084 ;
  END
 END x_q[331]
 PIN x_q[332]
  DIRECTION OUTPUT ;
  USE SIGNAL ;
  PORT
   LAYER M5 ;
   RECT 83.760 0.000 83.784 0.084 ;
  END
 END x_q[332]
 PIN x_q[333]
  DIRECTION OUTPUT ;
  USE SIGNAL ;
  PORT
   LAYER M5 ;
   RECT 83.952 0.000 83.976 0.084 ;
  END
 END x_q[333]
 PIN x_q[334]
  DIRECTION OUTPUT ;
  USE SIGNAL ;
  PORT
   LAYER M5 ;
   RECT 84.144 0.000 84.168 0.084 ;
  END
 END x_q[334]
 PIN x_q[335]
  DIRECTION OUTPUT ;
  USE SIGNAL ;
  PORT
   LAYER M5 ;
   RECT 84.336 0.000 84.360 0.084 ;
  END
 END x_q[335]
 PIN x_q[336]
  DIRECTION OUTPUT ;
  USE SIGNAL ;
  PORT
   LAYER M5 ;
   RECT 84.528 0.000 84.552 0.084 ;
  END
 END x_q[336]
 PIN x_q[337]
  DIRECTION OUTPUT ;
  USE SIGNAL ;
  PORT
   LAYER M5 ;
   RECT 84.720 0.000 84.744 0.084 ;
  END
 END x_q[337]
 PIN x_q[338]
  DIRECTION OUTPUT ;
  USE SIGNAL ;
  PORT
   LAYER M5 ;
   RECT 84.912 0.000 84.936 0.084 ;
  END
 END x_q[338]
 PIN x_q[339]
  DIRECTION OUTPUT ;
  USE SIGNAL ;
  PORT
   LAYER M5 ;
   RECT 85.104 0.000 85.128 0.084 ;
  END
 END x_q[339]
 PIN x_q[340]
  DIRECTION OUTPUT ;
  USE SIGNAL ;
  PORT
   LAYER M5 ;
   RECT 85.296 0.000 85.320 0.084 ;
  END
 END x_q[340]
 PIN x_q[341]
  DIRECTION OUTPUT ;
  USE SIGNAL ;
  PORT
   LAYER M5 ;
   RECT 85.488 0.000 85.512 0.084 ;
  END
 END x_q[341]
 PIN x_q[342]
  DIRECTION OUTPUT ;
  USE SIGNAL ;
  PORT
   LAYER M5 ;
   RECT 85.680 0.000 85.704 0.084 ;
  END
 END x_q[342]
 PIN x_q[343]
  DIRECTION OUTPUT ;
  USE SIGNAL ;
  PORT
   LAYER M5 ;
   RECT 85.872 0.000 85.896 0.084 ;
  END
 END x_q[343]
 PIN x_q[344]
  DIRECTION OUTPUT ;
  USE SIGNAL ;
  PORT
   LAYER M5 ;
   RECT 86.064 0.000 86.088 0.084 ;
  END
 END x_q[344]
 PIN x_q[345]
  DIRECTION OUTPUT ;
  USE SIGNAL ;
  PORT
   LAYER M5 ;
   RECT 86.256 0.000 86.280 0.084 ;
  END
 END x_q[345]
 PIN x_q[346]
  DIRECTION OUTPUT ;
  USE SIGNAL ;
  PORT
   LAYER M5 ;
   RECT 86.448 0.000 86.472 0.084 ;
  END
 END x_q[346]
 PIN x_q[347]
  DIRECTION OUTPUT ;
  USE SIGNAL ;
  PORT
   LAYER M5 ;
   RECT 86.640 0.000 86.664 0.084 ;
  END
 END x_q[347]
 PIN x_q[348]
  DIRECTION OUTPUT ;
  USE SIGNAL ;
  PORT
   LAYER M5 ;
   RECT 86.832 0.000 86.856 0.084 ;
  END
 END x_q[348]
 PIN x_q[349]
  DIRECTION OUTPUT ;
  USE SIGNAL ;
  PORT
   LAYER M5 ;
   RECT 87.024 0.000 87.048 0.084 ;
  END
 END x_q[349]
 PIN x_q[350]
  DIRECTION OUTPUT ;
  USE SIGNAL ;
  PORT
   LAYER M5 ;
   RECT 87.216 0.000 87.240 0.084 ;
  END
 END x_q[350]
 PIN x_q[351]
  DIRECTION OUTPUT ;
  USE SIGNAL ;
  PORT
   LAYER M5 ;
   RECT 87.408 0.000 87.432 0.084 ;
  END
 END x_q[351]
 PIN x_q[352]
  DIRECTION OUTPUT ;
  USE SIGNAL ;
  PORT
   LAYER M5 ;
   RECT 87.600 0.000 87.624 0.084 ;
  END
 END x_q[352]
 PIN x_q[353]
  DIRECTION OUTPUT ;
  USE SIGNAL ;
  PORT
   LAYER M5 ;
   RECT 87.792 0.000 87.816 0.084 ;
  END
 END x_q[353]
 PIN x_q[354]
  DIRECTION OUTPUT ;
  USE SIGNAL ;
  PORT
   LAYER M5 ;
   RECT 87.984 0.000 88.008 0.084 ;
  END
 END x_q[354]
 PIN x_q[355]
  DIRECTION OUTPUT ;
  USE SIGNAL ;
  PORT
   LAYER M5 ;
   RECT 88.176 0.000 88.200 0.084 ;
  END
 END x_q[355]
 PIN x_q[356]
  DIRECTION OUTPUT ;
  USE SIGNAL ;
  PORT
   LAYER M5 ;
   RECT 88.368 0.000 88.392 0.084 ;
  END
 END x_q[356]
 PIN x_q[357]
  DIRECTION OUTPUT ;
  USE SIGNAL ;
  PORT
   LAYER M5 ;
   RECT 88.560 0.000 88.584 0.084 ;
  END
 END x_q[357]
 PIN x_q[358]
  DIRECTION OUTPUT ;
  USE SIGNAL ;
  PORT
   LAYER M5 ;
   RECT 88.752 0.000 88.776 0.084 ;
  END
 END x_q[358]
 PIN x_q[359]
  DIRECTION OUTPUT ;
  USE SIGNAL ;
  PORT
   LAYER M5 ;
   RECT 88.944 0.000 88.968 0.084 ;
  END
 END x_q[359]
 PIN x_q[360]
  DIRECTION OUTPUT ;
  USE SIGNAL ;
  PORT
   LAYER M5 ;
   RECT 89.136 0.000 89.160 0.084 ;
  END
 END x_q[360]
 PIN x_q[361]
  DIRECTION OUTPUT ;
  USE SIGNAL ;
  PORT
   LAYER M5 ;
   RECT 89.328 0.000 89.352 0.084 ;
  END
 END x_q[361]
 PIN x_q[362]
  DIRECTION OUTPUT ;
  USE SIGNAL ;
  PORT
   LAYER M5 ;
   RECT 89.520 0.000 89.544 0.084 ;
  END
 END x_q[362]
 PIN x_q[363]
  DIRECTION OUTPUT ;
  USE SIGNAL ;
  PORT
   LAYER M5 ;
   RECT 89.712 0.000 89.736 0.084 ;
  END
 END x_q[363]
 PIN x_q[364]
  DIRECTION OUTPUT ;
  USE SIGNAL ;
  PORT
   LAYER M5 ;
   RECT 89.904 0.000 89.928 0.084 ;
  END
 END x_q[364]
 PIN x_q[365]
  DIRECTION OUTPUT ;
  USE SIGNAL ;
  PORT
   LAYER M5 ;
   RECT 90.096 0.000 90.120 0.084 ;
  END
 END x_q[365]
 PIN x_q[366]
  DIRECTION OUTPUT ;
  USE SIGNAL ;
  PORT
   LAYER M5 ;
   RECT 90.288 0.000 90.312 0.084 ;
  END
 END x_q[366]
 PIN x_q[367]
  DIRECTION OUTPUT ;
  USE SIGNAL ;
  PORT
   LAYER M5 ;
   RECT 90.480 0.000 90.504 0.084 ;
  END
 END x_q[367]
 PIN x_q[368]
  DIRECTION OUTPUT ;
  USE SIGNAL ;
  PORT
   LAYER M5 ;
   RECT 90.672 0.000 90.696 0.084 ;
  END
 END x_q[368]
 PIN x_q[369]
  DIRECTION OUTPUT ;
  USE SIGNAL ;
  PORT
   LAYER M5 ;
   RECT 90.864 0.000 90.888 0.084 ;
  END
 END x_q[369]
 PIN x_q[370]
  DIRECTION OUTPUT ;
  USE SIGNAL ;
  PORT
   LAYER M5 ;
   RECT 91.056 0.000 91.080 0.084 ;
  END
 END x_q[370]
 PIN x_q[371]
  DIRECTION OUTPUT ;
  USE SIGNAL ;
  PORT
   LAYER M5 ;
   RECT 91.248 0.000 91.272 0.084 ;
  END
 END x_q[371]
 PIN x_q[372]
  DIRECTION OUTPUT ;
  USE SIGNAL ;
  PORT
   LAYER M5 ;
   RECT 91.440 0.000 91.464 0.084 ;
  END
 END x_q[372]
 PIN x_q[373]
  DIRECTION OUTPUT ;
  USE SIGNAL ;
  PORT
   LAYER M5 ;
   RECT 91.632 0.000 91.656 0.084 ;
  END
 END x_q[373]
 PIN x_q[374]
  DIRECTION OUTPUT ;
  USE SIGNAL ;
  PORT
   LAYER M5 ;
   RECT 91.824 0.000 91.848 0.084 ;
  END
 END x_q[374]
 PIN x_q[375]
  DIRECTION OUTPUT ;
  USE SIGNAL ;
  PORT
   LAYER M5 ;
   RECT 92.016 0.000 92.040 0.084 ;
  END
 END x_q[375]
 PIN x_q[376]
  DIRECTION OUTPUT ;
  USE SIGNAL ;
  PORT
   LAYER M5 ;
   RECT 92.208 0.000 92.232 0.084 ;
  END
 END x_q[376]
 PIN x_q[377]
  DIRECTION OUTPUT ;
  USE SIGNAL ;
  PORT
   LAYER M5 ;
   RECT 92.400 0.000 92.424 0.084 ;
  END
 END x_q[377]
 PIN x_q[378]
  DIRECTION OUTPUT ;
  USE SIGNAL ;
  PORT
   LAYER M5 ;
   RECT 92.592 0.000 92.616 0.084 ;
  END
 END x_q[378]
 PIN x_q[379]
  DIRECTION OUTPUT ;
  USE SIGNAL ;
  PORT
   LAYER M5 ;
   RECT 92.784 0.000 92.808 0.084 ;
  END
 END x_q[379]
 PIN x_q[380]
  DIRECTION OUTPUT ;
  USE SIGNAL ;
  PORT
   LAYER M5 ;
   RECT 92.976 0.000 93.000 0.084 ;
  END
 END x_q[380]
 PIN x_q[381]
  DIRECTION OUTPUT ;
  USE SIGNAL ;
  PORT
   LAYER M5 ;
   RECT 93.168 0.000 93.192 0.084 ;
  END
 END x_q[381]
 PIN x_q[382]
  DIRECTION OUTPUT ;
  USE SIGNAL ;
  PORT
   LAYER M5 ;
   RECT 93.360 0.000 93.384 0.084 ;
  END
 END x_q[382]
 PIN x_q[383]
  DIRECTION OUTPUT ;
  USE SIGNAL ;
  PORT
   LAYER M5 ;
   RECT 93.552 0.000 93.576 0.084 ;
  END
 END x_q[383]
 PIN x_q[384]
  DIRECTION OUTPUT ;
  USE SIGNAL ;
  PORT
   LAYER M5 ;
   RECT 93.744 0.000 93.768 0.084 ;
  END
 END x_q[384]
 PIN x_q[385]
  DIRECTION OUTPUT ;
  USE SIGNAL ;
  PORT
   LAYER M5 ;
   RECT 93.936 0.000 93.960 0.084 ;
  END
 END x_q[385]
 PIN x_q[386]
  DIRECTION OUTPUT ;
  USE SIGNAL ;
  PORT
   LAYER M5 ;
   RECT 94.128 0.000 94.152 0.084 ;
  END
 END x_q[386]
 PIN x_q[387]
  DIRECTION OUTPUT ;
  USE SIGNAL ;
  PORT
   LAYER M5 ;
   RECT 94.320 0.000 94.344 0.084 ;
  END
 END x_q[387]
 PIN x_q[388]
  DIRECTION OUTPUT ;
  USE SIGNAL ;
  PORT
   LAYER M5 ;
   RECT 94.512 0.000 94.536 0.084 ;
  END
 END x_q[388]
 PIN x_q[389]
  DIRECTION OUTPUT ;
  USE SIGNAL ;
  PORT
   LAYER M5 ;
   RECT 94.704 0.000 94.728 0.084 ;
  END
 END x_q[389]
 PIN x_q[390]
  DIRECTION OUTPUT ;
  USE SIGNAL ;
  PORT
   LAYER M5 ;
   RECT 94.896 0.000 94.920 0.084 ;
  END
 END x_q[390]
 PIN x_q[391]
  DIRECTION OUTPUT ;
  USE SIGNAL ;
  PORT
   LAYER M5 ;
   RECT 95.088 0.000 95.112 0.084 ;
  END
 END x_q[391]
 PIN x_q[392]
  DIRECTION OUTPUT ;
  USE SIGNAL ;
  PORT
   LAYER M5 ;
   RECT 95.280 0.000 95.304 0.084 ;
  END
 END x_q[392]
 PIN x_q[393]
  DIRECTION OUTPUT ;
  USE SIGNAL ;
  PORT
   LAYER M5 ;
   RECT 95.472 0.000 95.496 0.084 ;
  END
 END x_q[393]
 PIN x_q[394]
  DIRECTION OUTPUT ;
  USE SIGNAL ;
  PORT
   LAYER M5 ;
   RECT 95.664 0.000 95.688 0.084 ;
  END
 END x_q[394]
 PIN x_q[395]
  DIRECTION OUTPUT ;
  USE SIGNAL ;
  PORT
   LAYER M5 ;
   RECT 95.856 0.000 95.880 0.084 ;
  END
 END x_q[395]
 PIN x_q[396]
  DIRECTION OUTPUT ;
  USE SIGNAL ;
  PORT
   LAYER M5 ;
   RECT 96.048 0.000 96.072 0.084 ;
  END
 END x_q[396]
 PIN x_q[397]
  DIRECTION OUTPUT ;
  USE SIGNAL ;
  PORT
   LAYER M5 ;
   RECT 96.240 0.000 96.264 0.084 ;
  END
 END x_q[397]
 PIN x_q[398]
  DIRECTION OUTPUT ;
  USE SIGNAL ;
  PORT
   LAYER M5 ;
   RECT 96.432 0.000 96.456 0.084 ;
  END
 END x_q[398]
 PIN x_q[399]
  DIRECTION OUTPUT ;
  USE SIGNAL ;
  PORT
   LAYER M5 ;
   RECT 96.624 0.000 96.648 0.084 ;
  END
 END x_q[399]
 PIN x_q[400]
  DIRECTION OUTPUT ;
  USE SIGNAL ;
  PORT
   LAYER M5 ;
   RECT 96.816 0.000 96.840 0.084 ;
  END
 END x_q[400]
 PIN x_q[401]
  DIRECTION OUTPUT ;
  USE SIGNAL ;
  PORT
   LAYER M5 ;
   RECT 97.008 0.000 97.032 0.084 ;
  END
 END x_q[401]
 PIN x_q[402]
  DIRECTION OUTPUT ;
  USE SIGNAL ;
  PORT
   LAYER M5 ;
   RECT 97.200 0.000 97.224 0.084 ;
  END
 END x_q[402]
 PIN x_q[403]
  DIRECTION OUTPUT ;
  USE SIGNAL ;
  PORT
   LAYER M5 ;
   RECT 97.392 0.000 97.416 0.084 ;
  END
 END x_q[403]
 PIN x_q[404]
  DIRECTION OUTPUT ;
  USE SIGNAL ;
  PORT
   LAYER M5 ;
   RECT 97.584 0.000 97.608 0.084 ;
  END
 END x_q[404]
 PIN x_q[405]
  DIRECTION OUTPUT ;
  USE SIGNAL ;
  PORT
   LAYER M5 ;
   RECT 97.776 0.000 97.800 0.084 ;
  END
 END x_q[405]
 PIN x_q[406]
  DIRECTION OUTPUT ;
  USE SIGNAL ;
  PORT
   LAYER M5 ;
   RECT 97.968 0.000 97.992 0.084 ;
  END
 END x_q[406]
 PIN x_q[407]
  DIRECTION OUTPUT ;
  USE SIGNAL ;
  PORT
   LAYER M5 ;
   RECT 98.160 0.000 98.184 0.084 ;
  END
 END x_q[407]
 PIN x_q[408]
  DIRECTION OUTPUT ;
  USE SIGNAL ;
  PORT
   LAYER M5 ;
   RECT 98.352 0.000 98.376 0.084 ;
  END
 END x_q[408]
 PIN x_q[409]
  DIRECTION OUTPUT ;
  USE SIGNAL ;
  PORT
   LAYER M5 ;
   RECT 98.544 0.000 98.568 0.084 ;
  END
 END x_q[409]
 PIN x_q[410]
  DIRECTION OUTPUT ;
  USE SIGNAL ;
  PORT
   LAYER M5 ;
   RECT 98.736 0.000 98.760 0.084 ;
  END
 END x_q[410]
 PIN x_q[411]
  DIRECTION OUTPUT ;
  USE SIGNAL ;
  PORT
   LAYER M5 ;
   RECT 98.928 0.000 98.952 0.084 ;
  END
 END x_q[411]
 PIN x_q[412]
  DIRECTION OUTPUT ;
  USE SIGNAL ;
  PORT
   LAYER M5 ;
   RECT 99.120 0.000 99.144 0.084 ;
  END
 END x_q[412]
 PIN x_q[413]
  DIRECTION OUTPUT ;
  USE SIGNAL ;
  PORT
   LAYER M5 ;
   RECT 99.312 0.000 99.336 0.084 ;
  END
 END x_q[413]
 PIN x_q[414]
  DIRECTION OUTPUT ;
  USE SIGNAL ;
  PORT
   LAYER M5 ;
   RECT 99.504 0.000 99.528 0.084 ;
  END
 END x_q[414]
 PIN x_q[415]
  DIRECTION OUTPUT ;
  USE SIGNAL ;
  PORT
   LAYER M5 ;
   RECT 99.696 0.000 99.720 0.084 ;
  END
 END x_q[415]
 PIN x_q[416]
  DIRECTION OUTPUT ;
  USE SIGNAL ;
  PORT
   LAYER M5 ;
   RECT 99.888 0.000 99.912 0.084 ;
  END
 END x_q[416]
 PIN x_q[417]
  DIRECTION OUTPUT ;
  USE SIGNAL ;
  PORT
   LAYER M5 ;
   RECT 100.080 0.000 100.104 0.084 ;
  END
 END x_q[417]
 PIN x_q[418]
  DIRECTION OUTPUT ;
  USE SIGNAL ;
  PORT
   LAYER M5 ;
   RECT 100.272 0.000 100.296 0.084 ;
  END
 END x_q[418]
 PIN x_q[419]
  DIRECTION OUTPUT ;
  USE SIGNAL ;
  PORT
   LAYER M5 ;
   RECT 100.464 0.000 100.488 0.084 ;
  END
 END x_q[419]
 PIN x_q[420]
  DIRECTION OUTPUT ;
  USE SIGNAL ;
  PORT
   LAYER M5 ;
   RECT 100.656 0.000 100.680 0.084 ;
  END
 END x_q[420]
 PIN x_q[421]
  DIRECTION OUTPUT ;
  USE SIGNAL ;
  PORT
   LAYER M5 ;
   RECT 100.848 0.000 100.872 0.084 ;
  END
 END x_q[421]
 PIN x_q[422]
  DIRECTION OUTPUT ;
  USE SIGNAL ;
  PORT
   LAYER M5 ;
   RECT 101.040 0.000 101.064 0.084 ;
  END
 END x_q[422]
 PIN x_q[423]
  DIRECTION OUTPUT ;
  USE SIGNAL ;
  PORT
   LAYER M5 ;
   RECT 101.232 0.000 101.256 0.084 ;
  END
 END x_q[423]
 PIN x_q[424]
  DIRECTION OUTPUT ;
  USE SIGNAL ;
  PORT
   LAYER M5 ;
   RECT 101.424 0.000 101.448 0.084 ;
  END
 END x_q[424]
 PIN x_q[425]
  DIRECTION OUTPUT ;
  USE SIGNAL ;
  PORT
   LAYER M5 ;
   RECT 101.616 0.000 101.640 0.084 ;
  END
 END x_q[425]
 PIN x_q[426]
  DIRECTION OUTPUT ;
  USE SIGNAL ;
  PORT
   LAYER M5 ;
   RECT 101.808 0.000 101.832 0.084 ;
  END
 END x_q[426]
 PIN x_q[427]
  DIRECTION OUTPUT ;
  USE SIGNAL ;
  PORT
   LAYER M5 ;
   RECT 102.000 0.000 102.024 0.084 ;
  END
 END x_q[427]
 PIN x_q[428]
  DIRECTION OUTPUT ;
  USE SIGNAL ;
  PORT
   LAYER M5 ;
   RECT 102.192 0.000 102.216 0.084 ;
  END
 END x_q[428]
 PIN x_q[429]
  DIRECTION OUTPUT ;
  USE SIGNAL ;
  PORT
   LAYER M5 ;
   RECT 102.384 0.000 102.408 0.084 ;
  END
 END x_q[429]
 PIN x_q[430]
  DIRECTION OUTPUT ;
  USE SIGNAL ;
  PORT
   LAYER M5 ;
   RECT 102.576 0.000 102.600 0.084 ;
  END
 END x_q[430]
 PIN x_q[431]
  DIRECTION OUTPUT ;
  USE SIGNAL ;
  PORT
   LAYER M5 ;
   RECT 102.768 0.000 102.792 0.084 ;
  END
 END x_q[431]
 PIN x_q[432]
  DIRECTION OUTPUT ;
  USE SIGNAL ;
  PORT
   LAYER M5 ;
   RECT 102.960 0.000 102.984 0.084 ;
  END
 END x_q[432]
 PIN x_q[433]
  DIRECTION OUTPUT ;
  USE SIGNAL ;
  PORT
   LAYER M5 ;
   RECT 103.152 0.000 103.176 0.084 ;
  END
 END x_q[433]
 PIN x_q[434]
  DIRECTION OUTPUT ;
  USE SIGNAL ;
  PORT
   LAYER M5 ;
   RECT 103.344 0.000 103.368 0.084 ;
  END
 END x_q[434]
 PIN x_q[435]
  DIRECTION OUTPUT ;
  USE SIGNAL ;
  PORT
   LAYER M5 ;
   RECT 103.536 0.000 103.560 0.084 ;
  END
 END x_q[435]
 PIN x_q[436]
  DIRECTION OUTPUT ;
  USE SIGNAL ;
  PORT
   LAYER M5 ;
   RECT 103.728 0.000 103.752 0.084 ;
  END
 END x_q[436]
 PIN x_q[437]
  DIRECTION OUTPUT ;
  USE SIGNAL ;
  PORT
   LAYER M5 ;
   RECT 103.920 0.000 103.944 0.084 ;
  END
 END x_q[437]
 PIN x_q[438]
  DIRECTION OUTPUT ;
  USE SIGNAL ;
  PORT
   LAYER M5 ;
   RECT 104.112 0.000 104.136 0.084 ;
  END
 END x_q[438]
 PIN x_q[439]
  DIRECTION OUTPUT ;
  USE SIGNAL ;
  PORT
   LAYER M5 ;
   RECT 104.304 0.000 104.328 0.084 ;
  END
 END x_q[439]
 PIN x_q[440]
  DIRECTION OUTPUT ;
  USE SIGNAL ;
  PORT
   LAYER M5 ;
   RECT 104.496 0.000 104.520 0.084 ;
  END
 END x_q[440]
 PIN x_q[441]
  DIRECTION OUTPUT ;
  USE SIGNAL ;
  PORT
   LAYER M5 ;
   RECT 104.688 0.000 104.712 0.084 ;
  END
 END x_q[441]
 PIN x_q[442]
  DIRECTION OUTPUT ;
  USE SIGNAL ;
  PORT
   LAYER M5 ;
   RECT 104.880 0.000 104.904 0.084 ;
  END
 END x_q[442]
 PIN x_q[443]
  DIRECTION OUTPUT ;
  USE SIGNAL ;
  PORT
   LAYER M5 ;
   RECT 105.072 0.000 105.096 0.084 ;
  END
 END x_q[443]
 PIN x_q[444]
  DIRECTION OUTPUT ;
  USE SIGNAL ;
  PORT
   LAYER M5 ;
   RECT 105.264 0.000 105.288 0.084 ;
  END
 END x_q[444]
 PIN x_q[445]
  DIRECTION OUTPUT ;
  USE SIGNAL ;
  PORT
   LAYER M5 ;
   RECT 105.456 0.000 105.480 0.084 ;
  END
 END x_q[445]
 PIN x_q[446]
  DIRECTION OUTPUT ;
  USE SIGNAL ;
  PORT
   LAYER M5 ;
   RECT 105.648 0.000 105.672 0.084 ;
  END
 END x_q[446]
 PIN x_q[447]
  DIRECTION OUTPUT ;
  USE SIGNAL ;
  PORT
   LAYER M5 ;
   RECT 105.840 0.000 105.864 0.084 ;
  END
 END x_q[447]
 PIN x_q[448]
  DIRECTION OUTPUT ;
  USE SIGNAL ;
  PORT
   LAYER M5 ;
   RECT 106.032 0.000 106.056 0.084 ;
  END
 END x_q[448]
 PIN x_q[449]
  DIRECTION OUTPUT ;
  USE SIGNAL ;
  PORT
   LAYER M5 ;
   RECT 106.224 0.000 106.248 0.084 ;
  END
 END x_q[449]
 PIN x_q[450]
  DIRECTION OUTPUT ;
  USE SIGNAL ;
  PORT
   LAYER M5 ;
   RECT 106.416 0.000 106.440 0.084 ;
  END
 END x_q[450]
 PIN x_q[451]
  DIRECTION OUTPUT ;
  USE SIGNAL ;
  PORT
   LAYER M5 ;
   RECT 106.608 0.000 106.632 0.084 ;
  END
 END x_q[451]
 PIN x_q[452]
  DIRECTION OUTPUT ;
  USE SIGNAL ;
  PORT
   LAYER M5 ;
   RECT 106.800 0.000 106.824 0.084 ;
  END
 END x_q[452]
 PIN x_q[453]
  DIRECTION OUTPUT ;
  USE SIGNAL ;
  PORT
   LAYER M5 ;
   RECT 106.992 0.000 107.016 0.084 ;
  END
 END x_q[453]
 PIN x_q[454]
  DIRECTION OUTPUT ;
  USE SIGNAL ;
  PORT
   LAYER M5 ;
   RECT 107.184 0.000 107.208 0.084 ;
  END
 END x_q[454]
 PIN x_q[455]
  DIRECTION OUTPUT ;
  USE SIGNAL ;
  PORT
   LAYER M5 ;
   RECT 107.376 0.000 107.400 0.084 ;
  END
 END x_q[455]
 PIN x_q[456]
  DIRECTION OUTPUT ;
  USE SIGNAL ;
  PORT
   LAYER M5 ;
   RECT 107.568 0.000 107.592 0.084 ;
  END
 END x_q[456]
 PIN x_q[457]
  DIRECTION OUTPUT ;
  USE SIGNAL ;
  PORT
   LAYER M5 ;
   RECT 107.760 0.000 107.784 0.084 ;
  END
 END x_q[457]
 PIN x_q[458]
  DIRECTION OUTPUT ;
  USE SIGNAL ;
  PORT
   LAYER M5 ;
   RECT 107.952 0.000 107.976 0.084 ;
  END
 END x_q[458]
 PIN x_q[459]
  DIRECTION OUTPUT ;
  USE SIGNAL ;
  PORT
   LAYER M5 ;
   RECT 108.144 0.000 108.168 0.084 ;
  END
 END x_q[459]
 PIN x_q[460]
  DIRECTION OUTPUT ;
  USE SIGNAL ;
  PORT
   LAYER M5 ;
   RECT 108.336 0.000 108.360 0.084 ;
  END
 END x_q[460]
 PIN x_q[461]
  DIRECTION OUTPUT ;
  USE SIGNAL ;
  PORT
   LAYER M5 ;
   RECT 108.528 0.000 108.552 0.084 ;
  END
 END x_q[461]
 PIN x_q[462]
  DIRECTION OUTPUT ;
  USE SIGNAL ;
  PORT
   LAYER M5 ;
   RECT 108.720 0.000 108.744 0.084 ;
  END
 END x_q[462]
 PIN x_q[463]
  DIRECTION OUTPUT ;
  USE SIGNAL ;
  PORT
   LAYER M5 ;
   RECT 108.912 0.000 108.936 0.084 ;
  END
 END x_q[463]
 PIN x_q[464]
  DIRECTION OUTPUT ;
  USE SIGNAL ;
  PORT
   LAYER M5 ;
   RECT 109.104 0.000 109.128 0.084 ;
  END
 END x_q[464]
 PIN x_q[465]
  DIRECTION OUTPUT ;
  USE SIGNAL ;
  PORT
   LAYER M5 ;
   RECT 109.296 0.000 109.320 0.084 ;
  END
 END x_q[465]
 PIN x_q[466]
  DIRECTION OUTPUT ;
  USE SIGNAL ;
  PORT
   LAYER M5 ;
   RECT 109.488 0.000 109.512 0.084 ;
  END
 END x_q[466]
 PIN x_q[467]
  DIRECTION OUTPUT ;
  USE SIGNAL ;
  PORT
   LAYER M5 ;
   RECT 109.680 0.000 109.704 0.084 ;
  END
 END x_q[467]
 PIN x_q[468]
  DIRECTION OUTPUT ;
  USE SIGNAL ;
  PORT
   LAYER M5 ;
   RECT 109.872 0.000 109.896 0.084 ;
  END
 END x_q[468]
 PIN x_q[469]
  DIRECTION OUTPUT ;
  USE SIGNAL ;
  PORT
   LAYER M5 ;
   RECT 110.064 0.000 110.088 0.084 ;
  END
 END x_q[469]
 PIN x_q[470]
  DIRECTION OUTPUT ;
  USE SIGNAL ;
  PORT
   LAYER M5 ;
   RECT 110.256 0.000 110.280 0.084 ;
  END
 END x_q[470]
 PIN x_q[471]
  DIRECTION OUTPUT ;
  USE SIGNAL ;
  PORT
   LAYER M5 ;
   RECT 110.448 0.000 110.472 0.084 ;
  END
 END x_q[471]
 PIN x_q[472]
  DIRECTION OUTPUT ;
  USE SIGNAL ;
  PORT
   LAYER M5 ;
   RECT 110.640 0.000 110.664 0.084 ;
  END
 END x_q[472]
 PIN x_q[473]
  DIRECTION OUTPUT ;
  USE SIGNAL ;
  PORT
   LAYER M5 ;
   RECT 110.832 0.000 110.856 0.084 ;
  END
 END x_q[473]
 PIN x_q[474]
  DIRECTION OUTPUT ;
  USE SIGNAL ;
  PORT
   LAYER M5 ;
   RECT 111.024 0.000 111.048 0.084 ;
  END
 END x_q[474]
 PIN x_q[475]
  DIRECTION OUTPUT ;
  USE SIGNAL ;
  PORT
   LAYER M5 ;
   RECT 111.216 0.000 111.240 0.084 ;
  END
 END x_q[475]
 PIN x_q[476]
  DIRECTION OUTPUT ;
  USE SIGNAL ;
  PORT
   LAYER M5 ;
   RECT 111.408 0.000 111.432 0.084 ;
  END
 END x_q[476]
 PIN x_q[477]
  DIRECTION OUTPUT ;
  USE SIGNAL ;
  PORT
   LAYER M5 ;
   RECT 111.600 0.000 111.624 0.084 ;
  END
 END x_q[477]
 PIN x_q[478]
  DIRECTION OUTPUT ;
  USE SIGNAL ;
  PORT
   LAYER M5 ;
   RECT 111.792 0.000 111.816 0.084 ;
  END
 END x_q[478]
 PIN x_q[479]
  DIRECTION OUTPUT ;
  USE SIGNAL ;
  PORT
   LAYER M5 ;
   RECT 111.984 0.000 112.008 0.084 ;
  END
 END x_q[479]
 PIN x_q[480]
  DIRECTION OUTPUT ;
  USE SIGNAL ;
  PORT
   LAYER M5 ;
   RECT 112.176 0.000 112.200 0.084 ;
  END
 END x_q[480]
 PIN x_q[481]
  DIRECTION OUTPUT ;
  USE SIGNAL ;
  PORT
   LAYER M5 ;
   RECT 112.368 0.000 112.392 0.084 ;
  END
 END x_q[481]
 PIN x_q[482]
  DIRECTION OUTPUT ;
  USE SIGNAL ;
  PORT
   LAYER M5 ;
   RECT 112.560 0.000 112.584 0.084 ;
  END
 END x_q[482]
 PIN x_q[483]
  DIRECTION OUTPUT ;
  USE SIGNAL ;
  PORT
   LAYER M5 ;
   RECT 112.752 0.000 112.776 0.084 ;
  END
 END x_q[483]
 PIN x_q[484]
  DIRECTION OUTPUT ;
  USE SIGNAL ;
  PORT
   LAYER M5 ;
   RECT 112.944 0.000 112.968 0.084 ;
  END
 END x_q[484]
 PIN x_q[485]
  DIRECTION OUTPUT ;
  USE SIGNAL ;
  PORT
   LAYER M5 ;
   RECT 113.136 0.000 113.160 0.084 ;
  END
 END x_q[485]
 PIN x_q[486]
  DIRECTION OUTPUT ;
  USE SIGNAL ;
  PORT
   LAYER M5 ;
   RECT 113.328 0.000 113.352 0.084 ;
  END
 END x_q[486]
 PIN x_q[487]
  DIRECTION OUTPUT ;
  USE SIGNAL ;
  PORT
   LAYER M5 ;
   RECT 113.520 0.000 113.544 0.084 ;
  END
 END x_q[487]
 PIN x_q[488]
  DIRECTION OUTPUT ;
  USE SIGNAL ;
  PORT
   LAYER M5 ;
   RECT 113.712 0.000 113.736 0.084 ;
  END
 END x_q[488]
 PIN x_q[489]
  DIRECTION OUTPUT ;
  USE SIGNAL ;
  PORT
   LAYER M5 ;
   RECT 113.904 0.000 113.928 0.084 ;
  END
 END x_q[489]
 PIN x_q[490]
  DIRECTION OUTPUT ;
  USE SIGNAL ;
  PORT
   LAYER M5 ;
   RECT 114.096 0.000 114.120 0.084 ;
  END
 END x_q[490]
 PIN x_q[491]
  DIRECTION OUTPUT ;
  USE SIGNAL ;
  PORT
   LAYER M5 ;
   RECT 114.288 0.000 114.312 0.084 ;
  END
 END x_q[491]
 PIN x_q[492]
  DIRECTION OUTPUT ;
  USE SIGNAL ;
  PORT
   LAYER M5 ;
   RECT 114.480 0.000 114.504 0.084 ;
  END
 END x_q[492]
 PIN x_q[493]
  DIRECTION OUTPUT ;
  USE SIGNAL ;
  PORT
   LAYER M5 ;
   RECT 114.672 0.000 114.696 0.084 ;
  END
 END x_q[493]
 PIN x_q[494]
  DIRECTION OUTPUT ;
  USE SIGNAL ;
  PORT
   LAYER M5 ;
   RECT 114.864 0.000 114.888 0.084 ;
  END
 END x_q[494]
 PIN x_q[495]
  DIRECTION OUTPUT ;
  USE SIGNAL ;
  PORT
   LAYER M5 ;
   RECT 115.056 0.000 115.080 0.084 ;
  END
 END x_q[495]
 PIN x_q[496]
  DIRECTION OUTPUT ;
  USE SIGNAL ;
  PORT
   LAYER M5 ;
   RECT 115.248 0.000 115.272 0.084 ;
  END
 END x_q[496]
 PIN x_q[497]
  DIRECTION OUTPUT ;
  USE SIGNAL ;
  PORT
   LAYER M5 ;
   RECT 115.440 0.000 115.464 0.084 ;
  END
 END x_q[497]
 PIN x_q[498]
  DIRECTION OUTPUT ;
  USE SIGNAL ;
  PORT
   LAYER M5 ;
   RECT 115.632 0.000 115.656 0.084 ;
  END
 END x_q[498]
 PIN x_q[499]
  DIRECTION OUTPUT ;
  USE SIGNAL ;
  PORT
   LAYER M5 ;
   RECT 115.824 0.000 115.848 0.084 ;
  END
 END x_q[499]
 PIN x_q[500]
  DIRECTION OUTPUT ;
  USE SIGNAL ;
  PORT
   LAYER M5 ;
   RECT 116.016 0.000 116.040 0.084 ;
  END
 END x_q[500]
 PIN x_q[501]
  DIRECTION OUTPUT ;
  USE SIGNAL ;
  PORT
   LAYER M5 ;
   RECT 116.208 0.000 116.232 0.084 ;
  END
 END x_q[501]
 PIN x_q[502]
  DIRECTION OUTPUT ;
  USE SIGNAL ;
  PORT
   LAYER M5 ;
   RECT 116.400 0.000 116.424 0.084 ;
  END
 END x_q[502]
 PIN x_q[503]
  DIRECTION OUTPUT ;
  USE SIGNAL ;
  PORT
   LAYER M5 ;
   RECT 116.592 0.000 116.616 0.084 ;
  END
 END x_q[503]
 PIN x_q[504]
  DIRECTION OUTPUT ;
  USE SIGNAL ;
  PORT
   LAYER M5 ;
   RECT 116.784 0.000 116.808 0.084 ;
  END
 END x_q[504]
 PIN x_q[505]
  DIRECTION OUTPUT ;
  USE SIGNAL ;
  PORT
   LAYER M5 ;
   RECT 116.976 0.000 117.000 0.084 ;
  END
 END x_q[505]
 PIN x_q[506]
  DIRECTION OUTPUT ;
  USE SIGNAL ;
  PORT
   LAYER M5 ;
   RECT 117.168 0.000 117.192 0.084 ;
  END
 END x_q[506]
 PIN x_q[507]
  DIRECTION OUTPUT ;
  USE SIGNAL ;
  PORT
   LAYER M5 ;
   RECT 117.360 0.000 117.384 0.084 ;
  END
 END x_q[507]
 PIN x_q[508]
  DIRECTION OUTPUT ;
  USE SIGNAL ;
  PORT
   LAYER M5 ;
   RECT 117.552 0.000 117.576 0.084 ;
  END
 END x_q[508]
 PIN x_q[509]
  DIRECTION OUTPUT ;
  USE SIGNAL ;
  PORT
   LAYER M5 ;
   RECT 117.744 0.000 117.768 0.084 ;
  END
 END x_q[509]
 PIN x_q[510]
  DIRECTION OUTPUT ;
  USE SIGNAL ;
  PORT
   LAYER M5 ;
   RECT 117.936 0.000 117.960 0.084 ;
  END
 END x_q[510]
 PIN x_q[511]
  DIRECTION OUTPUT ;
  USE SIGNAL ;
  PORT
   LAYER M5 ;
   RECT 118.128 0.000 118.152 0.084 ;
  END
 END x_q[511]
 PIN x_q[512]
  DIRECTION OUTPUT ;
  USE SIGNAL ;
  PORT
   LAYER M5 ;
   RECT 118.320 0.000 118.344 0.084 ;
  END
 END x_q[512]
 PIN x_q[513]
  DIRECTION OUTPUT ;
  USE SIGNAL ;
  PORT
   LAYER M5 ;
   RECT 118.512 0.000 118.536 0.084 ;
  END
 END x_q[513]
 PIN x_q[514]
  DIRECTION OUTPUT ;
  USE SIGNAL ;
  PORT
   LAYER M5 ;
   RECT 118.704 0.000 118.728 0.084 ;
  END
 END x_q[514]
 PIN x_q[515]
  DIRECTION OUTPUT ;
  USE SIGNAL ;
  PORT
   LAYER M5 ;
   RECT 118.896 0.000 118.920 0.084 ;
  END
 END x_q[515]
 PIN x_q[516]
  DIRECTION OUTPUT ;
  USE SIGNAL ;
  PORT
   LAYER M5 ;
   RECT 119.088 0.000 119.112 0.084 ;
  END
 END x_q[516]
 PIN x_q[517]
  DIRECTION OUTPUT ;
  USE SIGNAL ;
  PORT
   LAYER M5 ;
   RECT 119.280 0.000 119.304 0.084 ;
  END
 END x_q[517]
 PIN x_q[518]
  DIRECTION OUTPUT ;
  USE SIGNAL ;
  PORT
   LAYER M5 ;
   RECT 119.472 0.000 119.496 0.084 ;
  END
 END x_q[518]
 PIN x_q[519]
  DIRECTION OUTPUT ;
  USE SIGNAL ;
  PORT
   LAYER M5 ;
   RECT 119.664 0.000 119.688 0.084 ;
  END
 END x_q[519]
 PIN x_q[520]
  DIRECTION OUTPUT ;
  USE SIGNAL ;
  PORT
   LAYER M5 ;
   RECT 119.856 0.000 119.880 0.084 ;
  END
 END x_q[520]
 PIN x_q[521]
  DIRECTION OUTPUT ;
  USE SIGNAL ;
  PORT
   LAYER M5 ;
   RECT 120.048 0.000 120.072 0.084 ;
  END
 END x_q[521]
 PIN x_q[522]
  DIRECTION OUTPUT ;
  USE SIGNAL ;
  PORT
   LAYER M5 ;
   RECT 120.240 0.000 120.264 0.084 ;
  END
 END x_q[522]
 PIN x_q[523]
  DIRECTION OUTPUT ;
  USE SIGNAL ;
  PORT
   LAYER M5 ;
   RECT 120.432 0.000 120.456 0.084 ;
  END
 END x_q[523]
 PIN x_q[524]
  DIRECTION OUTPUT ;
  USE SIGNAL ;
  PORT
   LAYER M5 ;
   RECT 120.624 0.000 120.648 0.084 ;
  END
 END x_q[524]
 PIN x_q[525]
  DIRECTION OUTPUT ;
  USE SIGNAL ;
  PORT
   LAYER M5 ;
   RECT 120.816 0.000 120.840 0.084 ;
  END
 END x_q[525]
 PIN x_q[526]
  DIRECTION OUTPUT ;
  USE SIGNAL ;
  PORT
   LAYER M5 ;
   RECT 121.008 0.000 121.032 0.084 ;
  END
 END x_q[526]
 PIN x_q[527]
  DIRECTION OUTPUT ;
  USE SIGNAL ;
  PORT
   LAYER M5 ;
   RECT 121.200 0.000 121.224 0.084 ;
  END
 END x_q[527]
 PIN x_q[528]
  DIRECTION OUTPUT ;
  USE SIGNAL ;
  PORT
   LAYER M5 ;
   RECT 121.392 0.000 121.416 0.084 ;
  END
 END x_q[528]
 PIN x_q[529]
  DIRECTION OUTPUT ;
  USE SIGNAL ;
  PORT
   LAYER M5 ;
   RECT 121.584 0.000 121.608 0.084 ;
  END
 END x_q[529]
 PIN x_q[530]
  DIRECTION OUTPUT ;
  USE SIGNAL ;
  PORT
   LAYER M5 ;
   RECT 121.776 0.000 121.800 0.084 ;
  END
 END x_q[530]
 PIN x_q[531]
  DIRECTION OUTPUT ;
  USE SIGNAL ;
  PORT
   LAYER M5 ;
   RECT 121.968 0.000 121.992 0.084 ;
  END
 END x_q[531]
 PIN x_q[532]
  DIRECTION OUTPUT ;
  USE SIGNAL ;
  PORT
   LAYER M5 ;
   RECT 122.160 0.000 122.184 0.084 ;
  END
 END x_q[532]
 PIN x_q[533]
  DIRECTION OUTPUT ;
  USE SIGNAL ;
  PORT
   LAYER M5 ;
   RECT 122.352 0.000 122.376 0.084 ;
  END
 END x_q[533]
 PIN x_q[534]
  DIRECTION OUTPUT ;
  USE SIGNAL ;
  PORT
   LAYER M5 ;
   RECT 122.544 0.000 122.568 0.084 ;
  END
 END x_q[534]
 PIN x_q[535]
  DIRECTION OUTPUT ;
  USE SIGNAL ;
  PORT
   LAYER M5 ;
   RECT 122.736 0.000 122.760 0.084 ;
  END
 END x_q[535]
 PIN x_q[536]
  DIRECTION OUTPUT ;
  USE SIGNAL ;
  PORT
   LAYER M5 ;
   RECT 122.928 0.000 122.952 0.084 ;
  END
 END x_q[536]
 PIN x_q[537]
  DIRECTION OUTPUT ;
  USE SIGNAL ;
  PORT
   LAYER M5 ;
   RECT 123.120 0.000 123.144 0.084 ;
  END
 END x_q[537]
 PIN x_q[538]
  DIRECTION OUTPUT ;
  USE SIGNAL ;
  PORT
   LAYER M5 ;
   RECT 123.312 0.000 123.336 0.084 ;
  END
 END x_q[538]
 PIN x_q[539]
  DIRECTION OUTPUT ;
  USE SIGNAL ;
  PORT
   LAYER M5 ;
   RECT 123.504 0.000 123.528 0.084 ;
  END
 END x_q[539]
 PIN x_q[540]
  DIRECTION OUTPUT ;
  USE SIGNAL ;
  PORT
   LAYER M5 ;
   RECT 123.696 0.000 123.720 0.084 ;
  END
 END x_q[540]
 PIN x_q[541]
  DIRECTION OUTPUT ;
  USE SIGNAL ;
  PORT
   LAYER M5 ;
   RECT 123.888 0.000 123.912 0.084 ;
  END
 END x_q[541]
 PIN x_q[542]
  DIRECTION OUTPUT ;
  USE SIGNAL ;
  PORT
   LAYER M5 ;
   RECT 124.080 0.000 124.104 0.084 ;
  END
 END x_q[542]
 PIN x_q[543]
  DIRECTION OUTPUT ;
  USE SIGNAL ;
  PORT
   LAYER M5 ;
   RECT 124.272 0.000 124.296 0.084 ;
  END
 END x_q[543]
 PIN k_v[0]
  DIRECTION OUTPUT ;
  USE SIGNAL ;
  PORT
   LAYER M5 ;
   RECT 124.464 0.000 124.488 0.084 ;
  END
 END k_v[0]
 PIN k_v[1]
  DIRECTION OUTPUT ;
  USE SIGNAL ;
  PORT
   LAYER M5 ;
   RECT 124.656 0.000 124.680 0.084 ;
  END
 END k_v[1]
 PIN k_v[2]
  DIRECTION OUTPUT ;
  USE SIGNAL ;
  PORT
   LAYER M5 ;
   RECT 124.848 0.000 124.872 0.084 ;
  END
 END k_v[2]
 PIN k_v[3]
  DIRECTION OUTPUT ;
  USE SIGNAL ;
  PORT
   LAYER M5 ;
   RECT 125.040 0.000 125.064 0.084 ;
  END
 END k_v[3]
 PIN k_lo[0]
  DIRECTION OUTPUT ;
  USE SIGNAL ;
  PORT
   LAYER M5 ;
   RECT 125.232 0.000 125.256 0.084 ;
  END
 END k_lo[0]
 PIN k_lo[1]
  DIRECTION OUTPUT ;
  USE SIGNAL ;
  PORT
   LAYER M5 ;
   RECT 125.424 0.000 125.448 0.084 ;
  END
 END k_lo[1]
 PIN k_lo[2]
  DIRECTION OUTPUT ;
  USE SIGNAL ;
  PORT
   LAYER M5 ;
   RECT 125.616 0.000 125.640 0.084 ;
  END
 END k_lo[2]
 PIN k_lo[3]
  DIRECTION OUTPUT ;
  USE SIGNAL ;
  PORT
   LAYER M5 ;
   RECT 125.808 0.000 125.832 0.084 ;
  END
 END k_lo[3]
 PIN k_lo[4]
  DIRECTION OUTPUT ;
  USE SIGNAL ;
  PORT
   LAYER M5 ;
   RECT 126.000 0.000 126.024 0.084 ;
  END
 END k_lo[4]
 PIN k_lo[5]
  DIRECTION OUTPUT ;
  USE SIGNAL ;
  PORT
   LAYER M5 ;
   RECT 126.192 0.000 126.216 0.084 ;
  END
 END k_lo[5]
 PIN k_lo[6]
  DIRECTION OUTPUT ;
  USE SIGNAL ;
  PORT
   LAYER M5 ;
   RECT 126.384 0.000 126.408 0.084 ;
  END
 END k_lo[6]
 PIN k_lo[7]
  DIRECTION OUTPUT ;
  USE SIGNAL ;
  PORT
   LAYER M5 ;
   RECT 126.576 0.000 126.600 0.084 ;
  END
 END k_lo[7]
 PIN k_lo[8]
  DIRECTION OUTPUT ;
  USE SIGNAL ;
  PORT
   LAYER M5 ;
   RECT 126.768 0.000 126.792 0.084 ;
  END
 END k_lo[8]
 PIN k_lo[9]
  DIRECTION OUTPUT ;
  USE SIGNAL ;
  PORT
   LAYER M5 ;
   RECT 126.960 0.000 126.984 0.084 ;
  END
 END k_lo[9]
 PIN k_lo[10]
  DIRECTION OUTPUT ;
  USE SIGNAL ;
  PORT
   LAYER M5 ;
   RECT 127.152 0.000 127.176 0.084 ;
  END
 END k_lo[10]
 PIN k_lo[11]
  DIRECTION OUTPUT ;
  USE SIGNAL ;
  PORT
   LAYER M5 ;
   RECT 127.344 0.000 127.368 0.084 ;
  END
 END k_lo[11]
 PIN k_lo[12]
  DIRECTION OUTPUT ;
  USE SIGNAL ;
  PORT
   LAYER M5 ;
   RECT 127.536 0.000 127.560 0.084 ;
  END
 END k_lo[12]
 PIN k_lo[13]
  DIRECTION OUTPUT ;
  USE SIGNAL ;
  PORT
   LAYER M5 ;
   RECT 127.728 0.000 127.752 0.084 ;
  END
 END k_lo[13]
 PIN k_lo[14]
  DIRECTION OUTPUT ;
  USE SIGNAL ;
  PORT
   LAYER M5 ;
   RECT 127.920 0.000 127.944 0.084 ;
  END
 END k_lo[14]
 PIN k_lo[15]
  DIRECTION OUTPUT ;
  USE SIGNAL ;
  PORT
   LAYER M5 ;
   RECT 128.112 0.000 128.136 0.084 ;
  END
 END k_lo[15]
 PIN k_lo[16]
  DIRECTION OUTPUT ;
  USE SIGNAL ;
  PORT
   LAYER M5 ;
   RECT 128.304 0.000 128.328 0.084 ;
  END
 END k_lo[16]
 PIN k_lo[17]
  DIRECTION OUTPUT ;
  USE SIGNAL ;
  PORT
   LAYER M5 ;
   RECT 128.496 0.000 128.520 0.084 ;
  END
 END k_lo[17]
 PIN k_lo[18]
  DIRECTION OUTPUT ;
  USE SIGNAL ;
  PORT
   LAYER M5 ;
   RECT 128.688 0.000 128.712 0.084 ;
  END
 END k_lo[18]
 PIN k_lo[19]
  DIRECTION OUTPUT ;
  USE SIGNAL ;
  PORT
   LAYER M5 ;
   RECT 128.880 0.000 128.904 0.084 ;
  END
 END k_lo[19]
 PIN k_lo[20]
  DIRECTION OUTPUT ;
  USE SIGNAL ;
  PORT
   LAYER M5 ;
   RECT 129.072 0.000 129.096 0.084 ;
  END
 END k_lo[20]
 PIN k_lo[21]
  DIRECTION OUTPUT ;
  USE SIGNAL ;
  PORT
   LAYER M5 ;
   RECT 129.264 0.000 129.288 0.084 ;
  END
 END k_lo[21]
 PIN k_lo[22]
  DIRECTION OUTPUT ;
  USE SIGNAL ;
  PORT
   LAYER M5 ;
   RECT 129.456 0.000 129.480 0.084 ;
  END
 END k_lo[22]
 PIN k_lo[23]
  DIRECTION OUTPUT ;
  USE SIGNAL ;
  PORT
   LAYER M5 ;
   RECT 129.648 0.000 129.672 0.084 ;
  END
 END k_lo[23]
 PIN k_lo[24]
  DIRECTION OUTPUT ;
  USE SIGNAL ;
  PORT
   LAYER M5 ;
   RECT 129.840 0.000 129.864 0.084 ;
  END
 END k_lo[24]
 PIN k_lo[25]
  DIRECTION OUTPUT ;
  USE SIGNAL ;
  PORT
   LAYER M5 ;
   RECT 130.032 0.000 130.056 0.084 ;
  END
 END k_lo[25]
 PIN k_lo[26]
  DIRECTION OUTPUT ;
  USE SIGNAL ;
  PORT
   LAYER M5 ;
   RECT 130.224 0.000 130.248 0.084 ;
  END
 END k_lo[26]
 PIN k_lo[27]
  DIRECTION OUTPUT ;
  USE SIGNAL ;
  PORT
   LAYER M5 ;
   RECT 130.416 0.000 130.440 0.084 ;
  END
 END k_lo[27]
 PIN k_lo[28]
  DIRECTION OUTPUT ;
  USE SIGNAL ;
  PORT
   LAYER M5 ;
   RECT 130.608 0.000 130.632 0.084 ;
  END
 END k_lo[28]
 PIN k_lo[29]
  DIRECTION OUTPUT ;
  USE SIGNAL ;
  PORT
   LAYER M5 ;
   RECT 130.800 0.000 130.824 0.084 ;
  END
 END k_lo[29]
 PIN k_lo[30]
  DIRECTION OUTPUT ;
  USE SIGNAL ;
  PORT
   LAYER M5 ;
   RECT 130.992 0.000 131.016 0.084 ;
  END
 END k_lo[30]
 PIN k_lo[31]
  DIRECTION OUTPUT ;
  USE SIGNAL ;
  PORT
   LAYER M5 ;
   RECT 131.184 0.000 131.208 0.084 ;
  END
 END k_lo[31]
 PIN k_lo[32]
  DIRECTION OUTPUT ;
  USE SIGNAL ;
  PORT
   LAYER M5 ;
   RECT 131.376 0.000 131.400 0.084 ;
  END
 END k_lo[32]
 PIN k_lo[33]
  DIRECTION OUTPUT ;
  USE SIGNAL ;
  PORT
   LAYER M5 ;
   RECT 131.568 0.000 131.592 0.084 ;
  END
 END k_lo[33]
 PIN k_lo[34]
  DIRECTION OUTPUT ;
  USE SIGNAL ;
  PORT
   LAYER M5 ;
   RECT 131.760 0.000 131.784 0.084 ;
  END
 END k_lo[34]
 PIN k_lo[35]
  DIRECTION OUTPUT ;
  USE SIGNAL ;
  PORT
   LAYER M5 ;
   RECT 131.952 0.000 131.976 0.084 ;
  END
 END k_lo[35]
 PIN k_lo[36]
  DIRECTION OUTPUT ;
  USE SIGNAL ;
  PORT
   LAYER M5 ;
   RECT 132.144 0.000 132.168 0.084 ;
  END
 END k_lo[36]
 PIN k_lo[37]
  DIRECTION OUTPUT ;
  USE SIGNAL ;
  PORT
   LAYER M5 ;
   RECT 132.336 0.000 132.360 0.084 ;
  END
 END k_lo[37]
 PIN k_lo[38]
  DIRECTION OUTPUT ;
  USE SIGNAL ;
  PORT
   LAYER M5 ;
   RECT 132.528 0.000 132.552 0.084 ;
  END
 END k_lo[38]
 PIN k_lo[39]
  DIRECTION OUTPUT ;
  USE SIGNAL ;
  PORT
   LAYER M5 ;
   RECT 132.720 0.000 132.744 0.084 ;
  END
 END k_lo[39]
 PIN k_lo[40]
  DIRECTION OUTPUT ;
  USE SIGNAL ;
  PORT
   LAYER M5 ;
   RECT 132.912 0.000 132.936 0.084 ;
  END
 END k_lo[40]
 PIN k_lo[41]
  DIRECTION OUTPUT ;
  USE SIGNAL ;
  PORT
   LAYER M5 ;
   RECT 133.104 0.000 133.128 0.084 ;
  END
 END k_lo[41]
 PIN k_lo[42]
  DIRECTION OUTPUT ;
  USE SIGNAL ;
  PORT
   LAYER M5 ;
   RECT 133.296 0.000 133.320 0.084 ;
  END
 END k_lo[42]
 PIN k_lo[43]
  DIRECTION OUTPUT ;
  USE SIGNAL ;
  PORT
   LAYER M5 ;
   RECT 133.488 0.000 133.512 0.084 ;
  END
 END k_lo[43]
 PIN k_lo[44]
  DIRECTION OUTPUT ;
  USE SIGNAL ;
  PORT
   LAYER M5 ;
   RECT 133.680 0.000 133.704 0.084 ;
  END
 END k_lo[44]
 PIN k_lo[45]
  DIRECTION OUTPUT ;
  USE SIGNAL ;
  PORT
   LAYER M5 ;
   RECT 133.872 0.000 133.896 0.084 ;
  END
 END k_lo[45]
 PIN k_lo[46]
  DIRECTION OUTPUT ;
  USE SIGNAL ;
  PORT
   LAYER M5 ;
   RECT 134.064 0.000 134.088 0.084 ;
  END
 END k_lo[46]
 PIN k_lo[47]
  DIRECTION OUTPUT ;
  USE SIGNAL ;
  PORT
   LAYER M5 ;
   RECT 134.256 0.000 134.280 0.084 ;
  END
 END k_lo[47]
 PIN k_lo[48]
  DIRECTION OUTPUT ;
  USE SIGNAL ;
  PORT
   LAYER M5 ;
   RECT 134.448 0.000 134.472 0.084 ;
  END
 END k_lo[48]
 PIN k_lo[49]
  DIRECTION OUTPUT ;
  USE SIGNAL ;
  PORT
   LAYER M5 ;
   RECT 134.640 0.000 134.664 0.084 ;
  END
 END k_lo[49]
 PIN k_lo[50]
  DIRECTION OUTPUT ;
  USE SIGNAL ;
  PORT
   LAYER M5 ;
   RECT 134.832 0.000 134.856 0.084 ;
  END
 END k_lo[50]
 PIN k_lo[51]
  DIRECTION OUTPUT ;
  USE SIGNAL ;
  PORT
   LAYER M5 ;
   RECT 135.024 0.000 135.048 0.084 ;
  END
 END k_lo[51]
 PIN k_lo[52]
  DIRECTION OUTPUT ;
  USE SIGNAL ;
  PORT
   LAYER M5 ;
   RECT 135.216 0.000 135.240 0.084 ;
  END
 END k_lo[52]
 PIN k_lo[53]
  DIRECTION OUTPUT ;
  USE SIGNAL ;
  PORT
   LAYER M5 ;
   RECT 135.408 0.000 135.432 0.084 ;
  END
 END k_lo[53]
 PIN k_lo[54]
  DIRECTION OUTPUT ;
  USE SIGNAL ;
  PORT
   LAYER M5 ;
   RECT 135.600 0.000 135.624 0.084 ;
  END
 END k_lo[54]
 PIN k_lo[55]
  DIRECTION OUTPUT ;
  USE SIGNAL ;
  PORT
   LAYER M5 ;
   RECT 135.792 0.000 135.816 0.084 ;
  END
 END k_lo[55]
 PIN k_lo[56]
  DIRECTION OUTPUT ;
  USE SIGNAL ;
  PORT
   LAYER M5 ;
   RECT 135.984 0.000 136.008 0.084 ;
  END
 END k_lo[56]
 PIN k_lo[57]
  DIRECTION OUTPUT ;
  USE SIGNAL ;
  PORT
   LAYER M5 ;
   RECT 136.176 0.000 136.200 0.084 ;
  END
 END k_lo[57]
 PIN k_lo[58]
  DIRECTION OUTPUT ;
  USE SIGNAL ;
  PORT
   LAYER M5 ;
   RECT 136.368 0.000 136.392 0.084 ;
  END
 END k_lo[58]
 PIN k_lo[59]
  DIRECTION OUTPUT ;
  USE SIGNAL ;
  PORT
   LAYER M5 ;
   RECT 136.560 0.000 136.584 0.084 ;
  END
 END k_lo[59]
 PIN k_lo[60]
  DIRECTION OUTPUT ;
  USE SIGNAL ;
  PORT
   LAYER M5 ;
   RECT 136.752 0.000 136.776 0.084 ;
  END
 END k_lo[60]
 PIN k_lo[61]
  DIRECTION OUTPUT ;
  USE SIGNAL ;
  PORT
   LAYER M5 ;
   RECT 136.944 0.000 136.968 0.084 ;
  END
 END k_lo[61]
 PIN k_lo[62]
  DIRECTION OUTPUT ;
  USE SIGNAL ;
  PORT
   LAYER M5 ;
   RECT 137.136 0.000 137.160 0.084 ;
  END
 END k_lo[62]
 PIN k_lo[63]
  DIRECTION OUTPUT ;
  USE SIGNAL ;
  PORT
   LAYER M5 ;
   RECT 137.328 0.000 137.352 0.084 ;
  END
 END k_lo[63]
 PIN k_lo[64]
  DIRECTION OUTPUT ;
  USE SIGNAL ;
  PORT
   LAYER M5 ;
   RECT 137.520 0.000 137.544 0.084 ;
  END
 END k_lo[64]
 PIN k_lo[65]
  DIRECTION OUTPUT ;
  USE SIGNAL ;
  PORT
   LAYER M5 ;
   RECT 137.712 0.000 137.736 0.084 ;
  END
 END k_lo[65]
 PIN k_lo[66]
  DIRECTION OUTPUT ;
  USE SIGNAL ;
  PORT
   LAYER M5 ;
   RECT 137.904 0.000 137.928 0.084 ;
  END
 END k_lo[66]
 PIN k_lo[67]
  DIRECTION OUTPUT ;
  USE SIGNAL ;
  PORT
   LAYER M5 ;
   RECT 138.096 0.000 138.120 0.084 ;
  END
 END k_lo[67]
 PIN k_lo[68]
  DIRECTION OUTPUT ;
  USE SIGNAL ;
  PORT
   LAYER M5 ;
   RECT 138.288 0.000 138.312 0.084 ;
  END
 END k_lo[68]
 PIN k_lo[69]
  DIRECTION OUTPUT ;
  USE SIGNAL ;
  PORT
   LAYER M5 ;
   RECT 138.480 0.000 138.504 0.084 ;
  END
 END k_lo[69]
 PIN k_lo[70]
  DIRECTION OUTPUT ;
  USE SIGNAL ;
  PORT
   LAYER M5 ;
   RECT 138.672 0.000 138.696 0.084 ;
  END
 END k_lo[70]
 PIN k_lo[71]
  DIRECTION OUTPUT ;
  USE SIGNAL ;
  PORT
   LAYER M5 ;
   RECT 138.864 0.000 138.888 0.084 ;
  END
 END k_lo[71]
 PIN k_lo[72]
  DIRECTION OUTPUT ;
  USE SIGNAL ;
  PORT
   LAYER M5 ;
   RECT 139.056 0.000 139.080 0.084 ;
  END
 END k_lo[72]
 PIN k_lo[73]
  DIRECTION OUTPUT ;
  USE SIGNAL ;
  PORT
   LAYER M5 ;
   RECT 139.248 0.000 139.272 0.084 ;
  END
 END k_lo[73]
 PIN k_lo[74]
  DIRECTION OUTPUT ;
  USE SIGNAL ;
  PORT
   LAYER M5 ;
   RECT 139.440 0.000 139.464 0.084 ;
  END
 END k_lo[74]
 PIN k_lo[75]
  DIRECTION OUTPUT ;
  USE SIGNAL ;
  PORT
   LAYER M5 ;
   RECT 139.632 0.000 139.656 0.084 ;
  END
 END k_lo[75]
 PIN k_lo[76]
  DIRECTION OUTPUT ;
  USE SIGNAL ;
  PORT
   LAYER M5 ;
   RECT 139.824 0.000 139.848 0.084 ;
  END
 END k_lo[76]
 PIN k_lo[77]
  DIRECTION OUTPUT ;
  USE SIGNAL ;
  PORT
   LAYER M5 ;
   RECT 140.016 0.000 140.040 0.084 ;
  END
 END k_lo[77]
 PIN k_lo[78]
  DIRECTION OUTPUT ;
  USE SIGNAL ;
  PORT
   LAYER M5 ;
   RECT 140.208 0.000 140.232 0.084 ;
  END
 END k_lo[78]
 PIN k_lo[79]
  DIRECTION OUTPUT ;
  USE SIGNAL ;
  PORT
   LAYER M5 ;
   RECT 140.400 0.000 140.424 0.084 ;
  END
 END k_lo[79]
 PIN k_lo[80]
  DIRECTION OUTPUT ;
  USE SIGNAL ;
  PORT
   LAYER M5 ;
   RECT 140.592 0.000 140.616 0.084 ;
  END
 END k_lo[80]
 PIN k_lo[81]
  DIRECTION OUTPUT ;
  USE SIGNAL ;
  PORT
   LAYER M5 ;
   RECT 140.784 0.000 140.808 0.084 ;
  END
 END k_lo[81]
 PIN k_lo[82]
  DIRECTION OUTPUT ;
  USE SIGNAL ;
  PORT
   LAYER M5 ;
   RECT 140.976 0.000 141.000 0.084 ;
  END
 END k_lo[82]
 PIN k_lo[83]
  DIRECTION OUTPUT ;
  USE SIGNAL ;
  PORT
   LAYER M5 ;
   RECT 141.168 0.000 141.192 0.084 ;
  END
 END k_lo[83]
 PIN k_lo[84]
  DIRECTION OUTPUT ;
  USE SIGNAL ;
  PORT
   LAYER M5 ;
   RECT 141.360 0.000 141.384 0.084 ;
  END
 END k_lo[84]
 PIN k_lo[85]
  DIRECTION OUTPUT ;
  USE SIGNAL ;
  PORT
   LAYER M5 ;
   RECT 141.552 0.000 141.576 0.084 ;
  END
 END k_lo[85]
 PIN k_lo[86]
  DIRECTION OUTPUT ;
  USE SIGNAL ;
  PORT
   LAYER M5 ;
   RECT 141.744 0.000 141.768 0.084 ;
  END
 END k_lo[86]
 PIN k_lo[87]
  DIRECTION OUTPUT ;
  USE SIGNAL ;
  PORT
   LAYER M5 ;
   RECT 141.936 0.000 141.960 0.084 ;
  END
 END k_lo[87]
 PIN k_lo[88]
  DIRECTION OUTPUT ;
  USE SIGNAL ;
  PORT
   LAYER M5 ;
   RECT 142.128 0.000 142.152 0.084 ;
  END
 END k_lo[88]
 PIN k_lo[89]
  DIRECTION OUTPUT ;
  USE SIGNAL ;
  PORT
   LAYER M5 ;
   RECT 142.320 0.000 142.344 0.084 ;
  END
 END k_lo[89]
 PIN k_lo[90]
  DIRECTION OUTPUT ;
  USE SIGNAL ;
  PORT
   LAYER M5 ;
   RECT 142.512 0.000 142.536 0.084 ;
  END
 END k_lo[90]
 PIN k_lo[91]
  DIRECTION OUTPUT ;
  USE SIGNAL ;
  PORT
   LAYER M5 ;
   RECT 142.704 0.000 142.728 0.084 ;
  END
 END k_lo[91]
 PIN k_lo[92]
  DIRECTION OUTPUT ;
  USE SIGNAL ;
  PORT
   LAYER M5 ;
   RECT 142.896 0.000 142.920 0.084 ;
  END
 END k_lo[92]
 PIN k_lo[93]
  DIRECTION OUTPUT ;
  USE SIGNAL ;
  PORT
   LAYER M5 ;
   RECT 143.088 0.000 143.112 0.084 ;
  END
 END k_lo[93]
 PIN k_lo[94]
  DIRECTION OUTPUT ;
  USE SIGNAL ;
  PORT
   LAYER M5 ;
   RECT 143.280 0.000 143.304 0.084 ;
  END
 END k_lo[94]
 PIN k_lo[95]
  DIRECTION OUTPUT ;
  USE SIGNAL ;
  PORT
   LAYER M5 ;
   RECT 143.472 0.000 143.496 0.084 ;
  END
 END k_lo[95]
 PIN k_lo[96]
  DIRECTION OUTPUT ;
  USE SIGNAL ;
  PORT
   LAYER M5 ;
   RECT 143.664 0.000 143.688 0.084 ;
  END
 END k_lo[96]
 PIN k_lo[97]
  DIRECTION OUTPUT ;
  USE SIGNAL ;
  PORT
   LAYER M5 ;
   RECT 143.856 0.000 143.880 0.084 ;
  END
 END k_lo[97]
 PIN k_lo[98]
  DIRECTION OUTPUT ;
  USE SIGNAL ;
  PORT
   LAYER M5 ;
   RECT 144.048 0.000 144.072 0.084 ;
  END
 END k_lo[98]
 PIN k_lo[99]
  DIRECTION OUTPUT ;
  USE SIGNAL ;
  PORT
   LAYER M5 ;
   RECT 144.240 0.000 144.264 0.084 ;
  END
 END k_lo[99]
 PIN k_lo[100]
  DIRECTION OUTPUT ;
  USE SIGNAL ;
  PORT
   LAYER M5 ;
   RECT 144.432 0.000 144.456 0.084 ;
  END
 END k_lo[100]
 PIN k_lo[101]
  DIRECTION OUTPUT ;
  USE SIGNAL ;
  PORT
   LAYER M5 ;
   RECT 144.624 0.000 144.648 0.084 ;
  END
 END k_lo[101]
 PIN k_lo[102]
  DIRECTION OUTPUT ;
  USE SIGNAL ;
  PORT
   LAYER M5 ;
   RECT 144.816 0.000 144.840 0.084 ;
  END
 END k_lo[102]
 PIN k_lo[103]
  DIRECTION OUTPUT ;
  USE SIGNAL ;
  PORT
   LAYER M5 ;
   RECT 145.008 0.000 145.032 0.084 ;
  END
 END k_lo[103]
 PIN k_lo[104]
  DIRECTION OUTPUT ;
  USE SIGNAL ;
  PORT
   LAYER M5 ;
   RECT 145.200 0.000 145.224 0.084 ;
  END
 END k_lo[104]
 PIN k_lo[105]
  DIRECTION OUTPUT ;
  USE SIGNAL ;
  PORT
   LAYER M5 ;
   RECT 145.392 0.000 145.416 0.084 ;
  END
 END k_lo[105]
 PIN k_lo[106]
  DIRECTION OUTPUT ;
  USE SIGNAL ;
  PORT
   LAYER M5 ;
   RECT 145.584 0.000 145.608 0.084 ;
  END
 END k_lo[106]
 PIN k_lo[107]
  DIRECTION OUTPUT ;
  USE SIGNAL ;
  PORT
   LAYER M5 ;
   RECT 145.776 0.000 145.800 0.084 ;
  END
 END k_lo[107]
 PIN k_lo[108]
  DIRECTION OUTPUT ;
  USE SIGNAL ;
  PORT
   LAYER M5 ;
   RECT 145.968 0.000 145.992 0.084 ;
  END
 END k_lo[108]
 PIN k_lo[109]
  DIRECTION OUTPUT ;
  USE SIGNAL ;
  PORT
   LAYER M5 ;
   RECT 146.160 0.000 146.184 0.084 ;
  END
 END k_lo[109]
 PIN k_lo[110]
  DIRECTION OUTPUT ;
  USE SIGNAL ;
  PORT
   LAYER M5 ;
   RECT 146.352 0.000 146.376 0.084 ;
  END
 END k_lo[110]
 PIN k_lo[111]
  DIRECTION OUTPUT ;
  USE SIGNAL ;
  PORT
   LAYER M5 ;
   RECT 146.544 0.000 146.568 0.084 ;
  END
 END k_lo[111]
 PIN k_lo[112]
  DIRECTION OUTPUT ;
  USE SIGNAL ;
  PORT
   LAYER M5 ;
   RECT 146.736 0.000 146.760 0.084 ;
  END
 END k_lo[112]
 PIN k_lo[113]
  DIRECTION OUTPUT ;
  USE SIGNAL ;
  PORT
   LAYER M5 ;
   RECT 146.928 0.000 146.952 0.084 ;
  END
 END k_lo[113]
 PIN k_lo[114]
  DIRECTION OUTPUT ;
  USE SIGNAL ;
  PORT
   LAYER M5 ;
   RECT 147.120 0.000 147.144 0.084 ;
  END
 END k_lo[114]
 PIN k_lo[115]
  DIRECTION OUTPUT ;
  USE SIGNAL ;
  PORT
   LAYER M5 ;
   RECT 147.312 0.000 147.336 0.084 ;
  END
 END k_lo[115]
 PIN k_lo[116]
  DIRECTION OUTPUT ;
  USE SIGNAL ;
  PORT
   LAYER M5 ;
   RECT 147.504 0.000 147.528 0.084 ;
  END
 END k_lo[116]
 PIN k_lo[117]
  DIRECTION OUTPUT ;
  USE SIGNAL ;
  PORT
   LAYER M5 ;
   RECT 147.696 0.000 147.720 0.084 ;
  END
 END k_lo[117]
 PIN k_lo[118]
  DIRECTION OUTPUT ;
  USE SIGNAL ;
  PORT
   LAYER M5 ;
   RECT 147.888 0.000 147.912 0.084 ;
  END
 END k_lo[118]
 PIN k_lo[119]
  DIRECTION OUTPUT ;
  USE SIGNAL ;
  PORT
   LAYER M5 ;
   RECT 148.080 0.000 148.104 0.084 ;
  END
 END k_lo[119]
 PIN k_lo[120]
  DIRECTION OUTPUT ;
  USE SIGNAL ;
  PORT
   LAYER M5 ;
   RECT 148.272 0.000 148.296 0.084 ;
  END
 END k_lo[120]
 PIN k_lo[121]
  DIRECTION OUTPUT ;
  USE SIGNAL ;
  PORT
   LAYER M5 ;
   RECT 148.464 0.000 148.488 0.084 ;
  END
 END k_lo[121]
 PIN k_lo[122]
  DIRECTION OUTPUT ;
  USE SIGNAL ;
  PORT
   LAYER M5 ;
   RECT 148.656 0.000 148.680 0.084 ;
  END
 END k_lo[122]
 PIN k_lo[123]
  DIRECTION OUTPUT ;
  USE SIGNAL ;
  PORT
   LAYER M5 ;
   RECT 148.848 0.000 148.872 0.084 ;
  END
 END k_lo[123]
 PIN k_lo[124]
  DIRECTION OUTPUT ;
  USE SIGNAL ;
  PORT
   LAYER M5 ;
   RECT 149.040 0.000 149.064 0.084 ;
  END
 END k_lo[124]
 PIN k_lo[125]
  DIRECTION OUTPUT ;
  USE SIGNAL ;
  PORT
   LAYER M5 ;
   RECT 149.232 0.000 149.256 0.084 ;
  END
 END k_lo[125]
 PIN k_lo[126]
  DIRECTION OUTPUT ;
  USE SIGNAL ;
  PORT
   LAYER M5 ;
   RECT 149.424 0.000 149.448 0.084 ;
  END
 END k_lo[126]
 PIN k_lo[127]
  DIRECTION OUTPUT ;
  USE SIGNAL ;
  PORT
   LAYER M5 ;
   RECT 149.616 0.000 149.640 0.084 ;
  END
 END k_lo[127]
 PIN k_lo[128]
  DIRECTION OUTPUT ;
  USE SIGNAL ;
  PORT
   LAYER M5 ;
   RECT 149.808 0.000 149.832 0.084 ;
  END
 END k_lo[128]
 PIN k_lo[129]
  DIRECTION OUTPUT ;
  USE SIGNAL ;
  PORT
   LAYER M5 ;
   RECT 150.000 0.000 150.024 0.084 ;
  END
 END k_lo[129]
 PIN k_lo[130]
  DIRECTION OUTPUT ;
  USE SIGNAL ;
  PORT
   LAYER M5 ;
   RECT 150.192 0.000 150.216 0.084 ;
  END
 END k_lo[130]
 PIN k_lo[131]
  DIRECTION OUTPUT ;
  USE SIGNAL ;
  PORT
   LAYER M5 ;
   RECT 150.384 0.000 150.408 0.084 ;
  END
 END k_lo[131]
 PIN k_lo[132]
  DIRECTION OUTPUT ;
  USE SIGNAL ;
  PORT
   LAYER M5 ;
   RECT 150.576 0.000 150.600 0.084 ;
  END
 END k_lo[132]
 PIN k_lo[133]
  DIRECTION OUTPUT ;
  USE SIGNAL ;
  PORT
   LAYER M5 ;
   RECT 150.768 0.000 150.792 0.084 ;
  END
 END k_lo[133]
 PIN k_lo[134]
  DIRECTION OUTPUT ;
  USE SIGNAL ;
  PORT
   LAYER M5 ;
   RECT 150.960 0.000 150.984 0.084 ;
  END
 END k_lo[134]
 PIN k_lo[135]
  DIRECTION OUTPUT ;
  USE SIGNAL ;
  PORT
   LAYER M5 ;
   RECT 151.152 0.000 151.176 0.084 ;
  END
 END k_lo[135]
 PIN k_lo[136]
  DIRECTION OUTPUT ;
  USE SIGNAL ;
  PORT
   LAYER M5 ;
   RECT 151.344 0.000 151.368 0.084 ;
  END
 END k_lo[136]
 PIN k_lo[137]
  DIRECTION OUTPUT ;
  USE SIGNAL ;
  PORT
   LAYER M5 ;
   RECT 151.536 0.000 151.560 0.084 ;
  END
 END k_lo[137]
 PIN k_lo[138]
  DIRECTION OUTPUT ;
  USE SIGNAL ;
  PORT
   LAYER M5 ;
   RECT 151.728 0.000 151.752 0.084 ;
  END
 END k_lo[138]
 PIN k_lo[139]
  DIRECTION OUTPUT ;
  USE SIGNAL ;
  PORT
   LAYER M5 ;
   RECT 151.920 0.000 151.944 0.084 ;
  END
 END k_lo[139]
 PIN k_lo[140]
  DIRECTION OUTPUT ;
  USE SIGNAL ;
  PORT
   LAYER M5 ;
   RECT 152.112 0.000 152.136 0.084 ;
  END
 END k_lo[140]
 PIN k_lo[141]
  DIRECTION OUTPUT ;
  USE SIGNAL ;
  PORT
   LAYER M5 ;
   RECT 152.304 0.000 152.328 0.084 ;
  END
 END k_lo[141]
 PIN k_lo[142]
  DIRECTION OUTPUT ;
  USE SIGNAL ;
  PORT
   LAYER M5 ;
   RECT 152.496 0.000 152.520 0.084 ;
  END
 END k_lo[142]
 PIN k_lo[143]
  DIRECTION OUTPUT ;
  USE SIGNAL ;
  PORT
   LAYER M5 ;
   RECT 152.688 0.000 152.712 0.084 ;
  END
 END k_lo[143]
 PIN k_lo[144]
  DIRECTION OUTPUT ;
  USE SIGNAL ;
  PORT
   LAYER M5 ;
   RECT 152.880 0.000 152.904 0.084 ;
  END
 END k_lo[144]
 PIN k_lo[145]
  DIRECTION OUTPUT ;
  USE SIGNAL ;
  PORT
   LAYER M5 ;
   RECT 153.072 0.000 153.096 0.084 ;
  END
 END k_lo[145]
 PIN k_lo[146]
  DIRECTION OUTPUT ;
  USE SIGNAL ;
  PORT
   LAYER M5 ;
   RECT 153.264 0.000 153.288 0.084 ;
  END
 END k_lo[146]
 PIN k_lo[147]
  DIRECTION OUTPUT ;
  USE SIGNAL ;
  PORT
   LAYER M5 ;
   RECT 153.456 0.000 153.480 0.084 ;
  END
 END k_lo[147]
 PIN k_lo[148]
  DIRECTION OUTPUT ;
  USE SIGNAL ;
  PORT
   LAYER M5 ;
   RECT 153.648 0.000 153.672 0.084 ;
  END
 END k_lo[148]
 PIN k_lo[149]
  DIRECTION OUTPUT ;
  USE SIGNAL ;
  PORT
   LAYER M5 ;
   RECT 153.840 0.000 153.864 0.084 ;
  END
 END k_lo[149]
 PIN k_lo[150]
  DIRECTION OUTPUT ;
  USE SIGNAL ;
  PORT
   LAYER M5 ;
   RECT 154.032 0.000 154.056 0.084 ;
  END
 END k_lo[150]
 PIN k_lo[151]
  DIRECTION OUTPUT ;
  USE SIGNAL ;
  PORT
   LAYER M5 ;
   RECT 154.224 0.000 154.248 0.084 ;
  END
 END k_lo[151]
 PIN k_lo[152]
  DIRECTION OUTPUT ;
  USE SIGNAL ;
  PORT
   LAYER M5 ;
   RECT 154.416 0.000 154.440 0.084 ;
  END
 END k_lo[152]
 PIN k_lo[153]
  DIRECTION OUTPUT ;
  USE SIGNAL ;
  PORT
   LAYER M5 ;
   RECT 154.608 0.000 154.632 0.084 ;
  END
 END k_lo[153]
 PIN k_lo[154]
  DIRECTION OUTPUT ;
  USE SIGNAL ;
  PORT
   LAYER M5 ;
   RECT 154.800 0.000 154.824 0.084 ;
  END
 END k_lo[154]
 PIN k_lo[155]
  DIRECTION OUTPUT ;
  USE SIGNAL ;
  PORT
   LAYER M5 ;
   RECT 154.992 0.000 155.016 0.084 ;
  END
 END k_lo[155]
 PIN k_lo[156]
  DIRECTION OUTPUT ;
  USE SIGNAL ;
  PORT
   LAYER M5 ;
   RECT 155.184 0.000 155.208 0.084 ;
  END
 END k_lo[156]
 PIN k_lo[157]
  DIRECTION OUTPUT ;
  USE SIGNAL ;
  PORT
   LAYER M5 ;
   RECT 155.376 0.000 155.400 0.084 ;
  END
 END k_lo[157]
 PIN k_lo[158]
  DIRECTION OUTPUT ;
  USE SIGNAL ;
  PORT
   LAYER M5 ;
   RECT 155.568 0.000 155.592 0.084 ;
  END
 END k_lo[158]
 PIN k_lo[159]
  DIRECTION OUTPUT ;
  USE SIGNAL ;
  PORT
   LAYER M5 ;
   RECT 155.760 0.000 155.784 0.084 ;
  END
 END k_lo[159]
 PIN k_lo[160]
  DIRECTION OUTPUT ;
  USE SIGNAL ;
  PORT
   LAYER M5 ;
   RECT 155.952 0.000 155.976 0.084 ;
  END
 END k_lo[160]
 PIN k_lo[161]
  DIRECTION OUTPUT ;
  USE SIGNAL ;
  PORT
   LAYER M5 ;
   RECT 156.144 0.000 156.168 0.084 ;
  END
 END k_lo[161]
 PIN k_lo[162]
  DIRECTION OUTPUT ;
  USE SIGNAL ;
  PORT
   LAYER M5 ;
   RECT 156.336 0.000 156.360 0.084 ;
  END
 END k_lo[162]
 PIN k_lo[163]
  DIRECTION OUTPUT ;
  USE SIGNAL ;
  PORT
   LAYER M5 ;
   RECT 156.528 0.000 156.552 0.084 ;
  END
 END k_lo[163]
 PIN k_lo[164]
  DIRECTION OUTPUT ;
  USE SIGNAL ;
  PORT
   LAYER M5 ;
   RECT 156.720 0.000 156.744 0.084 ;
  END
 END k_lo[164]
 PIN k_lo[165]
  DIRECTION OUTPUT ;
  USE SIGNAL ;
  PORT
   LAYER M5 ;
   RECT 156.912 0.000 156.936 0.084 ;
  END
 END k_lo[165]
 PIN k_lo[166]
  DIRECTION OUTPUT ;
  USE SIGNAL ;
  PORT
   LAYER M5 ;
   RECT 157.104 0.000 157.128 0.084 ;
  END
 END k_lo[166]
 PIN k_lo[167]
  DIRECTION OUTPUT ;
  USE SIGNAL ;
  PORT
   LAYER M5 ;
   RECT 157.296 0.000 157.320 0.084 ;
  END
 END k_lo[167]
 PIN k_lo[168]
  DIRECTION OUTPUT ;
  USE SIGNAL ;
  PORT
   LAYER M5 ;
   RECT 157.488 0.000 157.512 0.084 ;
  END
 END k_lo[168]
 PIN k_lo[169]
  DIRECTION OUTPUT ;
  USE SIGNAL ;
  PORT
   LAYER M5 ;
   RECT 157.680 0.000 157.704 0.084 ;
  END
 END k_lo[169]
 PIN k_lo[170]
  DIRECTION OUTPUT ;
  USE SIGNAL ;
  PORT
   LAYER M5 ;
   RECT 157.872 0.000 157.896 0.084 ;
  END
 END k_lo[170]
 PIN k_lo[171]
  DIRECTION OUTPUT ;
  USE SIGNAL ;
  PORT
   LAYER M5 ;
   RECT 158.064 0.000 158.088 0.084 ;
  END
 END k_lo[171]
 PIN k_lo[172]
  DIRECTION OUTPUT ;
  USE SIGNAL ;
  PORT
   LAYER M5 ;
   RECT 158.256 0.000 158.280 0.084 ;
  END
 END k_lo[172]
 PIN k_lo[173]
  DIRECTION OUTPUT ;
  USE SIGNAL ;
  PORT
   LAYER M5 ;
   RECT 158.448 0.000 158.472 0.084 ;
  END
 END k_lo[173]
 PIN k_lo[174]
  DIRECTION OUTPUT ;
  USE SIGNAL ;
  PORT
   LAYER M5 ;
   RECT 158.640 0.000 158.664 0.084 ;
  END
 END k_lo[174]
 PIN k_lo[175]
  DIRECTION OUTPUT ;
  USE SIGNAL ;
  PORT
   LAYER M5 ;
   RECT 158.832 0.000 158.856 0.084 ;
  END
 END k_lo[175]
 PIN k_lo[176]
  DIRECTION OUTPUT ;
  USE SIGNAL ;
  PORT
   LAYER M5 ;
   RECT 159.024 0.000 159.048 0.084 ;
  END
 END k_lo[176]
 PIN k_lo[177]
  DIRECTION OUTPUT ;
  USE SIGNAL ;
  PORT
   LAYER M5 ;
   RECT 159.216 0.000 159.240 0.084 ;
  END
 END k_lo[177]
 PIN k_lo[178]
  DIRECTION OUTPUT ;
  USE SIGNAL ;
  PORT
   LAYER M5 ;
   RECT 159.408 0.000 159.432 0.084 ;
  END
 END k_lo[178]
 PIN k_lo[179]
  DIRECTION OUTPUT ;
  USE SIGNAL ;
  PORT
   LAYER M5 ;
   RECT 159.600 0.000 159.624 0.084 ;
  END
 END k_lo[179]
 PIN k_lo[180]
  DIRECTION OUTPUT ;
  USE SIGNAL ;
  PORT
   LAYER M5 ;
   RECT 159.792 0.000 159.816 0.084 ;
  END
 END k_lo[180]
 PIN k_lo[181]
  DIRECTION OUTPUT ;
  USE SIGNAL ;
  PORT
   LAYER M5 ;
   RECT 159.984 0.000 160.008 0.084 ;
  END
 END k_lo[181]
 PIN k_lo[182]
  DIRECTION OUTPUT ;
  USE SIGNAL ;
  PORT
   LAYER M5 ;
   RECT 160.176 0.000 160.200 0.084 ;
  END
 END k_lo[182]
 PIN k_lo[183]
  DIRECTION OUTPUT ;
  USE SIGNAL ;
  PORT
   LAYER M5 ;
   RECT 160.368 0.000 160.392 0.084 ;
  END
 END k_lo[183]
 PIN k_lo[184]
  DIRECTION OUTPUT ;
  USE SIGNAL ;
  PORT
   LAYER M5 ;
   RECT 160.560 0.000 160.584 0.084 ;
  END
 END k_lo[184]
 PIN k_lo[185]
  DIRECTION OUTPUT ;
  USE SIGNAL ;
  PORT
   LAYER M5 ;
   RECT 160.752 0.000 160.776 0.084 ;
  END
 END k_lo[185]
 PIN k_lo[186]
  DIRECTION OUTPUT ;
  USE SIGNAL ;
  PORT
   LAYER M5 ;
   RECT 160.944 0.000 160.968 0.084 ;
  END
 END k_lo[186]
 PIN k_lo[187]
  DIRECTION OUTPUT ;
  USE SIGNAL ;
  PORT
   LAYER M5 ;
   RECT 161.136 0.000 161.160 0.084 ;
  END
 END k_lo[187]
 PIN k_lo[188]
  DIRECTION OUTPUT ;
  USE SIGNAL ;
  PORT
   LAYER M5 ;
   RECT 161.328 0.000 161.352 0.084 ;
  END
 END k_lo[188]
 PIN k_lo[189]
  DIRECTION OUTPUT ;
  USE SIGNAL ;
  PORT
   LAYER M5 ;
   RECT 161.520 0.000 161.544 0.084 ;
  END
 END k_lo[189]
 PIN k_lo[190]
  DIRECTION OUTPUT ;
  USE SIGNAL ;
  PORT
   LAYER M5 ;
   RECT 161.712 0.000 161.736 0.084 ;
  END
 END k_lo[190]
 PIN k_lo[191]
  DIRECTION OUTPUT ;
  USE SIGNAL ;
  PORT
   LAYER M5 ;
   RECT 161.904 0.000 161.928 0.084 ;
  END
 END k_lo[191]
 PIN k_lo[192]
  DIRECTION OUTPUT ;
  USE SIGNAL ;
  PORT
   LAYER M5 ;
   RECT 162.096 0.000 162.120 0.084 ;
  END
 END k_lo[192]
 PIN k_lo[193]
  DIRECTION OUTPUT ;
  USE SIGNAL ;
  PORT
   LAYER M5 ;
   RECT 162.288 0.000 162.312 0.084 ;
  END
 END k_lo[193]
 PIN k_lo[194]
  DIRECTION OUTPUT ;
  USE SIGNAL ;
  PORT
   LAYER M5 ;
   RECT 162.480 0.000 162.504 0.084 ;
  END
 END k_lo[194]
 PIN k_lo[195]
  DIRECTION OUTPUT ;
  USE SIGNAL ;
  PORT
   LAYER M5 ;
   RECT 162.672 0.000 162.696 0.084 ;
  END
 END k_lo[195]
 PIN k_lo[196]
  DIRECTION OUTPUT ;
  USE SIGNAL ;
  PORT
   LAYER M5 ;
   RECT 162.864 0.000 162.888 0.084 ;
  END
 END k_lo[196]
 PIN k_lo[197]
  DIRECTION OUTPUT ;
  USE SIGNAL ;
  PORT
   LAYER M5 ;
   RECT 163.056 0.000 163.080 0.084 ;
  END
 END k_lo[197]
 PIN k_lo[198]
  DIRECTION OUTPUT ;
  USE SIGNAL ;
  PORT
   LAYER M5 ;
   RECT 163.248 0.000 163.272 0.084 ;
  END
 END k_lo[198]
 PIN k_lo[199]
  DIRECTION OUTPUT ;
  USE SIGNAL ;
  PORT
   LAYER M5 ;
   RECT 163.440 0.000 163.464 0.084 ;
  END
 END k_lo[199]
 PIN k_lo[200]
  DIRECTION OUTPUT ;
  USE SIGNAL ;
  PORT
   LAYER M5 ;
   RECT 163.632 0.000 163.656 0.084 ;
  END
 END k_lo[200]
 PIN k_lo[201]
  DIRECTION OUTPUT ;
  USE SIGNAL ;
  PORT
   LAYER M5 ;
   RECT 163.824 0.000 163.848 0.084 ;
  END
 END k_lo[201]
 PIN k_lo[202]
  DIRECTION OUTPUT ;
  USE SIGNAL ;
  PORT
   LAYER M5 ;
   RECT 164.016 0.000 164.040 0.084 ;
  END
 END k_lo[202]
 PIN k_lo[203]
  DIRECTION OUTPUT ;
  USE SIGNAL ;
  PORT
   LAYER M5 ;
   RECT 164.208 0.000 164.232 0.084 ;
  END
 END k_lo[203]
 PIN k_lo[204]
  DIRECTION OUTPUT ;
  USE SIGNAL ;
  PORT
   LAYER M5 ;
   RECT 164.400 0.000 164.424 0.084 ;
  END
 END k_lo[204]
 PIN k_lo[205]
  DIRECTION OUTPUT ;
  USE SIGNAL ;
  PORT
   LAYER M5 ;
   RECT 164.592 0.000 164.616 0.084 ;
  END
 END k_lo[205]
 PIN k_lo[206]
  DIRECTION OUTPUT ;
  USE SIGNAL ;
  PORT
   LAYER M5 ;
   RECT 164.784 0.000 164.808 0.084 ;
  END
 END k_lo[206]
 PIN k_lo[207]
  DIRECTION OUTPUT ;
  USE SIGNAL ;
  PORT
   LAYER M5 ;
   RECT 164.976 0.000 165.000 0.084 ;
  END
 END k_lo[207]
 PIN k_lo[208]
  DIRECTION OUTPUT ;
  USE SIGNAL ;
  PORT
   LAYER M5 ;
   RECT 165.168 0.000 165.192 0.084 ;
  END
 END k_lo[208]
 PIN k_lo[209]
  DIRECTION OUTPUT ;
  USE SIGNAL ;
  PORT
   LAYER M5 ;
   RECT 165.360 0.000 165.384 0.084 ;
  END
 END k_lo[209]
 PIN k_lo[210]
  DIRECTION OUTPUT ;
  USE SIGNAL ;
  PORT
   LAYER M5 ;
   RECT 165.552 0.000 165.576 0.084 ;
  END
 END k_lo[210]
 PIN k_lo[211]
  DIRECTION OUTPUT ;
  USE SIGNAL ;
  PORT
   LAYER M5 ;
   RECT 165.744 0.000 165.768 0.084 ;
  END
 END k_lo[211]
 PIN k_lo[212]
  DIRECTION OUTPUT ;
  USE SIGNAL ;
  PORT
   LAYER M5 ;
   RECT 165.936 0.000 165.960 0.084 ;
  END
 END k_lo[212]
 PIN k_lo[213]
  DIRECTION OUTPUT ;
  USE SIGNAL ;
  PORT
   LAYER M5 ;
   RECT 166.128 0.000 166.152 0.084 ;
  END
 END k_lo[213]
 PIN k_lo[214]
  DIRECTION OUTPUT ;
  USE SIGNAL ;
  PORT
   LAYER M5 ;
   RECT 166.320 0.000 166.344 0.084 ;
  END
 END k_lo[214]
 PIN k_lo[215]
  DIRECTION OUTPUT ;
  USE SIGNAL ;
  PORT
   LAYER M5 ;
   RECT 166.512 0.000 166.536 0.084 ;
  END
 END k_lo[215]
 PIN k_lo[216]
  DIRECTION OUTPUT ;
  USE SIGNAL ;
  PORT
   LAYER M5 ;
   RECT 166.704 0.000 166.728 0.084 ;
  END
 END k_lo[216]
 PIN k_lo[217]
  DIRECTION OUTPUT ;
  USE SIGNAL ;
  PORT
   LAYER M5 ;
   RECT 166.896 0.000 166.920 0.084 ;
  END
 END k_lo[217]
 PIN k_lo[218]
  DIRECTION OUTPUT ;
  USE SIGNAL ;
  PORT
   LAYER M5 ;
   RECT 167.088 0.000 167.112 0.084 ;
  END
 END k_lo[218]
 PIN k_lo[219]
  DIRECTION OUTPUT ;
  USE SIGNAL ;
  PORT
   LAYER M5 ;
   RECT 167.280 0.000 167.304 0.084 ;
  END
 END k_lo[219]
 PIN k_lo[220]
  DIRECTION OUTPUT ;
  USE SIGNAL ;
  PORT
   LAYER M5 ;
   RECT 167.472 0.000 167.496 0.084 ;
  END
 END k_lo[220]
 PIN k_lo[221]
  DIRECTION OUTPUT ;
  USE SIGNAL ;
  PORT
   LAYER M5 ;
   RECT 167.664 0.000 167.688 0.084 ;
  END
 END k_lo[221]
 PIN k_lo[222]
  DIRECTION OUTPUT ;
  USE SIGNAL ;
  PORT
   LAYER M5 ;
   RECT 167.856 0.000 167.880 0.084 ;
  END
 END k_lo[222]
 PIN k_lo[223]
  DIRECTION OUTPUT ;
  USE SIGNAL ;
  PORT
   LAYER M5 ;
   RECT 168.048 0.000 168.072 0.084 ;
  END
 END k_lo[223]
 PIN k_lo[224]
  DIRECTION OUTPUT ;
  USE SIGNAL ;
  PORT
   LAYER M5 ;
   RECT 168.240 0.000 168.264 0.084 ;
  END
 END k_lo[224]
 PIN k_lo[225]
  DIRECTION OUTPUT ;
  USE SIGNAL ;
  PORT
   LAYER M5 ;
   RECT 168.432 0.000 168.456 0.084 ;
  END
 END k_lo[225]
 PIN k_lo[226]
  DIRECTION OUTPUT ;
  USE SIGNAL ;
  PORT
   LAYER M5 ;
   RECT 168.624 0.000 168.648 0.084 ;
  END
 END k_lo[226]
 PIN k_lo[227]
  DIRECTION OUTPUT ;
  USE SIGNAL ;
  PORT
   LAYER M5 ;
   RECT 168.816 0.000 168.840 0.084 ;
  END
 END k_lo[227]
 PIN k_lo[228]
  DIRECTION OUTPUT ;
  USE SIGNAL ;
  PORT
   LAYER M5 ;
   RECT 169.008 0.000 169.032 0.084 ;
  END
 END k_lo[228]
 PIN k_lo[229]
  DIRECTION OUTPUT ;
  USE SIGNAL ;
  PORT
   LAYER M5 ;
   RECT 169.200 0.000 169.224 0.084 ;
  END
 END k_lo[229]
 PIN k_lo[230]
  DIRECTION OUTPUT ;
  USE SIGNAL ;
  PORT
   LAYER M5 ;
   RECT 169.392 0.000 169.416 0.084 ;
  END
 END k_lo[230]
 PIN k_lo[231]
  DIRECTION OUTPUT ;
  USE SIGNAL ;
  PORT
   LAYER M5 ;
   RECT 169.584 0.000 169.608 0.084 ;
  END
 END k_lo[231]
 PIN k_lo[232]
  DIRECTION OUTPUT ;
  USE SIGNAL ;
  PORT
   LAYER M5 ;
   RECT 169.776 0.000 169.800 0.084 ;
  END
 END k_lo[232]
 PIN k_lo[233]
  DIRECTION OUTPUT ;
  USE SIGNAL ;
  PORT
   LAYER M5 ;
   RECT 169.968 0.000 169.992 0.084 ;
  END
 END k_lo[233]
 PIN k_lo[234]
  DIRECTION OUTPUT ;
  USE SIGNAL ;
  PORT
   LAYER M5 ;
   RECT 170.160 0.000 170.184 0.084 ;
  END
 END k_lo[234]
 PIN k_lo[235]
  DIRECTION OUTPUT ;
  USE SIGNAL ;
  PORT
   LAYER M5 ;
   RECT 170.352 0.000 170.376 0.084 ;
  END
 END k_lo[235]
 PIN k_lo[236]
  DIRECTION OUTPUT ;
  USE SIGNAL ;
  PORT
   LAYER M5 ;
   RECT 170.544 0.000 170.568 0.084 ;
  END
 END k_lo[236]
 PIN k_lo[237]
  DIRECTION OUTPUT ;
  USE SIGNAL ;
  PORT
   LAYER M5 ;
   RECT 170.736 0.000 170.760 0.084 ;
  END
 END k_lo[237]
 PIN k_lo[238]
  DIRECTION OUTPUT ;
  USE SIGNAL ;
  PORT
   LAYER M5 ;
   RECT 170.928 0.000 170.952 0.084 ;
  END
 END k_lo[238]
 PIN k_lo[239]
  DIRECTION OUTPUT ;
  USE SIGNAL ;
  PORT
   LAYER M5 ;
   RECT 171.120 0.000 171.144 0.084 ;
  END
 END k_lo[239]
 PIN k_lo[240]
  DIRECTION OUTPUT ;
  USE SIGNAL ;
  PORT
   LAYER M5 ;
   RECT 171.312 0.000 171.336 0.084 ;
  END
 END k_lo[240]
 PIN k_lo[241]
  DIRECTION OUTPUT ;
  USE SIGNAL ;
  PORT
   LAYER M5 ;
   RECT 171.504 0.000 171.528 0.084 ;
  END
 END k_lo[241]
 PIN k_lo[242]
  DIRECTION OUTPUT ;
  USE SIGNAL ;
  PORT
   LAYER M5 ;
   RECT 171.696 0.000 171.720 0.084 ;
  END
 END k_lo[242]
 PIN k_lo[243]
  DIRECTION OUTPUT ;
  USE SIGNAL ;
  PORT
   LAYER M5 ;
   RECT 171.888 0.000 171.912 0.084 ;
  END
 END k_lo[243]
 PIN k_lo[244]
  DIRECTION OUTPUT ;
  USE SIGNAL ;
  PORT
   LAYER M5 ;
   RECT 172.080 0.000 172.104 0.084 ;
  END
 END k_lo[244]
 PIN k_lo[245]
  DIRECTION OUTPUT ;
  USE SIGNAL ;
  PORT
   LAYER M5 ;
   RECT 172.272 0.000 172.296 0.084 ;
  END
 END k_lo[245]
 PIN k_lo[246]
  DIRECTION OUTPUT ;
  USE SIGNAL ;
  PORT
   LAYER M5 ;
   RECT 172.464 0.000 172.488 0.084 ;
  END
 END k_lo[246]
 PIN k_lo[247]
  DIRECTION OUTPUT ;
  USE SIGNAL ;
  PORT
   LAYER M5 ;
   RECT 172.656 0.000 172.680 0.084 ;
  END
 END k_lo[247]
 PIN k_lo[248]
  DIRECTION OUTPUT ;
  USE SIGNAL ;
  PORT
   LAYER M5 ;
   RECT 172.848 0.000 172.872 0.084 ;
  END
 END k_lo[248]
 PIN k_lo[249]
  DIRECTION OUTPUT ;
  USE SIGNAL ;
  PORT
   LAYER M5 ;
   RECT 173.040 0.000 173.064 0.084 ;
  END
 END k_lo[249]
 PIN k_lo[250]
  DIRECTION OUTPUT ;
  USE SIGNAL ;
  PORT
   LAYER M5 ;
   RECT 173.232 0.000 173.256 0.084 ;
  END
 END k_lo[250]
 PIN k_lo[251]
  DIRECTION OUTPUT ;
  USE SIGNAL ;
  PORT
   LAYER M5 ;
   RECT 173.424 0.000 173.448 0.084 ;
  END
 END k_lo[251]
 PIN k_lo[252]
  DIRECTION OUTPUT ;
  USE SIGNAL ;
  PORT
   LAYER M5 ;
   RECT 173.616 0.000 173.640 0.084 ;
  END
 END k_lo[252]
 PIN k_lo[253]
  DIRECTION OUTPUT ;
  USE SIGNAL ;
  PORT
   LAYER M5 ;
   RECT 173.808 0.000 173.832 0.084 ;
  END
 END k_lo[253]
 PIN k_lo[254]
  DIRECTION OUTPUT ;
  USE SIGNAL ;
  PORT
   LAYER M5 ;
   RECT 174.000 0.000 174.024 0.084 ;
  END
 END k_lo[254]
 PIN k_lo[255]
  DIRECTION OUTPUT ;
  USE SIGNAL ;
  PORT
   LAYER M5 ;
   RECT 174.192 0.000 174.216 0.084 ;
  END
 END k_lo[255]
 PIN k_lo[256]
  DIRECTION OUTPUT ;
  USE SIGNAL ;
  PORT
   LAYER M5 ;
   RECT 174.384 0.000 174.408 0.084 ;
  END
 END k_lo[256]
 PIN k_lo[257]
  DIRECTION OUTPUT ;
  USE SIGNAL ;
  PORT
   LAYER M5 ;
   RECT 174.576 0.000 174.600 0.084 ;
  END
 END k_lo[257]
 PIN k_lo[258]
  DIRECTION OUTPUT ;
  USE SIGNAL ;
  PORT
   LAYER M5 ;
   RECT 174.768 0.000 174.792 0.084 ;
  END
 END k_lo[258]
 PIN k_lo[259]
  DIRECTION OUTPUT ;
  USE SIGNAL ;
  PORT
   LAYER M5 ;
   RECT 174.960 0.000 174.984 0.084 ;
  END
 END k_lo[259]
 PIN k_lo[260]
  DIRECTION OUTPUT ;
  USE SIGNAL ;
  PORT
   LAYER M5 ;
   RECT 175.152 0.000 175.176 0.084 ;
  END
 END k_lo[260]
 PIN k_lo[261]
  DIRECTION OUTPUT ;
  USE SIGNAL ;
  PORT
   LAYER M5 ;
   RECT 175.344 0.000 175.368 0.084 ;
  END
 END k_lo[261]
 PIN k_lo[262]
  DIRECTION OUTPUT ;
  USE SIGNAL ;
  PORT
   LAYER M5 ;
   RECT 175.536 0.000 175.560 0.084 ;
  END
 END k_lo[262]
 PIN k_lo[263]
  DIRECTION OUTPUT ;
  USE SIGNAL ;
  PORT
   LAYER M5 ;
   RECT 175.728 0.000 175.752 0.084 ;
  END
 END k_lo[263]
 PIN k_lo[264]
  DIRECTION OUTPUT ;
  USE SIGNAL ;
  PORT
   LAYER M5 ;
   RECT 175.920 0.000 175.944 0.084 ;
  END
 END k_lo[264]
 PIN k_lo[265]
  DIRECTION OUTPUT ;
  USE SIGNAL ;
  PORT
   LAYER M5 ;
   RECT 176.112 0.000 176.136 0.084 ;
  END
 END k_lo[265]
 PIN k_lo[266]
  DIRECTION OUTPUT ;
  USE SIGNAL ;
  PORT
   LAYER M5 ;
   RECT 176.304 0.000 176.328 0.084 ;
  END
 END k_lo[266]
 PIN k_lo[267]
  DIRECTION OUTPUT ;
  USE SIGNAL ;
  PORT
   LAYER M5 ;
   RECT 176.496 0.000 176.520 0.084 ;
  END
 END k_lo[267]
 PIN k_lo[268]
  DIRECTION OUTPUT ;
  USE SIGNAL ;
  PORT
   LAYER M5 ;
   RECT 176.688 0.000 176.712 0.084 ;
  END
 END k_lo[268]
 PIN k_lo[269]
  DIRECTION OUTPUT ;
  USE SIGNAL ;
  PORT
   LAYER M5 ;
   RECT 176.880 0.000 176.904 0.084 ;
  END
 END k_lo[269]
 PIN k_lo[270]
  DIRECTION OUTPUT ;
  USE SIGNAL ;
  PORT
   LAYER M5 ;
   RECT 177.072 0.000 177.096 0.084 ;
  END
 END k_lo[270]
 PIN k_lo[271]
  DIRECTION OUTPUT ;
  USE SIGNAL ;
  PORT
   LAYER M5 ;
   RECT 177.264 0.000 177.288 0.084 ;
  END
 END k_lo[271]
 PIN k_lo[272]
  DIRECTION OUTPUT ;
  USE SIGNAL ;
  PORT
   LAYER M5 ;
   RECT 177.456 0.000 177.480 0.084 ;
  END
 END k_lo[272]
 PIN k_lo[273]
  DIRECTION OUTPUT ;
  USE SIGNAL ;
  PORT
   LAYER M5 ;
   RECT 177.648 0.000 177.672 0.084 ;
  END
 END k_lo[273]
 PIN k_lo[274]
  DIRECTION OUTPUT ;
  USE SIGNAL ;
  PORT
   LAYER M5 ;
   RECT 177.840 0.000 177.864 0.084 ;
  END
 END k_lo[274]
 PIN k_lo[275]
  DIRECTION OUTPUT ;
  USE SIGNAL ;
  PORT
   LAYER M5 ;
   RECT 178.032 0.000 178.056 0.084 ;
  END
 END k_lo[275]
 PIN k_lo[276]
  DIRECTION OUTPUT ;
  USE SIGNAL ;
  PORT
   LAYER M5 ;
   RECT 178.224 0.000 178.248 0.084 ;
  END
 END k_lo[276]
 PIN k_lo[277]
  DIRECTION OUTPUT ;
  USE SIGNAL ;
  PORT
   LAYER M5 ;
   RECT 178.416 0.000 178.440 0.084 ;
  END
 END k_lo[277]
 PIN k_lo[278]
  DIRECTION OUTPUT ;
  USE SIGNAL ;
  PORT
   LAYER M5 ;
   RECT 178.608 0.000 178.632 0.084 ;
  END
 END k_lo[278]
 PIN k_lo[279]
  DIRECTION OUTPUT ;
  USE SIGNAL ;
  PORT
   LAYER M5 ;
   RECT 178.800 0.000 178.824 0.084 ;
  END
 END k_lo[279]
 PIN k_lo[280]
  DIRECTION OUTPUT ;
  USE SIGNAL ;
  PORT
   LAYER M5 ;
   RECT 178.992 0.000 179.016 0.084 ;
  END
 END k_lo[280]
 PIN k_lo[281]
  DIRECTION OUTPUT ;
  USE SIGNAL ;
  PORT
   LAYER M5 ;
   RECT 179.184 0.000 179.208 0.084 ;
  END
 END k_lo[281]
 PIN k_lo[282]
  DIRECTION OUTPUT ;
  USE SIGNAL ;
  PORT
   LAYER M5 ;
   RECT 179.376 0.000 179.400 0.084 ;
  END
 END k_lo[282]
 PIN k_lo[283]
  DIRECTION OUTPUT ;
  USE SIGNAL ;
  PORT
   LAYER M5 ;
   RECT 179.568 0.000 179.592 0.084 ;
  END
 END k_lo[283]
 PIN k_lo[284]
  DIRECTION OUTPUT ;
  USE SIGNAL ;
  PORT
   LAYER M5 ;
   RECT 179.760 0.000 179.784 0.084 ;
  END
 END k_lo[284]
 PIN k_lo[285]
  DIRECTION OUTPUT ;
  USE SIGNAL ;
  PORT
   LAYER M5 ;
   RECT 179.952 0.000 179.976 0.084 ;
  END
 END k_lo[285]
 PIN k_lo[286]
  DIRECTION OUTPUT ;
  USE SIGNAL ;
  PORT
   LAYER M5 ;
   RECT 180.144 0.000 180.168 0.084 ;
  END
 END k_lo[286]
 PIN k_lo[287]
  DIRECTION OUTPUT ;
  USE SIGNAL ;
  PORT
   LAYER M5 ;
   RECT 180.336 0.000 180.360 0.084 ;
  END
 END k_lo[287]
 PIN k_lo[288]
  DIRECTION OUTPUT ;
  USE SIGNAL ;
  PORT
   LAYER M5 ;
   RECT 180.528 0.000 180.552 0.084 ;
  END
 END k_lo[288]
 PIN k_lo[289]
  DIRECTION OUTPUT ;
  USE SIGNAL ;
  PORT
   LAYER M5 ;
   RECT 180.720 0.000 180.744 0.084 ;
  END
 END k_lo[289]
 PIN k_lo[290]
  DIRECTION OUTPUT ;
  USE SIGNAL ;
  PORT
   LAYER M5 ;
   RECT 180.912 0.000 180.936 0.084 ;
  END
 END k_lo[290]
 PIN k_lo[291]
  DIRECTION OUTPUT ;
  USE SIGNAL ;
  PORT
   LAYER M5 ;
   RECT 181.104 0.000 181.128 0.084 ;
  END
 END k_lo[291]
 PIN k_lo[292]
  DIRECTION OUTPUT ;
  USE SIGNAL ;
  PORT
   LAYER M5 ;
   RECT 181.296 0.000 181.320 0.084 ;
  END
 END k_lo[292]
 PIN k_lo[293]
  DIRECTION OUTPUT ;
  USE SIGNAL ;
  PORT
   LAYER M5 ;
   RECT 181.488 0.000 181.512 0.084 ;
  END
 END k_lo[293]
 PIN k_lo[294]
  DIRECTION OUTPUT ;
  USE SIGNAL ;
  PORT
   LAYER M5 ;
   RECT 181.680 0.000 181.704 0.084 ;
  END
 END k_lo[294]
 PIN k_lo[295]
  DIRECTION OUTPUT ;
  USE SIGNAL ;
  PORT
   LAYER M5 ;
   RECT 181.872 0.000 181.896 0.084 ;
  END
 END k_lo[295]
 PIN k_lo[296]
  DIRECTION OUTPUT ;
  USE SIGNAL ;
  PORT
   LAYER M5 ;
   RECT 182.064 0.000 182.088 0.084 ;
  END
 END k_lo[296]
 PIN k_lo[297]
  DIRECTION OUTPUT ;
  USE SIGNAL ;
  PORT
   LAYER M5 ;
   RECT 182.256 0.000 182.280 0.084 ;
  END
 END k_lo[297]
 PIN k_lo[298]
  DIRECTION OUTPUT ;
  USE SIGNAL ;
  PORT
   LAYER M5 ;
   RECT 182.448 0.000 182.472 0.084 ;
  END
 END k_lo[298]
 PIN k_lo[299]
  DIRECTION OUTPUT ;
  USE SIGNAL ;
  PORT
   LAYER M5 ;
   RECT 182.640 0.000 182.664 0.084 ;
  END
 END k_lo[299]
 PIN k_lo[300]
  DIRECTION OUTPUT ;
  USE SIGNAL ;
  PORT
   LAYER M5 ;
   RECT 182.832 0.000 182.856 0.084 ;
  END
 END k_lo[300]
 PIN k_lo[301]
  DIRECTION OUTPUT ;
  USE SIGNAL ;
  PORT
   LAYER M5 ;
   RECT 183.024 0.000 183.048 0.084 ;
  END
 END k_lo[301]
 PIN k_lo[302]
  DIRECTION OUTPUT ;
  USE SIGNAL ;
  PORT
   LAYER M5 ;
   RECT 183.216 0.000 183.240 0.084 ;
  END
 END k_lo[302]
 PIN k_lo[303]
  DIRECTION OUTPUT ;
  USE SIGNAL ;
  PORT
   LAYER M5 ;
   RECT 183.408 0.000 183.432 0.084 ;
  END
 END k_lo[303]
 PIN k_lo[304]
  DIRECTION OUTPUT ;
  USE SIGNAL ;
  PORT
   LAYER M5 ;
   RECT 183.600 0.000 183.624 0.084 ;
  END
 END k_lo[304]
 PIN k_lo[305]
  DIRECTION OUTPUT ;
  USE SIGNAL ;
  PORT
   LAYER M5 ;
   RECT 183.792 0.000 183.816 0.084 ;
  END
 END k_lo[305]
 PIN k_lo[306]
  DIRECTION OUTPUT ;
  USE SIGNAL ;
  PORT
   LAYER M5 ;
   RECT 183.984 0.000 184.008 0.084 ;
  END
 END k_lo[306]
 PIN k_lo[307]
  DIRECTION OUTPUT ;
  USE SIGNAL ;
  PORT
   LAYER M5 ;
   RECT 184.176 0.000 184.200 0.084 ;
  END
 END k_lo[307]
 PIN k_lo[308]
  DIRECTION OUTPUT ;
  USE SIGNAL ;
  PORT
   LAYER M5 ;
   RECT 184.368 0.000 184.392 0.084 ;
  END
 END k_lo[308]
 PIN k_lo[309]
  DIRECTION OUTPUT ;
  USE SIGNAL ;
  PORT
   LAYER M5 ;
   RECT 184.560 0.000 184.584 0.084 ;
  END
 END k_lo[309]
 PIN k_L[0]
  DIRECTION OUTPUT ;
  USE SIGNAL ;
  PORT
   LAYER M5 ;
   RECT 184.752 0.000 184.776 0.084 ;
  END
 END k_L[0]
 PIN k_L[1]
  DIRECTION OUTPUT ;
  USE SIGNAL ;
  PORT
   LAYER M5 ;
   RECT 184.944 0.000 184.968 0.084 ;
  END
 END k_L[1]
 PIN k_L[2]
  DIRECTION OUTPUT ;
  USE SIGNAL ;
  PORT
   LAYER M5 ;
   RECT 185.136 0.000 185.160 0.084 ;
  END
 END k_L[2]
 PIN k_L[3]
  DIRECTION OUTPUT ;
  USE SIGNAL ;
  PORT
   LAYER M5 ;
   RECT 185.328 0.000 185.352 0.084 ;
  END
 END k_L[3]
 PIN k_L[4]
  DIRECTION OUTPUT ;
  USE SIGNAL ;
  PORT
   LAYER M5 ;
   RECT 185.520 0.000 185.544 0.084 ;
  END
 END k_L[4]
 PIN k_any
  DIRECTION OUTPUT ;
  USE SIGNAL ;
  PORT
   LAYER M5 ;
   RECT 185.712 0.000 185.736 0.084 ;
  END
 END k_any
 PIN lock
  DIRECTION OUTPUT ;
  USE SIGNAL ;
  PORT
   LAYER M5 ;
   RECT 185.904 0.000 185.928 0.084 ;
  END
 END lock
 PIN n_relock[0]
  DIRECTION OUTPUT ;
  USE SIGNAL ;
  PORT
   LAYER M5 ;
   RECT 186.096 0.000 186.120 0.084 ;
  END
 END n_relock[0]
 PIN n_relock[1]
  DIRECTION OUTPUT ;
  USE SIGNAL ;
  PORT
   LAYER M5 ;
   RECT 186.288 0.000 186.312 0.084 ;
  END
 END n_relock[1]
 PIN n_relock[2]
  DIRECTION OUTPUT ;
  USE SIGNAL ;
  PORT
   LAYER M5 ;
   RECT 186.480 0.000 186.504 0.084 ;
  END
 END n_relock[2]
 PIN n_relock[3]
  DIRECTION OUTPUT ;
  USE SIGNAL ;
  PORT
   LAYER M5 ;
   RECT 186.672 0.000 186.696 0.084 ;
  END
 END n_relock[3]
 PIN n_relock[4]
  DIRECTION OUTPUT ;
  USE SIGNAL ;
  PORT
   LAYER M5 ;
   RECT 186.864 0.000 186.888 0.084 ;
  END
 END n_relock[4]
 PIN n_relock[5]
  DIRECTION OUTPUT ;
  USE SIGNAL ;
  PORT
   LAYER M5 ;
   RECT 187.056 0.000 187.080 0.084 ;
  END
 END n_relock[5]
 PIN n_relock[6]
  DIRECTION OUTPUT ;
  USE SIGNAL ;
  PORT
   LAYER M5 ;
   RECT 187.248 0.000 187.272 0.084 ;
  END
 END n_relock[6]
 PIN n_relock[7]
  DIRECTION OUTPUT ;
  USE SIGNAL ;
  PORT
   LAYER M5 ;
   RECT 187.440 0.000 187.464 0.084 ;
  END
 END n_relock[7]
 PIN n_relock[8]
  DIRECTION OUTPUT ;
  USE SIGNAL ;
  PORT
   LAYER M5 ;
   RECT 187.632 0.000 187.656 0.084 ;
  END
 END n_relock[8]
 PIN n_relock[9]
  DIRECTION OUTPUT ;
  USE SIGNAL ;
  PORT
   LAYER M5 ;
   RECT 187.824 0.000 187.848 0.084 ;
  END
 END n_relock[9]
 PIN n_relock[10]
  DIRECTION OUTPUT ;
  USE SIGNAL ;
  PORT
   LAYER M5 ;
   RECT 188.016 0.000 188.040 0.084 ;
  END
 END n_relock[10]
 PIN n_relock[11]
  DIRECTION OUTPUT ;
  USE SIGNAL ;
  PORT
   LAYER M5 ;
   RECT 188.208 0.000 188.232 0.084 ;
  END
 END n_relock[11]
 PIN n_relock[12]
  DIRECTION OUTPUT ;
  USE SIGNAL ;
  PORT
   LAYER M5 ;
   RECT 188.400 0.000 188.424 0.084 ;
  END
 END n_relock[12]
 PIN n_relock[13]
  DIRECTION OUTPUT ;
  USE SIGNAL ;
  PORT
   LAYER M5 ;
   RECT 188.592 0.000 188.616 0.084 ;
  END
 END n_relock[13]
 PIN n_relock[14]
  DIRECTION OUTPUT ;
  USE SIGNAL ;
  PORT
   LAYER M5 ;
   RECT 188.784 0.000 188.808 0.084 ;
  END
 END n_relock[14]
 PIN n_relock[15]
  DIRECTION OUTPUT ;
  USE SIGNAL ;
  PORT
   LAYER M5 ;
   RECT 188.976 0.000 189.000 0.084 ;
  END
 END n_relock[15]
 PIN n_relock[16]
  DIRECTION OUTPUT ;
  USE SIGNAL ;
  PORT
   LAYER M5 ;
   RECT 189.168 0.000 189.192 0.084 ;
  END
 END n_relock[16]
 PIN n_relock[17]
  DIRECTION OUTPUT ;
  USE SIGNAL ;
  PORT
   LAYER M5 ;
   RECT 189.360 0.000 189.384 0.084 ;
  END
 END n_relock[17]
 PIN n_relock[18]
  DIRECTION OUTPUT ;
  USE SIGNAL ;
  PORT
   LAYER M5 ;
   RECT 189.552 0.000 189.576 0.084 ;
  END
 END n_relock[18]
 PIN n_relock[19]
  DIRECTION OUTPUT ;
  USE SIGNAL ;
  PORT
   LAYER M5 ;
   RECT 189.744 0.000 189.768 0.084 ;
  END
 END n_relock[19]
 PIN n_relock[20]
  DIRECTION OUTPUT ;
  USE SIGNAL ;
  PORT
   LAYER M5 ;
   RECT 189.936 0.000 189.960 0.084 ;
  END
 END n_relock[20]
 PIN n_relock[21]
  DIRECTION OUTPUT ;
  USE SIGNAL ;
  PORT
   LAYER M5 ;
   RECT 190.128 0.000 190.152 0.084 ;
  END
 END n_relock[21]
 PIN n_relock[22]
  DIRECTION OUTPUT ;
  USE SIGNAL ;
  PORT
   LAYER M5 ;
   RECT 190.320 0.000 190.344 0.084 ;
  END
 END n_relock[22]
 PIN n_relock[23]
  DIRECTION OUTPUT ;
  USE SIGNAL ;
  PORT
   LAYER M5 ;
   RECT 190.512 0.000 190.536 0.084 ;
  END
 END n_relock[23]
 PIN n_relock[24]
  DIRECTION OUTPUT ;
  USE SIGNAL ;
  PORT
   LAYER M5 ;
   RECT 190.704 0.000 190.728 0.084 ;
  END
 END n_relock[24]
 PIN n_relock[25]
  DIRECTION OUTPUT ;
  USE SIGNAL ;
  PORT
   LAYER M5 ;
   RECT 190.896 0.000 190.920 0.084 ;
  END
 END n_relock[25]
 PIN n_relock[26]
  DIRECTION OUTPUT ;
  USE SIGNAL ;
  PORT
   LAYER M5 ;
   RECT 191.088 0.000 191.112 0.084 ;
  END
 END n_relock[26]
 PIN n_relock[27]
  DIRECTION OUTPUT ;
  USE SIGNAL ;
  PORT
   LAYER M5 ;
   RECT 191.280 0.000 191.304 0.084 ;
  END
 END n_relock[27]
 PIN n_relock[28]
  DIRECTION OUTPUT ;
  USE SIGNAL ;
  PORT
   LAYER M5 ;
   RECT 191.472 0.000 191.496 0.084 ;
  END
 END n_relock[28]
 PIN n_relock[29]
  DIRECTION OUTPUT ;
  USE SIGNAL ;
  PORT
   LAYER M5 ;
   RECT 191.664 0.000 191.688 0.084 ;
  END
 END n_relock[29]
 PIN n_relock[30]
  DIRECTION OUTPUT ;
  USE SIGNAL ;
  PORT
   LAYER M5 ;
   RECT 191.856 0.000 191.880 0.084 ;
  END
 END n_relock[30]
 PIN n_relock[31]
  DIRECTION OUTPUT ;
  USE SIGNAL ;
  PORT
   LAYER M5 ;
   RECT 192.048 0.000 192.072 0.084 ;
  END
 END n_relock[31]
 PIN ck
  DIRECTION INPUT ;
  USE CLOCK ;
  PORT
   LAYER M5 ;
   RECT 108.000 189.996 108.024 190.080 ;
  END
 END ck
END ot_s81_rck_rxs
END LIBRARY
